VERSION 5.8 ;
BUSBITCHARS "[]" ;
DIVIDERCHAR "/" ;
UNITS
    DATABASE MICRONS 1000 ;
END UNITS

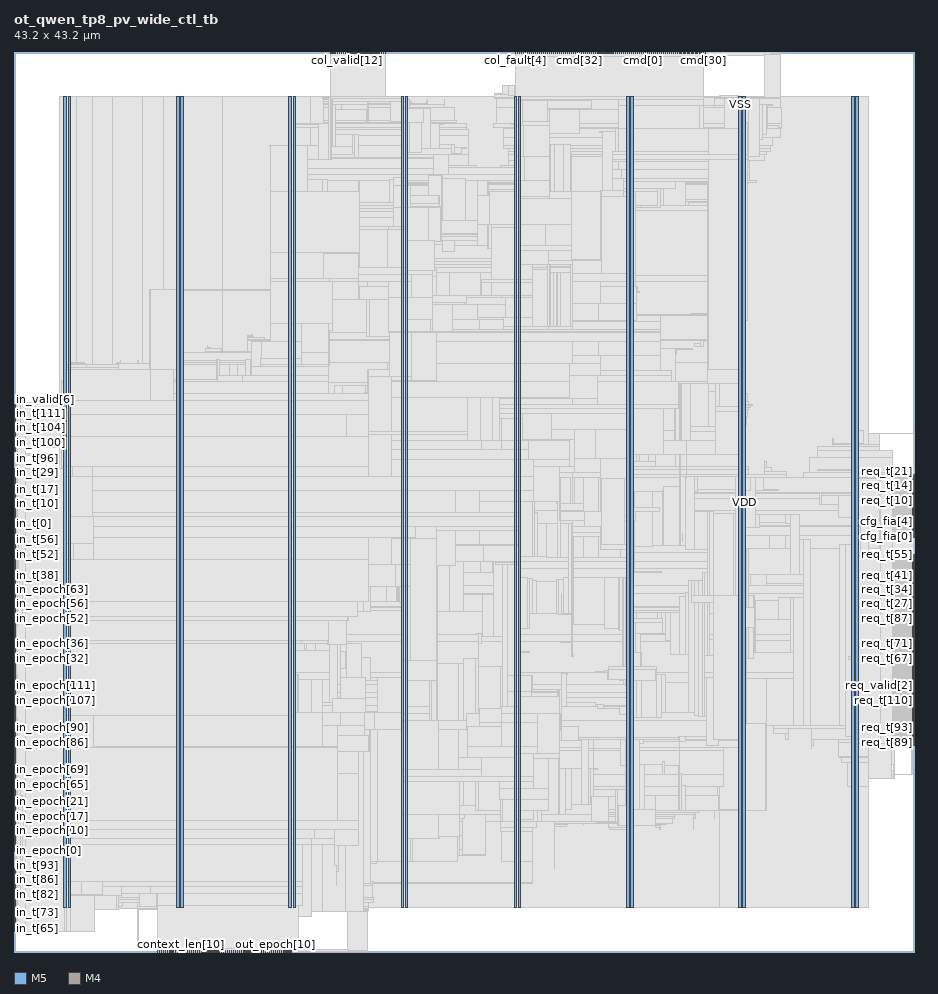
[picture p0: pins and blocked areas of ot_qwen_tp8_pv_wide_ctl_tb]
MACRO ot_qwen_tp8_pv_wide_ctl_tb
  FOREIGN ot_qwen_tp8_pv_wide_ctl_tb 0 0 ;
  CLASS BLOCK ;
  SIZE 43.2 BY 43.2 ;
  PIN busy
    DIRECTION OUTPUT ;
    USE SIGNAL ;
    PORT
      LAYER M5 ;
        RECT  6.864 0 6.888 0.084 ;
    END
  END busy
  PIN cfg_fia[0]
    DIRECTION INPUT ;
    USE SIGNAL ;
    PORT
      LAYER M4 ;
        RECT  43.116 19.92 43.2 19.944 ;
    END
  END cfg_fia[0]
  PIN cfg_fia[1]
    DIRECTION INPUT ;
    USE SIGNAL ;
    PORT
      LAYER M4 ;
        RECT  43.116 20.016 43.2 20.04 ;
    END
  END cfg_fia[1]
  PIN cfg_fia[2]
    DIRECTION INPUT ;
    USE SIGNAL ;
    PORT
      LAYER M4 ;
        RECT  43.116 20.112 43.2 20.136 ;
    END
  END cfg_fia[2]
  PIN cfg_fia[3]
    DIRECTION INPUT ;
    USE SIGNAL ;
    PORT
      LAYER M4 ;
        RECT  43.116 20.208 43.2 20.232 ;
    END
  END cfg_fia[3]
  PIN cfg_fia[4]
    DIRECTION INPUT ;
    USE SIGNAL ;
    PORT
      LAYER M4 ;
        RECT  43.116 20.304 43.2 20.328 ;
    END
  END cfg_fia[4]
  PIN cfg_fia[5]
    DIRECTION INPUT ;
    USE SIGNAL ;
    PORT
      LAYER M4 ;
        RECT  43.116 20.4 43.2 20.424 ;
    END
  END cfg_fia[5]
  PIN cfg_fia[6]
    DIRECTION INPUT ;
    USE SIGNAL ;
    PORT
      LAYER M4 ;
        RECT  43.116 20.496 43.2 20.52 ;
    END
  END cfg_fia[6]
  PIN cfg_fia[7]
    DIRECTION INPUT ;
    USE SIGNAL ;
    PORT
      LAYER M4 ;
        RECT  43.116 20.592 43.2 20.616 ;
    END
  END cfg_fia[7]
  PIN clk
    DIRECTION INPUT ;
    USE SIGNAL ;
    PORT
      LAYER M5 ;
        RECT  6.96 0 6.984 0.084 ;
    END
  END clk
  PIN cmd[0]
    DIRECTION OUTPUT ;
    USE SIGNAL ;
    PORT
      LAYER M5 ;
        RECT  30.192 43.116 30.216 43.2 ;
    END
  END cmd[0]
  PIN cmd[10]
    DIRECTION OUTPUT ;
    USE SIGNAL ;
    PORT
      LAYER M5 ;
        RECT  31.152 43.116 31.176 43.2 ;
    END
  END cmd[10]
  PIN cmd[11]
    DIRECTION OUTPUT ;
    USE SIGNAL ;
    PORT
      LAYER M5 ;
        RECT  31.248 43.116 31.272 43.2 ;
    END
  END cmd[11]
  PIN cmd[12]
    DIRECTION OUTPUT ;
    USE SIGNAL ;
    PORT
      LAYER M5 ;
        RECT  31.344 43.116 31.368 43.2 ;
    END
  END cmd[12]
  PIN cmd[13]
    DIRECTION OUTPUT ;
    USE SIGNAL ;
    PORT
      LAYER M5 ;
        RECT  31.44 43.116 31.464 43.2 ;
    END
  END cmd[13]
  PIN cmd[14]
    DIRECTION OUTPUT ;
    USE SIGNAL ;
    PORT
      LAYER M5 ;
        RECT  31.536 43.116 31.56 43.2 ;
    END
  END cmd[14]
  PIN cmd[15]
    DIRECTION OUTPUT ;
    USE SIGNAL ;
    PORT
      LAYER M5 ;
        RECT  31.632 43.116 31.656 43.2 ;
    END
  END cmd[15]
  PIN cmd[16]
    DIRECTION OUTPUT ;
    USE SIGNAL ;
    PORT
      LAYER M5 ;
        RECT  31.728 43.116 31.752 43.2 ;
    END
  END cmd[16]
  PIN cmd[17]
    DIRECTION OUTPUT ;
    USE SIGNAL ;
    PORT
      LAYER M5 ;
        RECT  31.824 43.116 31.848 43.2 ;
    END
  END cmd[17]
  PIN cmd[18]
    DIRECTION OUTPUT ;
    USE SIGNAL ;
    PORT
      LAYER M5 ;
        RECT  31.92 43.116 31.944 43.2 ;
    END
  END cmd[18]
  PIN cmd[19]
    DIRECTION OUTPUT ;
    USE SIGNAL ;
    PORT
      LAYER M5 ;
        RECT  32.016 43.116 32.04 43.2 ;
    END
  END cmd[19]
  PIN cmd[1]
    DIRECTION OUTPUT ;
    USE SIGNAL ;
    PORT
      LAYER M5 ;
        RECT  30.288 43.116 30.312 43.2 ;
    END
  END cmd[1]
  PIN cmd[20]
    DIRECTION OUTPUT ;
    USE SIGNAL ;
    PORT
      LAYER M5 ;
        RECT  32.112 43.116 32.136 43.2 ;
    END
  END cmd[20]
  PIN cmd[21]
    DIRECTION OUTPUT ;
    USE SIGNAL ;
    PORT
      LAYER M5 ;
        RECT  32.208 43.116 32.232 43.2 ;
    END
  END cmd[21]
  PIN cmd[22]
    DIRECTION OUTPUT ;
    USE SIGNAL ;
    PORT
      LAYER M5 ;
        RECT  32.304 43.116 32.328 43.2 ;
    END
  END cmd[22]
  PIN cmd[23]
    DIRECTION OUTPUT ;
    USE SIGNAL ;
    PORT
      LAYER M5 ;
        RECT  32.4 43.116 32.424 43.2 ;
    END
  END cmd[23]
  PIN cmd[24]
    DIRECTION OUTPUT ;
    USE SIGNAL ;
    PORT
      LAYER M5 ;
        RECT  32.496 43.116 32.52 43.2 ;
    END
  END cmd[24]
  PIN cmd[25]
    DIRECTION OUTPUT ;
    USE SIGNAL ;
    PORT
      LAYER M5 ;
        RECT  32.592 43.116 32.616 43.2 ;
    END
  END cmd[25]
  PIN cmd[26]
    DIRECTION OUTPUT ;
    USE SIGNAL ;
    PORT
      LAYER M5 ;
        RECT  32.688 43.116 32.712 43.2 ;
    END
  END cmd[26]
  PIN cmd[27]
    DIRECTION OUTPUT ;
    USE SIGNAL ;
    PORT
      LAYER M5 ;
        RECT  32.784 43.116 32.808 43.2 ;
    END
  END cmd[27]
  PIN cmd[28]
    DIRECTION OUTPUT ;
    USE SIGNAL ;
    PORT
      LAYER M5 ;
        RECT  32.88 43.116 32.904 43.2 ;
    END
  END cmd[28]
  PIN cmd[29]
    DIRECTION OUTPUT ;
    USE SIGNAL ;
    PORT
      LAYER M5 ;
        RECT  32.976 43.116 33 43.2 ;
    END
  END cmd[29]
  PIN cmd[2]
    DIRECTION OUTPUT ;
    USE SIGNAL ;
    PORT
      LAYER M5 ;
        RECT  30.384 43.116 30.408 43.2 ;
    END
  END cmd[2]
  PIN cmd[30]
    DIRECTION OUTPUT ;
    USE SIGNAL ;
    PORT
      LAYER M5 ;
        RECT  33.072 43.116 33.096 43.2 ;
    END
  END cmd[30]
  PIN cmd[31]
    DIRECTION OUTPUT ;
    USE SIGNAL ;
    PORT
      LAYER M5 ;
        RECT  33.168 43.116 33.192 43.2 ;
    END
  END cmd[31]
  PIN cmd[32]
    DIRECTION OUTPUT ;
    USE SIGNAL ;
    PORT
      LAYER M5 ;
        RECT  27.12 43.116 27.144 43.2 ;
    END
  END cmd[32]
  PIN cmd[33]
    DIRECTION OUTPUT ;
    USE SIGNAL ;
    PORT
      LAYER M5 ;
        RECT  27.216 43.116 27.24 43.2 ;
    END
  END cmd[33]
  PIN cmd[34]
    DIRECTION OUTPUT ;
    USE SIGNAL ;
    PORT
      LAYER M5 ;
        RECT  27.312 43.116 27.336 43.2 ;
    END
  END cmd[34]
  PIN cmd[35]
    DIRECTION OUTPUT ;
    USE SIGNAL ;
    PORT
      LAYER M5 ;
        RECT  27.408 43.116 27.432 43.2 ;
    END
  END cmd[35]
  PIN cmd[36]
    DIRECTION OUTPUT ;
    USE SIGNAL ;
    PORT
      LAYER M5 ;
        RECT  27.504 43.116 27.528 43.2 ;
    END
  END cmd[36]
  PIN cmd[37]
    DIRECTION OUTPUT ;
    USE SIGNAL ;
    PORT
      LAYER M5 ;
        RECT  27.6 43.116 27.624 43.2 ;
    END
  END cmd[37]
  PIN cmd[38]
    DIRECTION OUTPUT ;
    USE SIGNAL ;
    PORT
      LAYER M5 ;
        RECT  27.696 43.116 27.72 43.2 ;
    END
  END cmd[38]
  PIN cmd[39]
    DIRECTION OUTPUT ;
    USE SIGNAL ;
    PORT
      LAYER M5 ;
        RECT  27.792 43.116 27.816 43.2 ;
    END
  END cmd[39]
  PIN cmd[3]
    DIRECTION OUTPUT ;
    USE SIGNAL ;
    PORT
      LAYER M5 ;
        RECT  30.48 43.116 30.504 43.2 ;
    END
  END cmd[3]
  PIN cmd[40]
    DIRECTION OUTPUT ;
    USE SIGNAL ;
    PORT
      LAYER M5 ;
        RECT  27.888 43.116 27.912 43.2 ;
    END
  END cmd[40]
  PIN cmd[41]
    DIRECTION OUTPUT ;
    USE SIGNAL ;
    PORT
      LAYER M5 ;
        RECT  27.984 43.116 28.008 43.2 ;
    END
  END cmd[41]
  PIN cmd[42]
    DIRECTION OUTPUT ;
    USE SIGNAL ;
    PORT
      LAYER M5 ;
        RECT  28.08 43.116 28.104 43.2 ;
    END
  END cmd[42]
  PIN cmd[43]
    DIRECTION OUTPUT ;
    USE SIGNAL ;
    PORT
      LAYER M5 ;
        RECT  28.176 43.116 28.2 43.2 ;
    END
  END cmd[43]
  PIN cmd[44]
    DIRECTION OUTPUT ;
    USE SIGNAL ;
    PORT
      LAYER M5 ;
        RECT  28.272 43.116 28.296 43.2 ;
    END
  END cmd[44]
  PIN cmd[45]
    DIRECTION OUTPUT ;
    USE SIGNAL ;
    PORT
      LAYER M5 ;
        RECT  28.368 43.116 28.392 43.2 ;
    END
  END cmd[45]
  PIN cmd[46]
    DIRECTION OUTPUT ;
    USE SIGNAL ;
    PORT
      LAYER M5 ;
        RECT  28.464 43.116 28.488 43.2 ;
    END
  END cmd[46]
  PIN cmd[47]
    DIRECTION OUTPUT ;
    USE SIGNAL ;
    PORT
      LAYER M5 ;
        RECT  28.56 43.116 28.584 43.2 ;
    END
  END cmd[47]
  PIN cmd[48]
    DIRECTION OUTPUT ;
    USE SIGNAL ;
    PORT
      LAYER M5 ;
        RECT  28.656 43.116 28.68 43.2 ;
    END
  END cmd[48]
  PIN cmd[49]
    DIRECTION OUTPUT ;
    USE SIGNAL ;
    PORT
      LAYER M5 ;
        RECT  28.752 43.116 28.776 43.2 ;
    END
  END cmd[49]
  PIN cmd[4]
    DIRECTION OUTPUT ;
    USE SIGNAL ;
    PORT
      LAYER M5 ;
        RECT  30.576 43.116 30.6 43.2 ;
    END
  END cmd[4]
  PIN cmd[50]
    DIRECTION OUTPUT ;
    USE SIGNAL ;
    PORT
      LAYER M5 ;
        RECT  28.848 43.116 28.872 43.2 ;
    END
  END cmd[50]
  PIN cmd[51]
    DIRECTION OUTPUT ;
    USE SIGNAL ;
    PORT
      LAYER M5 ;
        RECT  28.944 43.116 28.968 43.2 ;
    END
  END cmd[51]
  PIN cmd[52]
    DIRECTION OUTPUT ;
    USE SIGNAL ;
    PORT
      LAYER M5 ;
        RECT  29.04 43.116 29.064 43.2 ;
    END
  END cmd[52]
  PIN cmd[53]
    DIRECTION OUTPUT ;
    USE SIGNAL ;
    PORT
      LAYER M5 ;
        RECT  29.136 43.116 29.16 43.2 ;
    END
  END cmd[53]
  PIN cmd[54]
    DIRECTION OUTPUT ;
    USE SIGNAL ;
    PORT
      LAYER M5 ;
        RECT  29.232 43.116 29.256 43.2 ;
    END
  END cmd[54]
  PIN cmd[55]
    DIRECTION OUTPUT ;
    USE SIGNAL ;
    PORT
      LAYER M5 ;
        RECT  29.328 43.116 29.352 43.2 ;
    END
  END cmd[55]
  PIN cmd[56]
    DIRECTION OUTPUT ;
    USE SIGNAL ;
    PORT
      LAYER M5 ;
        RECT  29.424 43.116 29.448 43.2 ;
    END
  END cmd[56]
  PIN cmd[57]
    DIRECTION OUTPUT ;
    USE SIGNAL ;
    PORT
      LAYER M5 ;
        RECT  29.52 43.116 29.544 43.2 ;
    END
  END cmd[57]
  PIN cmd[58]
    DIRECTION OUTPUT ;
    USE SIGNAL ;
    PORT
      LAYER M5 ;
        RECT  29.616 43.116 29.64 43.2 ;
    END
  END cmd[58]
  PIN cmd[59]
    DIRECTION OUTPUT ;
    USE SIGNAL ;
    PORT
      LAYER M5 ;
        RECT  29.712 43.116 29.736 43.2 ;
    END
  END cmd[59]
  PIN cmd[5]
    DIRECTION OUTPUT ;
    USE SIGNAL ;
    PORT
      LAYER M5 ;
        RECT  30.672 43.116 30.696 43.2 ;
    END
  END cmd[5]
  PIN cmd[6]
    DIRECTION OUTPUT ;
    USE SIGNAL ;
    PORT
      LAYER M5 ;
        RECT  30.768 43.116 30.792 43.2 ;
    END
  END cmd[6]
  PIN cmd[7]
    DIRECTION OUTPUT ;
    USE SIGNAL ;
    PORT
      LAYER M5 ;
        RECT  30.864 43.116 30.888 43.2 ;
    END
  END cmd[7]
  PIN cmd[8]
    DIRECTION OUTPUT ;
    USE SIGNAL ;
    PORT
      LAYER M5 ;
        RECT  30.96 43.116 30.984 43.2 ;
    END
  END cmd[8]
  PIN cmd[9]
    DIRECTION OUTPUT ;
    USE SIGNAL ;
    PORT
      LAYER M5 ;
        RECT  31.056 43.116 31.08 43.2 ;
    END
  END cmd[9]
  PIN col_fault[0]
    DIRECTION INPUT ;
    USE SIGNAL ;
    PORT
      LAYER M5 ;
        RECT  29.808 43.116 29.832 43.2 ;
    END
  END col_fault[0]
  PIN col_fault[10]
    DIRECTION INPUT ;
    USE SIGNAL ;
    PORT
      LAYER M5 ;
        RECT  24.624 43.116 24.648 43.2 ;
    END
  END col_fault[10]
  PIN col_fault[11]
    DIRECTION INPUT ;
    USE SIGNAL ;
    PORT
      LAYER M5 ;
        RECT  24.72 43.116 24.744 43.2 ;
    END
  END col_fault[11]
  PIN col_fault[12]
    DIRECTION INPUT ;
    USE SIGNAL ;
    PORT
      LAYER M5 ;
        RECT  24.816 43.116 24.84 43.2 ;
    END
  END col_fault[12]
  PIN col_fault[13]
    DIRECTION INPUT ;
    USE SIGNAL ;
    PORT
      LAYER M5 ;
        RECT  24.912 43.116 24.936 43.2 ;
    END
  END col_fault[13]
  PIN col_fault[14]
    DIRECTION INPUT ;
    USE SIGNAL ;
    PORT
      LAYER M5 ;
        RECT  25.008 43.116 25.032 43.2 ;
    END
  END col_fault[14]
  PIN col_fault[15]
    DIRECTION INPUT ;
    USE SIGNAL ;
    PORT
      LAYER M5 ;
        RECT  25.104 43.116 25.128 43.2 ;
    END
  END col_fault[15]
  PIN col_fault[16]
    DIRECTION INPUT ;
    USE SIGNAL ;
    PORT
      LAYER M5 ;
        RECT  25.2 43.116 25.224 43.2 ;
    END
  END col_fault[16]
  PIN col_fault[17]
    DIRECTION INPUT ;
    USE SIGNAL ;
    PORT
      LAYER M5 ;
        RECT  25.296 43.116 25.32 43.2 ;
    END
  END col_fault[17]
  PIN col_fault[18]
    DIRECTION INPUT ;
    USE SIGNAL ;
    PORT
      LAYER M5 ;
        RECT  25.392 43.116 25.416 43.2 ;
    END
  END col_fault[18]
  PIN col_fault[19]
    DIRECTION INPUT ;
    USE SIGNAL ;
    PORT
      LAYER M5 ;
        RECT  25.488 43.116 25.512 43.2 ;
    END
  END col_fault[19]
  PIN col_fault[1]
    DIRECTION INPUT ;
    USE SIGNAL ;
    PORT
      LAYER M5 ;
        RECT  29.904 43.116 29.928 43.2 ;
    END
  END col_fault[1]
  PIN col_fault[20]
    DIRECTION INPUT ;
    USE SIGNAL ;
    PORT
      LAYER M5 ;
        RECT  25.584 43.116 25.608 43.2 ;
    END
  END col_fault[20]
  PIN col_fault[21]
    DIRECTION INPUT ;
    USE SIGNAL ;
    PORT
      LAYER M5 ;
        RECT  25.68 43.116 25.704 43.2 ;
    END
  END col_fault[21]
  PIN col_fault[22]
    DIRECTION INPUT ;
    USE SIGNAL ;
    PORT
      LAYER M5 ;
        RECT  25.776 43.116 25.8 43.2 ;
    END
  END col_fault[22]
  PIN col_fault[23]
    DIRECTION INPUT ;
    USE SIGNAL ;
    PORT
      LAYER M5 ;
        RECT  25.872 43.116 25.896 43.2 ;
    END
  END col_fault[23]
  PIN col_fault[24]
    DIRECTION INPUT ;
    USE SIGNAL ;
    PORT
      LAYER M5 ;
        RECT  25.968 43.116 25.992 43.2 ;
    END
  END col_fault[24]
  PIN col_fault[25]
    DIRECTION INPUT ;
    USE SIGNAL ;
    PORT
      LAYER M5 ;
        RECT  26.064 43.116 26.088 43.2 ;
    END
  END col_fault[25]
  PIN col_fault[26]
    DIRECTION INPUT ;
    USE SIGNAL ;
    PORT
      LAYER M5 ;
        RECT  26.16 43.116 26.184 43.2 ;
    END
  END col_fault[26]
  PIN col_fault[27]
    DIRECTION INPUT ;
    USE SIGNAL ;
    PORT
      LAYER M5 ;
        RECT  26.256 43.116 26.28 43.2 ;
    END
  END col_fault[27]
  PIN col_fault[28]
    DIRECTION INPUT ;
    USE SIGNAL ;
    PORT
      LAYER M5 ;
        RECT  26.352 43.116 26.376 43.2 ;
    END
  END col_fault[28]
  PIN col_fault[29]
    DIRECTION INPUT ;
    USE SIGNAL ;
    PORT
      LAYER M5 ;
        RECT  26.448 43.116 26.472 43.2 ;
    END
  END col_fault[29]
  PIN col_fault[2]
    DIRECTION INPUT ;
    USE SIGNAL ;
    PORT
      LAYER M5 ;
        RECT  30 43.116 30.024 43.2 ;
    END
  END col_fault[2]
  PIN col_fault[30]
    DIRECTION INPUT ;
    USE SIGNAL ;
    PORT
      LAYER M5 ;
        RECT  26.544 43.116 26.568 43.2 ;
    END
  END col_fault[30]
  PIN col_fault[31]
    DIRECTION INPUT ;
    USE SIGNAL ;
    PORT
      LAYER M5 ;
        RECT  26.64 43.116 26.664 43.2 ;
    END
  END col_fault[31]
  PIN col_fault[3]
    DIRECTION INPUT ;
    USE SIGNAL ;
    PORT
      LAYER M5 ;
        RECT  30.096 43.116 30.12 43.2 ;
    END
  END col_fault[3]
  PIN col_fault[4]
    DIRECTION INPUT ;
    USE SIGNAL ;
    PORT
      LAYER M5 ;
        RECT  24.048 43.116 24.072 43.2 ;
    END
  END col_fault[4]
  PIN col_fault[5]
    DIRECTION INPUT ;
    USE SIGNAL ;
    PORT
      LAYER M5 ;
        RECT  24.144 43.116 24.168 43.2 ;
    END
  END col_fault[5]
  PIN col_fault[6]
    DIRECTION INPUT ;
    USE SIGNAL ;
    PORT
      LAYER M5 ;
        RECT  24.24 43.116 24.264 43.2 ;
    END
  END col_fault[6]
  PIN col_fault[7]
    DIRECTION INPUT ;
    USE SIGNAL ;
    PORT
      LAYER M5 ;
        RECT  24.336 43.116 24.36 43.2 ;
    END
  END col_fault[7]
  PIN col_fault[8]
    DIRECTION INPUT ;
    USE SIGNAL ;
    PORT
      LAYER M5 ;
        RECT  24.432 43.116 24.456 43.2 ;
    END
  END col_fault[8]
  PIN col_fault[9]
    DIRECTION INPUT ;
    USE SIGNAL ;
    PORT
      LAYER M5 ;
        RECT  24.528 43.116 24.552 43.2 ;
    END
  END col_fault[9]
  PIN col_valid[0]
    DIRECTION INPUT ;
    USE SIGNAL ;
    PORT
      LAYER M5 ;
        RECT  26.736 43.116 26.76 43.2 ;
    END
  END col_valid[0]
  PIN col_valid[10]
    DIRECTION INPUT ;
    USE SIGNAL ;
    PORT
      LAYER M5 ;
        RECT  15.792 43.116 15.816 43.2 ;
    END
  END col_valid[10]
  PIN col_valid[11]
    DIRECTION INPUT ;
    USE SIGNAL ;
    PORT
      LAYER M5 ;
        RECT  15.888 43.116 15.912 43.2 ;
    END
  END col_valid[11]
  PIN col_valid[12]
    DIRECTION INPUT ;
    USE SIGNAL ;
    PORT
      LAYER M5 ;
        RECT  15.984 43.116 16.008 43.2 ;
    END
  END col_valid[12]
  PIN col_valid[13]
    DIRECTION INPUT ;
    USE SIGNAL ;
    PORT
      LAYER M5 ;
        RECT  16.08 43.116 16.104 43.2 ;
    END
  END col_valid[13]
  PIN col_valid[14]
    DIRECTION INPUT ;
    USE SIGNAL ;
    PORT
      LAYER M5 ;
        RECT  16.176 43.116 16.2 43.2 ;
    END
  END col_valid[14]
  PIN col_valid[15]
    DIRECTION INPUT ;
    USE SIGNAL ;
    PORT
      LAYER M5 ;
        RECT  16.272 43.116 16.296 43.2 ;
    END
  END col_valid[15]
  PIN col_valid[16]
    DIRECTION INPUT ;
    USE SIGNAL ;
    PORT
      LAYER M5 ;
        RECT  16.368 43.116 16.392 43.2 ;
    END
  END col_valid[16]
  PIN col_valid[17]
    DIRECTION INPUT ;
    USE SIGNAL ;
    PORT
      LAYER M5 ;
        RECT  16.464 43.116 16.488 43.2 ;
    END
  END col_valid[17]
  PIN col_valid[18]
    DIRECTION INPUT ;
    USE SIGNAL ;
    PORT
      LAYER M5 ;
        RECT  16.56 43.116 16.584 43.2 ;
    END
  END col_valid[18]
  PIN col_valid[19]
    DIRECTION INPUT ;
    USE SIGNAL ;
    PORT
      LAYER M5 ;
        RECT  16.656 43.116 16.68 43.2 ;
    END
  END col_valid[19]
  PIN col_valid[1]
    DIRECTION INPUT ;
    USE SIGNAL ;
    PORT
      LAYER M5 ;
        RECT  26.832 43.116 26.856 43.2 ;
    END
  END col_valid[1]
  PIN col_valid[20]
    DIRECTION INPUT ;
    USE SIGNAL ;
    PORT
      LAYER M5 ;
        RECT  16.752 43.116 16.776 43.2 ;
    END
  END col_valid[20]
  PIN col_valid[21]
    DIRECTION INPUT ;
    USE SIGNAL ;
    PORT
      LAYER M5 ;
        RECT  16.848 43.116 16.872 43.2 ;
    END
  END col_valid[21]
  PIN col_valid[22]
    DIRECTION INPUT ;
    USE SIGNAL ;
    PORT
      LAYER M5 ;
        RECT  16.944 43.116 16.968 43.2 ;
    END
  END col_valid[22]
  PIN col_valid[23]
    DIRECTION INPUT ;
    USE SIGNAL ;
    PORT
      LAYER M5 ;
        RECT  17.04 43.116 17.064 43.2 ;
    END
  END col_valid[23]
  PIN col_valid[24]
    DIRECTION INPUT ;
    USE SIGNAL ;
    PORT
      LAYER M5 ;
        RECT  17.136 43.116 17.16 43.2 ;
    END
  END col_valid[24]
  PIN col_valid[25]
    DIRECTION INPUT ;
    USE SIGNAL ;
    PORT
      LAYER M5 ;
        RECT  17.232 43.116 17.256 43.2 ;
    END
  END col_valid[25]
  PIN col_valid[26]
    DIRECTION INPUT ;
    USE SIGNAL ;
    PORT
      LAYER M5 ;
        RECT  17.328 43.116 17.352 43.2 ;
    END
  END col_valid[26]
  PIN col_valid[27]
    DIRECTION INPUT ;
    USE SIGNAL ;
    PORT
      LAYER M5 ;
        RECT  17.424 43.116 17.448 43.2 ;
    END
  END col_valid[27]
  PIN col_valid[28]
    DIRECTION INPUT ;
    USE SIGNAL ;
    PORT
      LAYER M5 ;
        RECT  17.52 43.116 17.544 43.2 ;
    END
  END col_valid[28]
  PIN col_valid[29]
    DIRECTION INPUT ;
    USE SIGNAL ;
    PORT
      LAYER M5 ;
        RECT  17.616 43.116 17.64 43.2 ;
    END
  END col_valid[29]
  PIN col_valid[2]
    DIRECTION INPUT ;
    USE SIGNAL ;
    PORT
      LAYER M5 ;
        RECT  26.928 43.116 26.952 43.2 ;
    END
  END col_valid[2]
  PIN col_valid[30]
    DIRECTION INPUT ;
    USE SIGNAL ;
    PORT
      LAYER M5 ;
        RECT  17.712 43.116 17.736 43.2 ;
    END
  END col_valid[30]
  PIN col_valid[31]
    DIRECTION INPUT ;
    USE SIGNAL ;
    PORT
      LAYER M5 ;
        RECT  17.808 43.116 17.832 43.2 ;
    END
  END col_valid[31]
  PIN col_valid[3]
    DIRECTION INPUT ;
    USE SIGNAL ;
    PORT
      LAYER M5 ;
        RECT  27.024 43.116 27.048 43.2 ;
    END
  END col_valid[3]
  PIN col_valid[4]
    DIRECTION INPUT ;
    USE SIGNAL ;
    PORT
      LAYER M5 ;
        RECT  15.216 43.116 15.24 43.2 ;
    END
  END col_valid[4]
  PIN col_valid[5]
    DIRECTION INPUT ;
    USE SIGNAL ;
    PORT
      LAYER M5 ;
        RECT  15.312 43.116 15.336 43.2 ;
    END
  END col_valid[5]
  PIN col_valid[6]
    DIRECTION INPUT ;
    USE SIGNAL ;
    PORT
      LAYER M5 ;
        RECT  15.408 43.116 15.432 43.2 ;
    END
  END col_valid[6]
  PIN col_valid[7]
    DIRECTION INPUT ;
    USE SIGNAL ;
    PORT
      LAYER M5 ;
        RECT  15.504 43.116 15.528 43.2 ;
    END
  END col_valid[7]
  PIN col_valid[8]
    DIRECTION INPUT ;
    USE SIGNAL ;
    PORT
      LAYER M5 ;
        RECT  15.6 43.116 15.624 43.2 ;
    END
  END col_valid[8]
  PIN col_valid[9]
    DIRECTION INPUT ;
    USE SIGNAL ;
    PORT
      LAYER M5 ;
        RECT  15.696 43.116 15.72 43.2 ;
    END
  END col_valid[9]
  PIN context_len[0]
    DIRECTION INPUT ;
    USE SIGNAL ;
    PORT
      LAYER M5 ;
        RECT  7.056 0 7.08 0.084 ;
    END
  END context_len[0]
  PIN context_len[10]
    DIRECTION INPUT ;
    USE SIGNAL ;
    PORT
      LAYER M5 ;
        RECT  8.016 0 8.04 0.084 ;
    END
  END context_len[10]
  PIN context_len[11]
    DIRECTION INPUT ;
    USE SIGNAL ;
    PORT
      LAYER M5 ;
        RECT  8.112 0 8.136 0.084 ;
    END
  END context_len[11]
  PIN context_len[12]
    DIRECTION INPUT ;
    USE SIGNAL ;
    PORT
      LAYER M5 ;
        RECT  8.208 0 8.232 0.084 ;
    END
  END context_len[12]
  PIN context_len[13]
    DIRECTION INPUT ;
    USE SIGNAL ;
    PORT
      LAYER M5 ;
        RECT  8.304 0 8.328 0.084 ;
    END
  END context_len[13]
  PIN context_len[1]
    DIRECTION INPUT ;
    USE SIGNAL ;
    PORT
      LAYER M5 ;
        RECT  7.152 0 7.176 0.084 ;
    END
  END context_len[1]
  PIN context_len[2]
    DIRECTION INPUT ;
    USE SIGNAL ;
    PORT
      LAYER M5 ;
        RECT  7.248 0 7.272 0.084 ;
    END
  END context_len[2]
  PIN context_len[3]
    DIRECTION INPUT ;
    USE SIGNAL ;
    PORT
      LAYER M5 ;
        RECT  7.344 0 7.368 0.084 ;
    END
  END context_len[3]
  PIN context_len[4]
    DIRECTION INPUT ;
    USE SIGNAL ;
    PORT
      LAYER M5 ;
        RECT  7.44 0 7.464 0.084 ;
    END
  END context_len[4]
  PIN context_len[5]
    DIRECTION INPUT ;
    USE SIGNAL ;
    PORT
      LAYER M5 ;
        RECT  7.536 0 7.56 0.084 ;
    END
  END context_len[5]
  PIN context_len[6]
    DIRECTION INPUT ;
    USE SIGNAL ;
    PORT
      LAYER M5 ;
        RECT  7.632 0 7.656 0.084 ;
    END
  END context_len[6]
  PIN context_len[7]
    DIRECTION INPUT ;
    USE SIGNAL ;
    PORT
      LAYER M5 ;
        RECT  7.728 0 7.752 0.084 ;
    END
  END context_len[7]
  PIN context_len[8]
    DIRECTION INPUT ;
    USE SIGNAL ;
    PORT
      LAYER M5 ;
        RECT  7.824 0 7.848 0.084 ;
    END
  END context_len[8]
  PIN context_len[9]
    DIRECTION INPUT ;
    USE SIGNAL ;
    PORT
      LAYER M5 ;
        RECT  7.92 0 7.944 0.084 ;
    END
  END context_len[9]
  PIN epoch[0]
    DIRECTION INPUT ;
    USE SIGNAL ;
    PORT
      LAYER M5 ;
        RECT  8.4 0 8.424 0.084 ;
    END
  END epoch[0]
  PIN epoch[10]
    DIRECTION INPUT ;
    USE SIGNAL ;
    PORT
      LAYER M5 ;
        RECT  9.36 0 9.384 0.084 ;
    END
  END epoch[10]
  PIN epoch[11]
    DIRECTION INPUT ;
    USE SIGNAL ;
    PORT
      LAYER M5 ;
        RECT  9.456 0 9.48 0.084 ;
    END
  END epoch[11]
  PIN epoch[12]
    DIRECTION INPUT ;
    USE SIGNAL ;
    PORT
      LAYER M5 ;
        RECT  9.552 0 9.576 0.084 ;
    END
  END epoch[12]
  PIN epoch[13]
    DIRECTION INPUT ;
    USE SIGNAL ;
    PORT
      LAYER M5 ;
        RECT  9.648 0 9.672 0.084 ;
    END
  END epoch[13]
  PIN epoch[14]
    DIRECTION INPUT ;
    USE SIGNAL ;
    PORT
      LAYER M5 ;
        RECT  9.744 0 9.768 0.084 ;
    END
  END epoch[14]
  PIN epoch[15]
    DIRECTION INPUT ;
    USE SIGNAL ;
    PORT
      LAYER M5 ;
        RECT  9.84 0 9.864 0.084 ;
    END
  END epoch[15]
  PIN epoch[1]
    DIRECTION INPUT ;
    USE SIGNAL ;
    PORT
      LAYER M5 ;
        RECT  8.496 0 8.52 0.084 ;
    END
  END epoch[1]
  PIN epoch[2]
    DIRECTION INPUT ;
    USE SIGNAL ;
    PORT
      LAYER M5 ;
        RECT  8.592 0 8.616 0.084 ;
    END
  END epoch[2]
  PIN epoch[3]
    DIRECTION INPUT ;
    USE SIGNAL ;
    PORT
      LAYER M5 ;
        RECT  8.688 0 8.712 0.084 ;
    END
  END epoch[3]
  PIN epoch[4]
    DIRECTION INPUT ;
    USE SIGNAL ;
    PORT
      LAYER M5 ;
        RECT  8.784 0 8.808 0.084 ;
    END
  END epoch[4]
  PIN epoch[5]
    DIRECTION INPUT ;
    USE SIGNAL ;
    PORT
      LAYER M5 ;
        RECT  8.88 0 8.904 0.084 ;
    END
  END epoch[5]
  PIN epoch[6]
    DIRECTION INPUT ;
    USE SIGNAL ;
    PORT
      LAYER M5 ;
        RECT  8.976 0 9 0.084 ;
    END
  END epoch[6]
  PIN epoch[7]
    DIRECTION INPUT ;
    USE SIGNAL ;
    PORT
      LAYER M5 ;
        RECT  9.072 0 9.096 0.084 ;
    END
  END epoch[7]
  PIN epoch[8]
    DIRECTION INPUT ;
    USE SIGNAL ;
    PORT
      LAYER M5 ;
        RECT  9.168 0 9.192 0.084 ;
    END
  END epoch[8]
  PIN epoch[9]
    DIRECTION INPUT ;
    USE SIGNAL ;
    PORT
      LAYER M5 ;
        RECT  9.264 0 9.288 0.084 ;
    END
  END epoch[9]
  PIN fault
    DIRECTION OUTPUT ;
    USE SIGNAL ;
    PORT
      LAYER M5 ;
        RECT  9.936 0 9.96 0.084 ;
    END
  END fault
  PIN in_epoch[0]
    DIRECTION INPUT ;
    USE SIGNAL ;
    PORT
      LAYER M4 ;
        RECT  0 4.848 0.084 4.872 ;
    END
  END in_epoch[0]
  PIN in_epoch[100]
    DIRECTION INPUT ;
    USE SIGNAL ;
    PORT
      LAYER M4 ;
        RECT  0 11.376 0.084 11.4 ;
    END
  END in_epoch[100]
  PIN in_epoch[101]
    DIRECTION INPUT ;
    USE SIGNAL ;
    PORT
      LAYER M4 ;
        RECT  0 11.472 0.084 11.496 ;
    END
  END in_epoch[101]
  PIN in_epoch[102]
    DIRECTION INPUT ;
    USE SIGNAL ;
    PORT
      LAYER M4 ;
        RECT  0 11.568 0.084 11.592 ;
    END
  END in_epoch[102]
  PIN in_epoch[103]
    DIRECTION INPUT ;
    USE SIGNAL ;
    PORT
      LAYER M4 ;
        RECT  0 11.664 0.084 11.688 ;
    END
  END in_epoch[103]
  PIN in_epoch[104]
    DIRECTION INPUT ;
    USE SIGNAL ;
    PORT
      LAYER M4 ;
        RECT  0 11.76 0.084 11.784 ;
    END
  END in_epoch[104]
  PIN in_epoch[105]
    DIRECTION INPUT ;
    USE SIGNAL ;
    PORT
      LAYER M4 ;
        RECT  0 11.856 0.084 11.88 ;
    END
  END in_epoch[105]
  PIN in_epoch[106]
    DIRECTION INPUT ;
    USE SIGNAL ;
    PORT
      LAYER M4 ;
        RECT  0 11.952 0.084 11.976 ;
    END
  END in_epoch[106]
  PIN in_epoch[107]
    DIRECTION INPUT ;
    USE SIGNAL ;
    PORT
      LAYER M4 ;
        RECT  0 12.048 0.084 12.072 ;
    END
  END in_epoch[107]
  PIN in_epoch[108]
    DIRECTION INPUT ;
    USE SIGNAL ;
    PORT
      LAYER M4 ;
        RECT  0 12.144 0.084 12.168 ;
    END
  END in_epoch[108]
  PIN in_epoch[109]
    DIRECTION INPUT ;
    USE SIGNAL ;
    PORT
      LAYER M4 ;
        RECT  0 12.24 0.084 12.264 ;
    END
  END in_epoch[109]
  PIN in_epoch[10]
    DIRECTION INPUT ;
    USE SIGNAL ;
    PORT
      LAYER M4 ;
        RECT  0 5.808 0.084 5.832 ;
    END
  END in_epoch[10]
  PIN in_epoch[110]
    DIRECTION INPUT ;
    USE SIGNAL ;
    PORT
      LAYER M4 ;
        RECT  0 12.336 0.084 12.36 ;
    END
  END in_epoch[110]
  PIN in_epoch[111]
    DIRECTION INPUT ;
    USE SIGNAL ;
    PORT
      LAYER M4 ;
        RECT  0 12.432 0.084 12.456 ;
    END
  END in_epoch[111]
  PIN in_epoch[112]
    DIRECTION INPUT ;
    USE SIGNAL ;
    PORT
      LAYER M4 ;
        RECT  0 12.528 0.084 12.552 ;
    END
  END in_epoch[112]
  PIN in_epoch[113]
    DIRECTION INPUT ;
    USE SIGNAL ;
    PORT
      LAYER M4 ;
        RECT  0 12.624 0.084 12.648 ;
    END
  END in_epoch[113]
  PIN in_epoch[114]
    DIRECTION INPUT ;
    USE SIGNAL ;
    PORT
      LAYER M4 ;
        RECT  0 12.72 0.084 12.744 ;
    END
  END in_epoch[114]
  PIN in_epoch[115]
    DIRECTION INPUT ;
    USE SIGNAL ;
    PORT
      LAYER M4 ;
        RECT  0 12.816 0.084 12.84 ;
    END
  END in_epoch[115]
  PIN in_epoch[116]
    DIRECTION INPUT ;
    USE SIGNAL ;
    PORT
      LAYER M4 ;
        RECT  0 12.912 0.084 12.936 ;
    END
  END in_epoch[116]
  PIN in_epoch[117]
    DIRECTION INPUT ;
    USE SIGNAL ;
    PORT
      LAYER M4 ;
        RECT  0 13.008 0.084 13.032 ;
    END
  END in_epoch[117]
  PIN in_epoch[118]
    DIRECTION INPUT ;
    USE SIGNAL ;
    PORT
      LAYER M4 ;
        RECT  0 13.104 0.084 13.128 ;
    END
  END in_epoch[118]
  PIN in_epoch[119]
    DIRECTION INPUT ;
    USE SIGNAL ;
    PORT
      LAYER M4 ;
        RECT  0 13.2 0.084 13.224 ;
    END
  END in_epoch[119]
  PIN in_epoch[11]
    DIRECTION INPUT ;
    USE SIGNAL ;
    PORT
      LAYER M4 ;
        RECT  0 5.904 0.084 5.928 ;
    END
  END in_epoch[11]
  PIN in_epoch[120]
    DIRECTION INPUT ;
    USE SIGNAL ;
    PORT
      LAYER M4 ;
        RECT  0 13.296 0.084 13.32 ;
    END
  END in_epoch[120]
  PIN in_epoch[121]
    DIRECTION INPUT ;
    USE SIGNAL ;
    PORT
      LAYER M4 ;
        RECT  0 13.392 0.084 13.416 ;
    END
  END in_epoch[121]
  PIN in_epoch[122]
    DIRECTION INPUT ;
    USE SIGNAL ;
    PORT
      LAYER M4 ;
        RECT  0 13.488 0.084 13.512 ;
    END
  END in_epoch[122]
  PIN in_epoch[123]
    DIRECTION INPUT ;
    USE SIGNAL ;
    PORT
      LAYER M4 ;
        RECT  0 13.584 0.084 13.608 ;
    END
  END in_epoch[123]
  PIN in_epoch[124]
    DIRECTION INPUT ;
    USE SIGNAL ;
    PORT
      LAYER M4 ;
        RECT  0 13.68 0.084 13.704 ;
    END
  END in_epoch[124]
  PIN in_epoch[125]
    DIRECTION INPUT ;
    USE SIGNAL ;
    PORT
      LAYER M4 ;
        RECT  0 13.776 0.084 13.8 ;
    END
  END in_epoch[125]
  PIN in_epoch[126]
    DIRECTION INPUT ;
    USE SIGNAL ;
    PORT
      LAYER M4 ;
        RECT  0 13.872 0.084 13.896 ;
    END
  END in_epoch[126]
  PIN in_epoch[127]
    DIRECTION INPUT ;
    USE SIGNAL ;
    PORT
      LAYER M4 ;
        RECT  0 13.968 0.084 13.992 ;
    END
  END in_epoch[127]
  PIN in_epoch[12]
    DIRECTION INPUT ;
    USE SIGNAL ;
    PORT
      LAYER M4 ;
        RECT  0 6 0.084 6.024 ;
    END
  END in_epoch[12]
  PIN in_epoch[13]
    DIRECTION INPUT ;
    USE SIGNAL ;
    PORT
      LAYER M4 ;
        RECT  0 6.096 0.084 6.12 ;
    END
  END in_epoch[13]
  PIN in_epoch[14]
    DIRECTION INPUT ;
    USE SIGNAL ;
    PORT
      LAYER M4 ;
        RECT  0 6.192 0.084 6.216 ;
    END
  END in_epoch[14]
  PIN in_epoch[15]
    DIRECTION INPUT ;
    USE SIGNAL ;
    PORT
      LAYER M4 ;
        RECT  0 6.288 0.084 6.312 ;
    END
  END in_epoch[15]
  PIN in_epoch[16]
    DIRECTION INPUT ;
    USE SIGNAL ;
    PORT
      LAYER M4 ;
        RECT  0 6.384 0.084 6.408 ;
    END
  END in_epoch[16]
  PIN in_epoch[17]
    DIRECTION INPUT ;
    USE SIGNAL ;
    PORT
      LAYER M4 ;
        RECT  0 6.48 0.084 6.504 ;
    END
  END in_epoch[17]
  PIN in_epoch[18]
    DIRECTION INPUT ;
    USE SIGNAL ;
    PORT
      LAYER M4 ;
        RECT  0 6.576 0.084 6.6 ;
    END
  END in_epoch[18]
  PIN in_epoch[19]
    DIRECTION INPUT ;
    USE SIGNAL ;
    PORT
      LAYER M4 ;
        RECT  0 6.672 0.084 6.696 ;
    END
  END in_epoch[19]
  PIN in_epoch[1]
    DIRECTION INPUT ;
    USE SIGNAL ;
    PORT
      LAYER M4 ;
        RECT  0 4.944 0.084 4.968 ;
    END
  END in_epoch[1]
  PIN in_epoch[20]
    DIRECTION INPUT ;
    USE SIGNAL ;
    PORT
      LAYER M4 ;
        RECT  0 6.768 0.084 6.792 ;
    END
  END in_epoch[20]
  PIN in_epoch[21]
    DIRECTION INPUT ;
    USE SIGNAL ;
    PORT
      LAYER M4 ;
        RECT  0 6.864 0.084 6.888 ;
    END
  END in_epoch[21]
  PIN in_epoch[22]
    DIRECTION INPUT ;
    USE SIGNAL ;
    PORT
      LAYER M4 ;
        RECT  0 6.96 0.084 6.984 ;
    END
  END in_epoch[22]
  PIN in_epoch[23]
    DIRECTION INPUT ;
    USE SIGNAL ;
    PORT
      LAYER M4 ;
        RECT  0 7.056 0.084 7.08 ;
    END
  END in_epoch[23]
  PIN in_epoch[24]
    DIRECTION INPUT ;
    USE SIGNAL ;
    PORT
      LAYER M4 ;
        RECT  0 7.152 0.084 7.176 ;
    END
  END in_epoch[24]
  PIN in_epoch[25]
    DIRECTION INPUT ;
    USE SIGNAL ;
    PORT
      LAYER M4 ;
        RECT  0 7.248 0.084 7.272 ;
    END
  END in_epoch[25]
  PIN in_epoch[26]
    DIRECTION INPUT ;
    USE SIGNAL ;
    PORT
      LAYER M4 ;
        RECT  0 7.344 0.084 7.368 ;
    END
  END in_epoch[26]
  PIN in_epoch[27]
    DIRECTION INPUT ;
    USE SIGNAL ;
    PORT
      LAYER M4 ;
        RECT  0 7.44 0.084 7.464 ;
    END
  END in_epoch[27]
  PIN in_epoch[28]
    DIRECTION INPUT ;
    USE SIGNAL ;
    PORT
      LAYER M4 ;
        RECT  0 7.536 0.084 7.56 ;
    END
  END in_epoch[28]
  PIN in_epoch[29]
    DIRECTION INPUT ;
    USE SIGNAL ;
    PORT
      LAYER M4 ;
        RECT  0 7.632 0.084 7.656 ;
    END
  END in_epoch[29]
  PIN in_epoch[2]
    DIRECTION INPUT ;
    USE SIGNAL ;
    PORT
      LAYER M4 ;
        RECT  0 5.04 0.084 5.064 ;
    END
  END in_epoch[2]
  PIN in_epoch[30]
    DIRECTION INPUT ;
    USE SIGNAL ;
    PORT
      LAYER M4 ;
        RECT  0 7.728 0.084 7.752 ;
    END
  END in_epoch[30]
  PIN in_epoch[31]
    DIRECTION INPUT ;
    USE SIGNAL ;
    PORT
      LAYER M4 ;
        RECT  0 7.824 0.084 7.848 ;
    END
  END in_epoch[31]
  PIN in_epoch[32]
    DIRECTION INPUT ;
    USE SIGNAL ;
    PORT
      LAYER M4 ;
        RECT  0 14.064 0.084 14.088 ;
    END
  END in_epoch[32]
  PIN in_epoch[33]
    DIRECTION INPUT ;
    USE SIGNAL ;
    PORT
      LAYER M4 ;
        RECT  0 14.16 0.084 14.184 ;
    END
  END in_epoch[33]
  PIN in_epoch[34]
    DIRECTION INPUT ;
    USE SIGNAL ;
    PORT
      LAYER M4 ;
        RECT  0 14.256 0.084 14.28 ;
    END
  END in_epoch[34]
  PIN in_epoch[35]
    DIRECTION INPUT ;
    USE SIGNAL ;
    PORT
      LAYER M4 ;
        RECT  0 14.352 0.084 14.376 ;
    END
  END in_epoch[35]
  PIN in_epoch[36]
    DIRECTION INPUT ;
    USE SIGNAL ;
    PORT
      LAYER M4 ;
        RECT  0 14.448 0.084 14.472 ;
    END
  END in_epoch[36]
  PIN in_epoch[37]
    DIRECTION INPUT ;
    USE SIGNAL ;
    PORT
      LAYER M4 ;
        RECT  0 14.544 0.084 14.568 ;
    END
  END in_epoch[37]
  PIN in_epoch[38]
    DIRECTION INPUT ;
    USE SIGNAL ;
    PORT
      LAYER M4 ;
        RECT  0 14.64 0.084 14.664 ;
    END
  END in_epoch[38]
  PIN in_epoch[39]
    DIRECTION INPUT ;
    USE SIGNAL ;
    PORT
      LAYER M4 ;
        RECT  0 14.736 0.084 14.76 ;
    END
  END in_epoch[39]
  PIN in_epoch[3]
    DIRECTION INPUT ;
    USE SIGNAL ;
    PORT
      LAYER M4 ;
        RECT  0 5.136 0.084 5.16 ;
    END
  END in_epoch[3]
  PIN in_epoch[40]
    DIRECTION INPUT ;
    USE SIGNAL ;
    PORT
      LAYER M4 ;
        RECT  0 14.832 0.084 14.856 ;
    END
  END in_epoch[40]
  PIN in_epoch[41]
    DIRECTION INPUT ;
    USE SIGNAL ;
    PORT
      LAYER M4 ;
        RECT  0 14.928 0.084 14.952 ;
    END
  END in_epoch[41]
  PIN in_epoch[42]
    DIRECTION INPUT ;
    USE SIGNAL ;
    PORT
      LAYER M4 ;
        RECT  0 15.024 0.084 15.048 ;
    END
  END in_epoch[42]
  PIN in_epoch[43]
    DIRECTION INPUT ;
    USE SIGNAL ;
    PORT
      LAYER M4 ;
        RECT  0 15.12 0.084 15.144 ;
    END
  END in_epoch[43]
  PIN in_epoch[44]
    DIRECTION INPUT ;
    USE SIGNAL ;
    PORT
      LAYER M4 ;
        RECT  0 15.216 0.084 15.24 ;
    END
  END in_epoch[44]
  PIN in_epoch[45]
    DIRECTION INPUT ;
    USE SIGNAL ;
    PORT
      LAYER M4 ;
        RECT  0 15.312 0.084 15.336 ;
    END
  END in_epoch[45]
  PIN in_epoch[46]
    DIRECTION INPUT ;
    USE SIGNAL ;
    PORT
      LAYER M4 ;
        RECT  0 15.408 0.084 15.432 ;
    END
  END in_epoch[46]
  PIN in_epoch[47]
    DIRECTION INPUT ;
    USE SIGNAL ;
    PORT
      LAYER M4 ;
        RECT  0 15.504 0.084 15.528 ;
    END
  END in_epoch[47]
  PIN in_epoch[48]
    DIRECTION INPUT ;
    USE SIGNAL ;
    PORT
      LAYER M4 ;
        RECT  0 15.6 0.084 15.624 ;
    END
  END in_epoch[48]
  PIN in_epoch[49]
    DIRECTION INPUT ;
    USE SIGNAL ;
    PORT
      LAYER M4 ;
        RECT  0 15.696 0.084 15.72 ;
    END
  END in_epoch[49]
  PIN in_epoch[4]
    DIRECTION INPUT ;
    USE SIGNAL ;
    PORT
      LAYER M4 ;
        RECT  0 5.232 0.084 5.256 ;
    END
  END in_epoch[4]
  PIN in_epoch[50]
    DIRECTION INPUT ;
    USE SIGNAL ;
    PORT
      LAYER M4 ;
        RECT  0 15.792 0.084 15.816 ;
    END
  END in_epoch[50]
  PIN in_epoch[51]
    DIRECTION INPUT ;
    USE SIGNAL ;
    PORT
      LAYER M4 ;
        RECT  0 15.888 0.084 15.912 ;
    END
  END in_epoch[51]
  PIN in_epoch[52]
    DIRECTION INPUT ;
    USE SIGNAL ;
    PORT
      LAYER M4 ;
        RECT  0 15.984 0.084 16.008 ;
    END
  END in_epoch[52]
  PIN in_epoch[53]
    DIRECTION INPUT ;
    USE SIGNAL ;
    PORT
      LAYER M4 ;
        RECT  0 16.08 0.084 16.104 ;
    END
  END in_epoch[53]
  PIN in_epoch[54]
    DIRECTION INPUT ;
    USE SIGNAL ;
    PORT
      LAYER M4 ;
        RECT  0 16.176 0.084 16.2 ;
    END
  END in_epoch[54]
  PIN in_epoch[55]
    DIRECTION INPUT ;
    USE SIGNAL ;
    PORT
      LAYER M4 ;
        RECT  0 16.272 0.084 16.296 ;
    END
  END in_epoch[55]
  PIN in_epoch[56]
    DIRECTION INPUT ;
    USE SIGNAL ;
    PORT
      LAYER M4 ;
        RECT  0 16.368 0.084 16.392 ;
    END
  END in_epoch[56]
  PIN in_epoch[57]
    DIRECTION INPUT ;
    USE SIGNAL ;
    PORT
      LAYER M4 ;
        RECT  0 16.464 0.084 16.488 ;
    END
  END in_epoch[57]
  PIN in_epoch[58]
    DIRECTION INPUT ;
    USE SIGNAL ;
    PORT
      LAYER M4 ;
        RECT  0 16.56 0.084 16.584 ;
    END
  END in_epoch[58]
  PIN in_epoch[59]
    DIRECTION INPUT ;
    USE SIGNAL ;
    PORT
      LAYER M4 ;
        RECT  0 16.656 0.084 16.68 ;
    END
  END in_epoch[59]
  PIN in_epoch[5]
    DIRECTION INPUT ;
    USE SIGNAL ;
    PORT
      LAYER M4 ;
        RECT  0 5.328 0.084 5.352 ;
    END
  END in_epoch[5]
  PIN in_epoch[60]
    DIRECTION INPUT ;
    USE SIGNAL ;
    PORT
      LAYER M4 ;
        RECT  0 16.752 0.084 16.776 ;
    END
  END in_epoch[60]
  PIN in_epoch[61]
    DIRECTION INPUT ;
    USE SIGNAL ;
    PORT
      LAYER M4 ;
        RECT  0 16.848 0.084 16.872 ;
    END
  END in_epoch[61]
  PIN in_epoch[62]
    DIRECTION INPUT ;
    USE SIGNAL ;
    PORT
      LAYER M4 ;
        RECT  0 16.944 0.084 16.968 ;
    END
  END in_epoch[62]
  PIN in_epoch[63]
    DIRECTION INPUT ;
    USE SIGNAL ;
    PORT
      LAYER M4 ;
        RECT  0 17.04 0.084 17.064 ;
    END
  END in_epoch[63]
  PIN in_epoch[64]
    DIRECTION INPUT ;
    USE SIGNAL ;
    PORT
      LAYER M4 ;
        RECT  0 7.92 0.084 7.944 ;
    END
  END in_epoch[64]
  PIN in_epoch[65]
    DIRECTION INPUT ;
    USE SIGNAL ;
    PORT
      LAYER M4 ;
        RECT  0 8.016 0.084 8.04 ;
    END
  END in_epoch[65]
  PIN in_epoch[66]
    DIRECTION INPUT ;
    USE SIGNAL ;
    PORT
      LAYER M4 ;
        RECT  0 8.112 0.084 8.136 ;
    END
  END in_epoch[66]
  PIN in_epoch[67]
    DIRECTION INPUT ;
    USE SIGNAL ;
    PORT
      LAYER M4 ;
        RECT  0 8.208 0.084 8.232 ;
    END
  END in_epoch[67]
  PIN in_epoch[68]
    DIRECTION INPUT ;
    USE SIGNAL ;
    PORT
      LAYER M4 ;
        RECT  0 8.304 0.084 8.328 ;
    END
  END in_epoch[68]
  PIN in_epoch[69]
    DIRECTION INPUT ;
    USE SIGNAL ;
    PORT
      LAYER M4 ;
        RECT  0 8.4 0.084 8.424 ;
    END
  END in_epoch[69]
  PIN in_epoch[6]
    DIRECTION INPUT ;
    USE SIGNAL ;
    PORT
      LAYER M4 ;
        RECT  0 5.424 0.084 5.448 ;
    END
  END in_epoch[6]
  PIN in_epoch[70]
    DIRECTION INPUT ;
    USE SIGNAL ;
    PORT
      LAYER M4 ;
        RECT  0 8.496 0.084 8.52 ;
    END
  END in_epoch[70]
  PIN in_epoch[71]
    DIRECTION INPUT ;
    USE SIGNAL ;
    PORT
      LAYER M4 ;
        RECT  0 8.592 0.084 8.616 ;
    END
  END in_epoch[71]
  PIN in_epoch[72]
    DIRECTION INPUT ;
    USE SIGNAL ;
    PORT
      LAYER M4 ;
        RECT  0 8.688 0.084 8.712 ;
    END
  END in_epoch[72]
  PIN in_epoch[73]
    DIRECTION INPUT ;
    USE SIGNAL ;
    PORT
      LAYER M4 ;
        RECT  0 8.784 0.084 8.808 ;
    END
  END in_epoch[73]
  PIN in_epoch[74]
    DIRECTION INPUT ;
    USE SIGNAL ;
    PORT
      LAYER M4 ;
        RECT  0 8.88 0.084 8.904 ;
    END
  END in_epoch[74]
  PIN in_epoch[75]
    DIRECTION INPUT ;
    USE SIGNAL ;
    PORT
      LAYER M4 ;
        RECT  0 8.976 0.084 9 ;
    END
  END in_epoch[75]
  PIN in_epoch[76]
    DIRECTION INPUT ;
    USE SIGNAL ;
    PORT
      LAYER M4 ;
        RECT  0 9.072 0.084 9.096 ;
    END
  END in_epoch[76]
  PIN in_epoch[77]
    DIRECTION INPUT ;
    USE SIGNAL ;
    PORT
      LAYER M4 ;
        RECT  0 9.168 0.084 9.192 ;
    END
  END in_epoch[77]
  PIN in_epoch[78]
    DIRECTION INPUT ;
    USE SIGNAL ;
    PORT
      LAYER M4 ;
        RECT  0 9.264 0.084 9.288 ;
    END
  END in_epoch[78]
  PIN in_epoch[79]
    DIRECTION INPUT ;
    USE SIGNAL ;
    PORT
      LAYER M4 ;
        RECT  0 9.36 0.084 9.384 ;
    END
  END in_epoch[79]
  PIN in_epoch[7]
    DIRECTION INPUT ;
    USE SIGNAL ;
    PORT
      LAYER M4 ;
        RECT  0 5.52 0.084 5.544 ;
    END
  END in_epoch[7]
  PIN in_epoch[80]
    DIRECTION INPUT ;
    USE SIGNAL ;
    PORT
      LAYER M4 ;
        RECT  0 9.456 0.084 9.48 ;
    END
  END in_epoch[80]
  PIN in_epoch[81]
    DIRECTION INPUT ;
    USE SIGNAL ;
    PORT
      LAYER M4 ;
        RECT  0 9.552 0.084 9.576 ;
    END
  END in_epoch[81]
  PIN in_epoch[82]
    DIRECTION INPUT ;
    USE SIGNAL ;
    PORT
      LAYER M4 ;
        RECT  0 9.648 0.084 9.672 ;
    END
  END in_epoch[82]
  PIN in_epoch[83]
    DIRECTION INPUT ;
    USE SIGNAL ;
    PORT
      LAYER M4 ;
        RECT  0 9.744 0.084 9.768 ;
    END
  END in_epoch[83]
  PIN in_epoch[84]
    DIRECTION INPUT ;
    USE SIGNAL ;
    PORT
      LAYER M4 ;
        RECT  0 9.84 0.084 9.864 ;
    END
  END in_epoch[84]
  PIN in_epoch[85]
    DIRECTION INPUT ;
    USE SIGNAL ;
    PORT
      LAYER M4 ;
        RECT  0 9.936 0.084 9.96 ;
    END
  END in_epoch[85]
  PIN in_epoch[86]
    DIRECTION INPUT ;
    USE SIGNAL ;
    PORT
      LAYER M4 ;
        RECT  0 10.032 0.084 10.056 ;
    END
  END in_epoch[86]
  PIN in_epoch[87]
    DIRECTION INPUT ;
    USE SIGNAL ;
    PORT
      LAYER M4 ;
        RECT  0 10.128 0.084 10.152 ;
    END
  END in_epoch[87]
  PIN in_epoch[88]
    DIRECTION INPUT ;
    USE SIGNAL ;
    PORT
      LAYER M4 ;
        RECT  0 10.224 0.084 10.248 ;
    END
  END in_epoch[88]
  PIN in_epoch[89]
    DIRECTION INPUT ;
    USE SIGNAL ;
    PORT
      LAYER M4 ;
        RECT  0 10.32 0.084 10.344 ;
    END
  END in_epoch[89]
  PIN in_epoch[8]
    DIRECTION INPUT ;
    USE SIGNAL ;
    PORT
      LAYER M4 ;
        RECT  0 5.616 0.084 5.64 ;
    END
  END in_epoch[8]
  PIN in_epoch[90]
    DIRECTION INPUT ;
    USE SIGNAL ;
    PORT
      LAYER M4 ;
        RECT  0 10.416 0.084 10.44 ;
    END
  END in_epoch[90]
  PIN in_epoch[91]
    DIRECTION INPUT ;
    USE SIGNAL ;
    PORT
      LAYER M4 ;
        RECT  0 10.512 0.084 10.536 ;
    END
  END in_epoch[91]
  PIN in_epoch[92]
    DIRECTION INPUT ;
    USE SIGNAL ;
    PORT
      LAYER M4 ;
        RECT  0 10.608 0.084 10.632 ;
    END
  END in_epoch[92]
  PIN in_epoch[93]
    DIRECTION INPUT ;
    USE SIGNAL ;
    PORT
      LAYER M4 ;
        RECT  0 10.704 0.084 10.728 ;
    END
  END in_epoch[93]
  PIN in_epoch[94]
    DIRECTION INPUT ;
    USE SIGNAL ;
    PORT
      LAYER M4 ;
        RECT  0 10.8 0.084 10.824 ;
    END
  END in_epoch[94]
  PIN in_epoch[95]
    DIRECTION INPUT ;
    USE SIGNAL ;
    PORT
      LAYER M4 ;
        RECT  0 10.896 0.084 10.92 ;
    END
  END in_epoch[95]
  PIN in_epoch[96]
    DIRECTION INPUT ;
    USE SIGNAL ;
    PORT
      LAYER M4 ;
        RECT  0 10.992 0.084 11.016 ;
    END
  END in_epoch[96]
  PIN in_epoch[97]
    DIRECTION INPUT ;
    USE SIGNAL ;
    PORT
      LAYER M4 ;
        RECT  0 11.088 0.084 11.112 ;
    END
  END in_epoch[97]
  PIN in_epoch[98]
    DIRECTION INPUT ;
    USE SIGNAL ;
    PORT
      LAYER M4 ;
        RECT  0 11.184 0.084 11.208 ;
    END
  END in_epoch[98]
  PIN in_epoch[99]
    DIRECTION INPUT ;
    USE SIGNAL ;
    PORT
      LAYER M4 ;
        RECT  0 11.28 0.084 11.304 ;
    END
  END in_epoch[99]
  PIN in_epoch[9]
    DIRECTION INPUT ;
    USE SIGNAL ;
    PORT
      LAYER M4 ;
        RECT  0 5.712 0.084 5.736 ;
    END
  END in_epoch[9]
  PIN in_t[0]
    DIRECTION INPUT ;
    USE SIGNAL ;
    PORT
      LAYER M4 ;
        RECT  0 20.208 0.084 20.232 ;
    END
  END in_t[0]
  PIN in_t[100]
    DIRECTION INPUT ;
    USE SIGNAL ;
    PORT
      LAYER M4 ;
        RECT  0 24.432 0.084 24.456 ;
    END
  END in_t[100]
  PIN in_t[101]
    DIRECTION INPUT ;
    USE SIGNAL ;
    PORT
      LAYER M4 ;
        RECT  0 24.528 0.084 24.552 ;
    END
  END in_t[101]
  PIN in_t[102]
    DIRECTION INPUT ;
    USE SIGNAL ;
    PORT
      LAYER M4 ;
        RECT  0 24.624 0.084 24.648 ;
    END
  END in_t[102]
  PIN in_t[103]
    DIRECTION INPUT ;
    USE SIGNAL ;
    PORT
      LAYER M4 ;
        RECT  0 24.72 0.084 24.744 ;
    END
  END in_t[103]
  PIN in_t[104]
    DIRECTION INPUT ;
    USE SIGNAL ;
    PORT
      LAYER M4 ;
        RECT  0 24.816 0.084 24.84 ;
    END
  END in_t[104]
  PIN in_t[105]
    DIRECTION INPUT ;
    USE SIGNAL ;
    PORT
      LAYER M4 ;
        RECT  0 24.912 0.084 24.936 ;
    END
  END in_t[105]
  PIN in_t[106]
    DIRECTION INPUT ;
    USE SIGNAL ;
    PORT
      LAYER M4 ;
        RECT  0 25.008 0.084 25.032 ;
    END
  END in_t[106]
  PIN in_t[107]
    DIRECTION INPUT ;
    USE SIGNAL ;
    PORT
      LAYER M4 ;
        RECT  0 25.104 0.084 25.128 ;
    END
  END in_t[107]
  PIN in_t[108]
    DIRECTION INPUT ;
    USE SIGNAL ;
    PORT
      LAYER M4 ;
        RECT  0 25.2 0.084 25.224 ;
    END
  END in_t[108]
  PIN in_t[109]
    DIRECTION INPUT ;
    USE SIGNAL ;
    PORT
      LAYER M4 ;
        RECT  0 25.296 0.084 25.32 ;
    END
  END in_t[109]
  PIN in_t[10]
    DIRECTION INPUT ;
    USE SIGNAL ;
    PORT
      LAYER M4 ;
        RECT  0 21.168 0.084 21.192 ;
    END
  END in_t[10]
  PIN in_t[110]
    DIRECTION INPUT ;
    USE SIGNAL ;
    PORT
      LAYER M4 ;
        RECT  0 25.392 0.084 25.416 ;
    END
  END in_t[110]
  PIN in_t[111]
    DIRECTION INPUT ;
    USE SIGNAL ;
    PORT
      LAYER M4 ;
        RECT  0 25.488 0.084 25.512 ;
    END
  END in_t[111]
  PIN in_t[11]
    DIRECTION INPUT ;
    USE SIGNAL ;
    PORT
      LAYER M4 ;
        RECT  0 21.264 0.084 21.288 ;
    END
  END in_t[11]
  PIN in_t[12]
    DIRECTION INPUT ;
    USE SIGNAL ;
    PORT
      LAYER M4 ;
        RECT  0 21.36 0.084 21.384 ;
    END
  END in_t[12]
  PIN in_t[13]
    DIRECTION INPUT ;
    USE SIGNAL ;
    PORT
      LAYER M4 ;
        RECT  0 21.456 0.084 21.48 ;
    END
  END in_t[13]
  PIN in_t[14]
    DIRECTION INPUT ;
    USE SIGNAL ;
    PORT
      LAYER M4 ;
        RECT  0 21.552 0.084 21.576 ;
    END
  END in_t[14]
  PIN in_t[15]
    DIRECTION INPUT ;
    USE SIGNAL ;
    PORT
      LAYER M4 ;
        RECT  0 21.648 0.084 21.672 ;
    END
  END in_t[15]
  PIN in_t[16]
    DIRECTION INPUT ;
    USE SIGNAL ;
    PORT
      LAYER M4 ;
        RECT  0 21.744 0.084 21.768 ;
    END
  END in_t[16]
  PIN in_t[17]
    DIRECTION INPUT ;
    USE SIGNAL ;
    PORT
      LAYER M4 ;
        RECT  0 21.84 0.084 21.864 ;
    END
  END in_t[17]
  PIN in_t[18]
    DIRECTION INPUT ;
    USE SIGNAL ;
    PORT
      LAYER M4 ;
        RECT  0 21.936 0.084 21.96 ;
    END
  END in_t[18]
  PIN in_t[19]
    DIRECTION INPUT ;
    USE SIGNAL ;
    PORT
      LAYER M4 ;
        RECT  0 22.032 0.084 22.056 ;
    END
  END in_t[19]
  PIN in_t[1]
    DIRECTION INPUT ;
    USE SIGNAL ;
    PORT
      LAYER M4 ;
        RECT  0 20.304 0.084 20.328 ;
    END
  END in_t[1]
  PIN in_t[20]
    DIRECTION INPUT ;
    USE SIGNAL ;
    PORT
      LAYER M4 ;
        RECT  0 22.128 0.084 22.152 ;
    END
  END in_t[20]
  PIN in_t[21]
    DIRECTION INPUT ;
    USE SIGNAL ;
    PORT
      LAYER M4 ;
        RECT  0 22.224 0.084 22.248 ;
    END
  END in_t[21]
  PIN in_t[22]
    DIRECTION INPUT ;
    USE SIGNAL ;
    PORT
      LAYER M4 ;
        RECT  0 22.32 0.084 22.344 ;
    END
  END in_t[22]
  PIN in_t[23]
    DIRECTION INPUT ;
    USE SIGNAL ;
    PORT
      LAYER M4 ;
        RECT  0 22.416 0.084 22.44 ;
    END
  END in_t[23]
  PIN in_t[24]
    DIRECTION INPUT ;
    USE SIGNAL ;
    PORT
      LAYER M4 ;
        RECT  0 22.512 0.084 22.536 ;
    END
  END in_t[24]
  PIN in_t[25]
    DIRECTION INPUT ;
    USE SIGNAL ;
    PORT
      LAYER M4 ;
        RECT  0 22.608 0.084 22.632 ;
    END
  END in_t[25]
  PIN in_t[26]
    DIRECTION INPUT ;
    USE SIGNAL ;
    PORT
      LAYER M4 ;
        RECT  0 22.704 0.084 22.728 ;
    END
  END in_t[26]
  PIN in_t[27]
    DIRECTION INPUT ;
    USE SIGNAL ;
    PORT
      LAYER M4 ;
        RECT  0 22.8 0.084 22.824 ;
    END
  END in_t[27]
  PIN in_t[28]
    DIRECTION INPUT ;
    USE SIGNAL ;
    PORT
      LAYER M4 ;
        RECT  0 22.896 0.084 22.92 ;
    END
  END in_t[28]
  PIN in_t[29]
    DIRECTION INPUT ;
    USE SIGNAL ;
    PORT
      LAYER M4 ;
        RECT  0 22.992 0.084 23.016 ;
    END
  END in_t[29]
  PIN in_t[2]
    DIRECTION INPUT ;
    USE SIGNAL ;
    PORT
      LAYER M4 ;
        RECT  0 20.4 0.084 20.424 ;
    END
  END in_t[2]
  PIN in_t[30]
    DIRECTION INPUT ;
    USE SIGNAL ;
    PORT
      LAYER M4 ;
        RECT  0 23.088 0.084 23.112 ;
    END
  END in_t[30]
  PIN in_t[31]
    DIRECTION INPUT ;
    USE SIGNAL ;
    PORT
      LAYER M4 ;
        RECT  0 23.184 0.084 23.208 ;
    END
  END in_t[31]
  PIN in_t[32]
    DIRECTION INPUT ;
    USE SIGNAL ;
    PORT
      LAYER M4 ;
        RECT  0 17.136 0.084 17.16 ;
    END
  END in_t[32]
  PIN in_t[33]
    DIRECTION INPUT ;
    USE SIGNAL ;
    PORT
      LAYER M4 ;
        RECT  0 17.232 0.084 17.256 ;
    END
  END in_t[33]
  PIN in_t[34]
    DIRECTION INPUT ;
    USE SIGNAL ;
    PORT
      LAYER M4 ;
        RECT  0 17.328 0.084 17.352 ;
    END
  END in_t[34]
  PIN in_t[35]
    DIRECTION INPUT ;
    USE SIGNAL ;
    PORT
      LAYER M4 ;
        RECT  0 17.424 0.084 17.448 ;
    END
  END in_t[35]
  PIN in_t[36]
    DIRECTION INPUT ;
    USE SIGNAL ;
    PORT
      LAYER M4 ;
        RECT  0 17.52 0.084 17.544 ;
    END
  END in_t[36]
  PIN in_t[37]
    DIRECTION INPUT ;
    USE SIGNAL ;
    PORT
      LAYER M4 ;
        RECT  0 17.616 0.084 17.64 ;
    END
  END in_t[37]
  PIN in_t[38]
    DIRECTION INPUT ;
    USE SIGNAL ;
    PORT
      LAYER M4 ;
        RECT  0 17.712 0.084 17.736 ;
    END
  END in_t[38]
  PIN in_t[39]
    DIRECTION INPUT ;
    USE SIGNAL ;
    PORT
      LAYER M4 ;
        RECT  0 17.808 0.084 17.832 ;
    END
  END in_t[39]
  PIN in_t[3]
    DIRECTION INPUT ;
    USE SIGNAL ;
    PORT
      LAYER M4 ;
        RECT  0 20.496 0.084 20.52 ;
    END
  END in_t[3]
  PIN in_t[40]
    DIRECTION INPUT ;
    USE SIGNAL ;
    PORT
      LAYER M4 ;
        RECT  0 17.904 0.084 17.928 ;
    END
  END in_t[40]
  PIN in_t[41]
    DIRECTION INPUT ;
    USE SIGNAL ;
    PORT
      LAYER M4 ;
        RECT  0 18 0.084 18.024 ;
    END
  END in_t[41]
  PIN in_t[42]
    DIRECTION INPUT ;
    USE SIGNAL ;
    PORT
      LAYER M4 ;
        RECT  0 18.096 0.084 18.12 ;
    END
  END in_t[42]
  PIN in_t[43]
    DIRECTION INPUT ;
    USE SIGNAL ;
    PORT
      LAYER M4 ;
        RECT  0 18.192 0.084 18.216 ;
    END
  END in_t[43]
  PIN in_t[44]
    DIRECTION INPUT ;
    USE SIGNAL ;
    PORT
      LAYER M4 ;
        RECT  0 18.288 0.084 18.312 ;
    END
  END in_t[44]
  PIN in_t[45]
    DIRECTION INPUT ;
    USE SIGNAL ;
    PORT
      LAYER M4 ;
        RECT  0 18.384 0.084 18.408 ;
    END
  END in_t[45]
  PIN in_t[46]
    DIRECTION INPUT ;
    USE SIGNAL ;
    PORT
      LAYER M4 ;
        RECT  0 18.48 0.084 18.504 ;
    END
  END in_t[46]
  PIN in_t[47]
    DIRECTION INPUT ;
    USE SIGNAL ;
    PORT
      LAYER M4 ;
        RECT  0 18.576 0.084 18.6 ;
    END
  END in_t[47]
  PIN in_t[48]
    DIRECTION INPUT ;
    USE SIGNAL ;
    PORT
      LAYER M4 ;
        RECT  0 18.672 0.084 18.696 ;
    END
  END in_t[48]
  PIN in_t[49]
    DIRECTION INPUT ;
    USE SIGNAL ;
    PORT
      LAYER M4 ;
        RECT  0 18.768 0.084 18.792 ;
    END
  END in_t[49]
  PIN in_t[4]
    DIRECTION INPUT ;
    USE SIGNAL ;
    PORT
      LAYER M4 ;
        RECT  0 20.592 0.084 20.616 ;
    END
  END in_t[4]
  PIN in_t[50]
    DIRECTION INPUT ;
    USE SIGNAL ;
    PORT
      LAYER M4 ;
        RECT  0 18.864 0.084 18.888 ;
    END
  END in_t[50]
  PIN in_t[51]
    DIRECTION INPUT ;
    USE SIGNAL ;
    PORT
      LAYER M4 ;
        RECT  0 18.96 0.084 18.984 ;
    END
  END in_t[51]
  PIN in_t[52]
    DIRECTION INPUT ;
    USE SIGNAL ;
    PORT
      LAYER M4 ;
        RECT  0 19.056 0.084 19.08 ;
    END
  END in_t[52]
  PIN in_t[53]
    DIRECTION INPUT ;
    USE SIGNAL ;
    PORT
      LAYER M4 ;
        RECT  0 19.152 0.084 19.176 ;
    END
  END in_t[53]
  PIN in_t[54]
    DIRECTION INPUT ;
    USE SIGNAL ;
    PORT
      LAYER M4 ;
        RECT  0 19.248 0.084 19.272 ;
    END
  END in_t[54]
  PIN in_t[55]
    DIRECTION INPUT ;
    USE SIGNAL ;
    PORT
      LAYER M4 ;
        RECT  0 19.344 0.084 19.368 ;
    END
  END in_t[55]
  PIN in_t[56]
    DIRECTION INPUT ;
    USE SIGNAL ;
    PORT
      LAYER M4 ;
        RECT  0 19.44 0.084 19.464 ;
    END
  END in_t[56]
  PIN in_t[57]
    DIRECTION INPUT ;
    USE SIGNAL ;
    PORT
      LAYER M4 ;
        RECT  0 19.536 0.084 19.56 ;
    END
  END in_t[57]
  PIN in_t[58]
    DIRECTION INPUT ;
    USE SIGNAL ;
    PORT
      LAYER M4 ;
        RECT  0 19.632 0.084 19.656 ;
    END
  END in_t[58]
  PIN in_t[59]
    DIRECTION INPUT ;
    USE SIGNAL ;
    PORT
      LAYER M4 ;
        RECT  0 19.728 0.084 19.752 ;
    END
  END in_t[59]
  PIN in_t[5]
    DIRECTION INPUT ;
    USE SIGNAL ;
    PORT
      LAYER M4 ;
        RECT  0 20.688 0.084 20.712 ;
    END
  END in_t[5]
  PIN in_t[60]
    DIRECTION INPUT ;
    USE SIGNAL ;
    PORT
      LAYER M4 ;
        RECT  0 19.824 0.084 19.848 ;
    END
  END in_t[60]
  PIN in_t[61]
    DIRECTION INPUT ;
    USE SIGNAL ;
    PORT
      LAYER M4 ;
        RECT  0 19.92 0.084 19.944 ;
    END
  END in_t[61]
  PIN in_t[62]
    DIRECTION INPUT ;
    USE SIGNAL ;
    PORT
      LAYER M4 ;
        RECT  0 20.016 0.084 20.04 ;
    END
  END in_t[62]
  PIN in_t[63]
    DIRECTION INPUT ;
    USE SIGNAL ;
    PORT
      LAYER M4 ;
        RECT  0 20.112 0.084 20.136 ;
    END
  END in_t[63]
  PIN in_t[64]
    DIRECTION INPUT ;
    USE SIGNAL ;
    PORT
      LAYER M4 ;
        RECT  0 1.008 0.084 1.032 ;
    END
  END in_t[64]
  PIN in_t[65]
    DIRECTION INPUT ;
    USE SIGNAL ;
    PORT
      LAYER M4 ;
        RECT  0 1.104 0.084 1.128 ;
    END
  END in_t[65]
  PIN in_t[66]
    DIRECTION INPUT ;
    USE SIGNAL ;
    PORT
      LAYER M4 ;
        RECT  0 1.2 0.084 1.224 ;
    END
  END in_t[66]
  PIN in_t[67]
    DIRECTION INPUT ;
    USE SIGNAL ;
    PORT
      LAYER M4 ;
        RECT  0 1.296 0.084 1.32 ;
    END
  END in_t[67]
  PIN in_t[68]
    DIRECTION INPUT ;
    USE SIGNAL ;
    PORT
      LAYER M4 ;
        RECT  0 1.392 0.084 1.416 ;
    END
  END in_t[68]
  PIN in_t[69]
    DIRECTION INPUT ;
    USE SIGNAL ;
    PORT
      LAYER M4 ;
        RECT  0 1.488 0.084 1.512 ;
    END
  END in_t[69]
  PIN in_t[6]
    DIRECTION INPUT ;
    USE SIGNAL ;
    PORT
      LAYER M4 ;
        RECT  0 20.784 0.084 20.808 ;
    END
  END in_t[6]
  PIN in_t[70]
    DIRECTION INPUT ;
    USE SIGNAL ;
    PORT
      LAYER M4 ;
        RECT  0 1.584 0.084 1.608 ;
    END
  END in_t[70]
  PIN in_t[71]
    DIRECTION INPUT ;
    USE SIGNAL ;
    PORT
      LAYER M4 ;
        RECT  0 1.68 0.084 1.704 ;
    END
  END in_t[71]
  PIN in_t[72]
    DIRECTION INPUT ;
    USE SIGNAL ;
    PORT
      LAYER M4 ;
        RECT  0 1.776 0.084 1.8 ;
    END
  END in_t[72]
  PIN in_t[73]
    DIRECTION INPUT ;
    USE SIGNAL ;
    PORT
      LAYER M4 ;
        RECT  0 1.872 0.084 1.896 ;
    END
  END in_t[73]
  PIN in_t[74]
    DIRECTION INPUT ;
    USE SIGNAL ;
    PORT
      LAYER M4 ;
        RECT  0 1.968 0.084 1.992 ;
    END
  END in_t[74]
  PIN in_t[75]
    DIRECTION INPUT ;
    USE SIGNAL ;
    PORT
      LAYER M4 ;
        RECT  0 2.064 0.084 2.088 ;
    END
  END in_t[75]
  PIN in_t[76]
    DIRECTION INPUT ;
    USE SIGNAL ;
    PORT
      LAYER M4 ;
        RECT  0 2.16 0.084 2.184 ;
    END
  END in_t[76]
  PIN in_t[77]
    DIRECTION INPUT ;
    USE SIGNAL ;
    PORT
      LAYER M4 ;
        RECT  0 2.256 0.084 2.28 ;
    END
  END in_t[77]
  PIN in_t[78]
    DIRECTION INPUT ;
    USE SIGNAL ;
    PORT
      LAYER M4 ;
        RECT  0 2.352 0.084 2.376 ;
    END
  END in_t[78]
  PIN in_t[79]
    DIRECTION INPUT ;
    USE SIGNAL ;
    PORT
      LAYER M4 ;
        RECT  0 2.448 0.084 2.472 ;
    END
  END in_t[79]
  PIN in_t[7]
    DIRECTION INPUT ;
    USE SIGNAL ;
    PORT
      LAYER M4 ;
        RECT  0 20.88 0.084 20.904 ;
    END
  END in_t[7]
  PIN in_t[80]
    DIRECTION INPUT ;
    USE SIGNAL ;
    PORT
      LAYER M4 ;
        RECT  0 2.544 0.084 2.568 ;
    END
  END in_t[80]
  PIN in_t[81]
    DIRECTION INPUT ;
    USE SIGNAL ;
    PORT
      LAYER M4 ;
        RECT  0 2.64 0.084 2.664 ;
    END
  END in_t[81]
  PIN in_t[82]
    DIRECTION INPUT ;
    USE SIGNAL ;
    PORT
      LAYER M4 ;
        RECT  0 2.736 0.084 2.76 ;
    END
  END in_t[82]
  PIN in_t[83]
    DIRECTION INPUT ;
    USE SIGNAL ;
    PORT
      LAYER M4 ;
        RECT  0 2.832 0.084 2.856 ;
    END
  END in_t[83]
  PIN in_t[84]
    DIRECTION INPUT ;
    USE SIGNAL ;
    PORT
      LAYER M4 ;
        RECT  0 2.928 0.084 2.952 ;
    END
  END in_t[84]
  PIN in_t[85]
    DIRECTION INPUT ;
    USE SIGNAL ;
    PORT
      LAYER M4 ;
        RECT  0 3.024 0.084 3.048 ;
    END
  END in_t[85]
  PIN in_t[86]
    DIRECTION INPUT ;
    USE SIGNAL ;
    PORT
      LAYER M4 ;
        RECT  0 3.12 0.084 3.144 ;
    END
  END in_t[86]
  PIN in_t[87]
    DIRECTION INPUT ;
    USE SIGNAL ;
    PORT
      LAYER M4 ;
        RECT  0 3.216 0.084 3.24 ;
    END
  END in_t[87]
  PIN in_t[88]
    DIRECTION INPUT ;
    USE SIGNAL ;
    PORT
      LAYER M4 ;
        RECT  0 3.312 0.084 3.336 ;
    END
  END in_t[88]
  PIN in_t[89]
    DIRECTION INPUT ;
    USE SIGNAL ;
    PORT
      LAYER M4 ;
        RECT  0 3.408 0.084 3.432 ;
    END
  END in_t[89]
  PIN in_t[8]
    DIRECTION INPUT ;
    USE SIGNAL ;
    PORT
      LAYER M4 ;
        RECT  0 20.976 0.084 21 ;
    END
  END in_t[8]
  PIN in_t[90]
    DIRECTION INPUT ;
    USE SIGNAL ;
    PORT
      LAYER M4 ;
        RECT  0 3.504 0.084 3.528 ;
    END
  END in_t[90]
  PIN in_t[91]
    DIRECTION INPUT ;
    USE SIGNAL ;
    PORT
      LAYER M4 ;
        RECT  0 3.6 0.084 3.624 ;
    END
  END in_t[91]
  PIN in_t[92]
    DIRECTION INPUT ;
    USE SIGNAL ;
    PORT
      LAYER M4 ;
        RECT  0 3.696 0.084 3.72 ;
    END
  END in_t[92]
  PIN in_t[93]
    DIRECTION INPUT ;
    USE SIGNAL ;
    PORT
      LAYER M4 ;
        RECT  0 3.792 0.084 3.816 ;
    END
  END in_t[93]
  PIN in_t[94]
    DIRECTION INPUT ;
    USE SIGNAL ;
    PORT
      LAYER M4 ;
        RECT  0 3.888 0.084 3.912 ;
    END
  END in_t[94]
  PIN in_t[95]
    DIRECTION INPUT ;
    USE SIGNAL ;
    PORT
      LAYER M4 ;
        RECT  0 3.984 0.084 4.008 ;
    END
  END in_t[95]
  PIN in_t[96]
    DIRECTION INPUT ;
    USE SIGNAL ;
    PORT
      LAYER M4 ;
        RECT  0 24.048 0.084 24.072 ;
    END
  END in_t[96]
  PIN in_t[97]
    DIRECTION INPUT ;
    USE SIGNAL ;
    PORT
      LAYER M4 ;
        RECT  0 24.144 0.084 24.168 ;
    END
  END in_t[97]
  PIN in_t[98]
    DIRECTION INPUT ;
    USE SIGNAL ;
    PORT
      LAYER M4 ;
        RECT  0 24.24 0.084 24.264 ;
    END
  END in_t[98]
  PIN in_t[99]
    DIRECTION INPUT ;
    USE SIGNAL ;
    PORT
      LAYER M4 ;
        RECT  0 24.336 0.084 24.36 ;
    END
  END in_t[99]
  PIN in_t[9]
    DIRECTION INPUT ;
    USE SIGNAL ;
    PORT
      LAYER M4 ;
        RECT  0 21.072 0.084 21.096 ;
    END
  END in_t[9]
  PIN in_valid[0]
    DIRECTION INPUT ;
    USE SIGNAL ;
    PORT
      LAYER M4 ;
        RECT  0 25.584 0.084 25.608 ;
    END
  END in_valid[0]
  PIN in_valid[1]
    DIRECTION INPUT ;
    USE SIGNAL ;
    PORT
      LAYER M4 ;
        RECT  0 25.68 0.084 25.704 ;
    END
  END in_valid[1]
  PIN in_valid[2]
    DIRECTION INPUT ;
    USE SIGNAL ;
    PORT
      LAYER M4 ;
        RECT  0 25.776 0.084 25.8 ;
    END
  END in_valid[2]
  PIN in_valid[3]
    DIRECTION INPUT ;
    USE SIGNAL ;
    PORT
      LAYER M4 ;
        RECT  0 25.872 0.084 25.896 ;
    END
  END in_valid[3]
  PIN in_valid[4]
    DIRECTION INPUT ;
    USE SIGNAL ;
    PORT
      LAYER M4 ;
        RECT  0 25.968 0.084 25.992 ;
    END
  END in_valid[4]
  PIN in_valid[5]
    DIRECTION INPUT ;
    USE SIGNAL ;
    PORT
      LAYER M4 ;
        RECT  0 26.064 0.084 26.088 ;
    END
  END in_valid[5]
  PIN in_valid[6]
    DIRECTION INPUT ;
    USE SIGNAL ;
    PORT
      LAYER M4 ;
        RECT  0 26.16 0.084 26.184 ;
    END
  END in_valid[6]
  PIN in_valid[7]
    DIRECTION INPUT ;
    USE SIGNAL ;
    PORT
      LAYER M4 ;
        RECT  0 26.256 0.084 26.28 ;
    END
  END in_valid[7]
  PIN out_age[0]
    DIRECTION OUTPUT ;
    USE SIGNAL ;
    PORT
      LAYER M5 ;
        RECT  10.032 0 10.056 0.084 ;
    END
  END out_age[0]
  PIN out_age[10]
    DIRECTION OUTPUT ;
    USE SIGNAL ;
    PORT
      LAYER M5 ;
        RECT  10.992 0 11.016 0.084 ;
    END
  END out_age[10]
  PIN out_age[11]
    DIRECTION OUTPUT ;
    USE SIGNAL ;
    PORT
      LAYER M5 ;
        RECT  11.088 0 11.112 0.084 ;
    END
  END out_age[11]
  PIN out_age[12]
    DIRECTION OUTPUT ;
    USE SIGNAL ;
    PORT
      LAYER M5 ;
        RECT  11.184 0 11.208 0.084 ;
    END
  END out_age[12]
  PIN out_age[13]
    DIRECTION OUTPUT ;
    USE SIGNAL ;
    PORT
      LAYER M5 ;
        RECT  11.28 0 11.304 0.084 ;
    END
  END out_age[13]
  PIN out_age[14]
    DIRECTION OUTPUT ;
    USE SIGNAL ;
    PORT
      LAYER M5 ;
        RECT  11.376 0 11.4 0.084 ;
    END
  END out_age[14]
  PIN out_age[15]
    DIRECTION OUTPUT ;
    USE SIGNAL ;
    PORT
      LAYER M5 ;
        RECT  11.472 0 11.496 0.084 ;
    END
  END out_age[15]
  PIN out_age[1]
    DIRECTION OUTPUT ;
    USE SIGNAL ;
    PORT
      LAYER M5 ;
        RECT  10.128 0 10.152 0.084 ;
    END
  END out_age[1]
  PIN out_age[2]
    DIRECTION OUTPUT ;
    USE SIGNAL ;
    PORT
      LAYER M5 ;
        RECT  10.224 0 10.248 0.084 ;
    END
  END out_age[2]
  PIN out_age[3]
    DIRECTION OUTPUT ;
    USE SIGNAL ;
    PORT
      LAYER M5 ;
        RECT  10.32 0 10.344 0.084 ;
    END
  END out_age[3]
  PIN out_age[4]
    DIRECTION OUTPUT ;
    USE SIGNAL ;
    PORT
      LAYER M5 ;
        RECT  10.416 0 10.44 0.084 ;
    END
  END out_age[4]
  PIN out_age[5]
    DIRECTION OUTPUT ;
    USE SIGNAL ;
    PORT
      LAYER M5 ;
        RECT  10.512 0 10.536 0.084 ;
    END
  END out_age[5]
  PIN out_age[6]
    DIRECTION OUTPUT ;
    USE SIGNAL ;
    PORT
      LAYER M5 ;
        RECT  10.608 0 10.632 0.084 ;
    END
  END out_age[6]
  PIN out_age[7]
    DIRECTION OUTPUT ;
    USE SIGNAL ;
    PORT
      LAYER M5 ;
        RECT  10.704 0 10.728 0.084 ;
    END
  END out_age[7]
  PIN out_age[8]
    DIRECTION OUTPUT ;
    USE SIGNAL ;
    PORT
      LAYER M5 ;
        RECT  10.8 0 10.824 0.084 ;
    END
  END out_age[8]
  PIN out_age[9]
    DIRECTION OUTPUT ;
    USE SIGNAL ;
    PORT
      LAYER M5 ;
        RECT  10.896 0 10.92 0.084 ;
    END
  END out_age[9]
  PIN out_epoch[0]
    DIRECTION OUTPUT ;
    USE SIGNAL ;
    PORT
      LAYER M5 ;
        RECT  11.568 0 11.592 0.084 ;
    END
  END out_epoch[0]
  PIN out_epoch[10]
    DIRECTION OUTPUT ;
    USE SIGNAL ;
    PORT
      LAYER M5 ;
        RECT  12.528 0 12.552 0.084 ;
    END
  END out_epoch[10]
  PIN out_epoch[11]
    DIRECTION OUTPUT ;
    USE SIGNAL ;
    PORT
      LAYER M5 ;
        RECT  12.624 0 12.648 0.084 ;
    END
  END out_epoch[11]
  PIN out_epoch[12]
    DIRECTION OUTPUT ;
    USE SIGNAL ;
    PORT
      LAYER M5 ;
        RECT  12.72 0 12.744 0.084 ;
    END
  END out_epoch[12]
  PIN out_epoch[13]
    DIRECTION OUTPUT ;
    USE SIGNAL ;
    PORT
      LAYER M5 ;
        RECT  12.816 0 12.84 0.084 ;
    END
  END out_epoch[13]
  PIN out_epoch[14]
    DIRECTION OUTPUT ;
    USE SIGNAL ;
    PORT
      LAYER M5 ;
        RECT  12.912 0 12.936 0.084 ;
    END
  END out_epoch[14]
  PIN out_epoch[15]
    DIRECTION OUTPUT ;
    USE SIGNAL ;
    PORT
      LAYER M5 ;
        RECT  13.008 0 13.032 0.084 ;
    END
  END out_epoch[15]
  PIN out_epoch[1]
    DIRECTION OUTPUT ;
    USE SIGNAL ;
    PORT
      LAYER M5 ;
        RECT  11.664 0 11.688 0.084 ;
    END
  END out_epoch[1]
  PIN out_epoch[2]
    DIRECTION OUTPUT ;
    USE SIGNAL ;
    PORT
      LAYER M5 ;
        RECT  11.76 0 11.784 0.084 ;
    END
  END out_epoch[2]
  PIN out_epoch[3]
    DIRECTION OUTPUT ;
    USE SIGNAL ;
    PORT
      LAYER M5 ;
        RECT  11.856 0 11.88 0.084 ;
    END
  END out_epoch[3]
  PIN out_epoch[4]
    DIRECTION OUTPUT ;
    USE SIGNAL ;
    PORT
      LAYER M5 ;
        RECT  11.952 0 11.976 0.084 ;
    END
  END out_epoch[4]
  PIN out_epoch[5]
    DIRECTION OUTPUT ;
    USE SIGNAL ;
    PORT
      LAYER M5 ;
        RECT  12.048 0 12.072 0.084 ;
    END
  END out_epoch[5]
  PIN out_epoch[6]
    DIRECTION OUTPUT ;
    USE SIGNAL ;
    PORT
      LAYER M5 ;
        RECT  12.144 0 12.168 0.084 ;
    END
  END out_epoch[6]
  PIN out_epoch[7]
    DIRECTION OUTPUT ;
    USE SIGNAL ;
    PORT
      LAYER M5 ;
        RECT  12.24 0 12.264 0.084 ;
    END
  END out_epoch[7]
  PIN out_epoch[8]
    DIRECTION OUTPUT ;
    USE SIGNAL ;
    PORT
      LAYER M5 ;
        RECT  12.336 0 12.36 0.084 ;
    END
  END out_epoch[8]
  PIN out_epoch[9]
    DIRECTION OUTPUT ;
    USE SIGNAL ;
    PORT
      LAYER M5 ;
        RECT  12.432 0 12.456 0.084 ;
    END
  END out_epoch[9]
  PIN pair_id
    DIRECTION INPUT ;
    USE SIGNAL ;
    PORT
      LAYER M5 ;
        RECT  13.104 0 13.128 0.084 ;
    END
  END pair_id
  PIN req_t[0]
    DIRECTION OUTPUT ;
    USE SIGNAL ;
    PORT
      LAYER M4 ;
        RECT  43.116 20.688 43.2 20.712 ;
    END
  END req_t[0]
  PIN req_t[100]
    DIRECTION OUTPUT ;
    USE SIGNAL ;
    PORT
      LAYER M4 ;
        RECT  43.116 11.088 43.2 11.112 ;
    END
  END req_t[100]
  PIN req_t[101]
    DIRECTION OUTPUT ;
    USE SIGNAL ;
    PORT
      LAYER M4 ;
        RECT  43.116 11.184 43.2 11.208 ;
    END
  END req_t[101]
  PIN req_t[102]
    DIRECTION OUTPUT ;
    USE SIGNAL ;
    PORT
      LAYER M4 ;
        RECT  43.116 11.28 43.2 11.304 ;
    END
  END req_t[102]
  PIN req_t[103]
    DIRECTION OUTPUT ;
    USE SIGNAL ;
    PORT
      LAYER M4 ;
        RECT  43.116 11.376 43.2 11.4 ;
    END
  END req_t[103]
  PIN req_t[104]
    DIRECTION OUTPUT ;
    USE SIGNAL ;
    PORT
      LAYER M4 ;
        RECT  43.116 11.472 43.2 11.496 ;
    END
  END req_t[104]
  PIN req_t[105]
    DIRECTION OUTPUT ;
    USE SIGNAL ;
    PORT
      LAYER M4 ;
        RECT  43.116 11.568 43.2 11.592 ;
    END
  END req_t[105]
  PIN req_t[106]
    DIRECTION OUTPUT ;
    USE SIGNAL ;
    PORT
      LAYER M4 ;
        RECT  43.116 11.664 43.2 11.688 ;
    END
  END req_t[106]
  PIN req_t[107]
    DIRECTION OUTPUT ;
    USE SIGNAL ;
    PORT
      LAYER M4 ;
        RECT  43.116 11.76 43.2 11.784 ;
    END
  END req_t[107]
  PIN req_t[108]
    DIRECTION OUTPUT ;
    USE SIGNAL ;
    PORT
      LAYER M4 ;
        RECT  43.116 11.856 43.2 11.88 ;
    END
  END req_t[108]
  PIN req_t[109]
    DIRECTION OUTPUT ;
    USE SIGNAL ;
    PORT
      LAYER M4 ;
        RECT  43.116 11.952 43.2 11.976 ;
    END
  END req_t[109]
  PIN req_t[10]
    DIRECTION OUTPUT ;
    USE SIGNAL ;
    PORT
      LAYER M4 ;
        RECT  43.116 21.648 43.2 21.672 ;
    END
  END req_t[10]
  PIN req_t[110]
    DIRECTION OUTPUT ;
    USE SIGNAL ;
    PORT
      LAYER M4 ;
        RECT  43.116 12.048 43.2 12.072 ;
    END
  END req_t[110]
  PIN req_t[111]
    DIRECTION OUTPUT ;
    USE SIGNAL ;
    PORT
      LAYER M4 ;
        RECT  43.116 12.144 43.2 12.168 ;
    END
  END req_t[111]
  PIN req_t[11]
    DIRECTION OUTPUT ;
    USE SIGNAL ;
    PORT
      LAYER M4 ;
        RECT  43.116 21.744 43.2 21.768 ;
    END
  END req_t[11]
  PIN req_t[12]
    DIRECTION OUTPUT ;
    USE SIGNAL ;
    PORT
      LAYER M4 ;
        RECT  43.116 21.84 43.2 21.864 ;
    END
  END req_t[12]
  PIN req_t[13]
    DIRECTION OUTPUT ;
    USE SIGNAL ;
    PORT
      LAYER M4 ;
        RECT  43.116 21.936 43.2 21.96 ;
    END
  END req_t[13]
  PIN req_t[14]
    DIRECTION OUTPUT ;
    USE SIGNAL ;
    PORT
      LAYER M4 ;
        RECT  43.116 22.032 43.2 22.056 ;
    END
  END req_t[14]
  PIN req_t[15]
    DIRECTION OUTPUT ;
    USE SIGNAL ;
    PORT
      LAYER M4 ;
        RECT  43.116 22.128 43.2 22.152 ;
    END
  END req_t[15]
  PIN req_t[16]
    DIRECTION OUTPUT ;
    USE SIGNAL ;
    PORT
      LAYER M4 ;
        RECT  43.116 22.224 43.2 22.248 ;
    END
  END req_t[16]
  PIN req_t[17]
    DIRECTION OUTPUT ;
    USE SIGNAL ;
    PORT
      LAYER M4 ;
        RECT  43.116 22.32 43.2 22.344 ;
    END
  END req_t[17]
  PIN req_t[18]
    DIRECTION OUTPUT ;
    USE SIGNAL ;
    PORT
      LAYER M4 ;
        RECT  43.116 22.416 43.2 22.44 ;
    END
  END req_t[18]
  PIN req_t[19]
    DIRECTION OUTPUT ;
    USE SIGNAL ;
    PORT
      LAYER M4 ;
        RECT  43.116 22.512 43.2 22.536 ;
    END
  END req_t[19]
  PIN req_t[1]
    DIRECTION OUTPUT ;
    USE SIGNAL ;
    PORT
      LAYER M4 ;
        RECT  43.116 20.784 43.2 20.808 ;
    END
  END req_t[1]
  PIN req_t[20]
    DIRECTION OUTPUT ;
    USE SIGNAL ;
    PORT
      LAYER M4 ;
        RECT  43.116 22.608 43.2 22.632 ;
    END
  END req_t[20]
  PIN req_t[21]
    DIRECTION OUTPUT ;
    USE SIGNAL ;
    PORT
      LAYER M4 ;
        RECT  43.116 22.704 43.2 22.728 ;
    END
  END req_t[21]
  PIN req_t[22]
    DIRECTION OUTPUT ;
    USE SIGNAL ;
    PORT
      LAYER M4 ;
        RECT  43.116 22.8 43.2 22.824 ;
    END
  END req_t[22]
  PIN req_t[23]
    DIRECTION OUTPUT ;
    USE SIGNAL ;
    PORT
      LAYER M4 ;
        RECT  43.116 22.896 43.2 22.92 ;
    END
  END req_t[23]
  PIN req_t[24]
    DIRECTION OUTPUT ;
    USE SIGNAL ;
    PORT
      LAYER M4 ;
        RECT  43.116 16.08 43.2 16.104 ;
    END
  END req_t[24]
  PIN req_t[25]
    DIRECTION OUTPUT ;
    USE SIGNAL ;
    PORT
      LAYER M4 ;
        RECT  43.116 16.176 43.2 16.2 ;
    END
  END req_t[25]
  PIN req_t[26]
    DIRECTION OUTPUT ;
    USE SIGNAL ;
    PORT
      LAYER M4 ;
        RECT  43.116 16.272 43.2 16.296 ;
    END
  END req_t[26]
  PIN req_t[27]
    DIRECTION OUTPUT ;
    USE SIGNAL ;
    PORT
      LAYER M4 ;
        RECT  43.116 16.368 43.2 16.392 ;
    END
  END req_t[27]
  PIN req_t[28]
    DIRECTION OUTPUT ;
    USE SIGNAL ;
    PORT
      LAYER M4 ;
        RECT  43.116 16.464 43.2 16.488 ;
    END
  END req_t[28]
  PIN req_t[29]
    DIRECTION OUTPUT ;
    USE SIGNAL ;
    PORT
      LAYER M4 ;
        RECT  43.116 16.56 43.2 16.584 ;
    END
  END req_t[29]
  PIN req_t[2]
    DIRECTION OUTPUT ;
    USE SIGNAL ;
    PORT
      LAYER M4 ;
        RECT  43.116 20.88 43.2 20.904 ;
    END
  END req_t[2]
  PIN req_t[30]
    DIRECTION OUTPUT ;
    USE SIGNAL ;
    PORT
      LAYER M4 ;
        RECT  43.116 16.656 43.2 16.68 ;
    END
  END req_t[30]
  PIN req_t[31]
    DIRECTION OUTPUT ;
    USE SIGNAL ;
    PORT
      LAYER M4 ;
        RECT  43.116 16.752 43.2 16.776 ;
    END
  END req_t[31]
  PIN req_t[32]
    DIRECTION OUTPUT ;
    USE SIGNAL ;
    PORT
      LAYER M4 ;
        RECT  43.116 16.848 43.2 16.872 ;
    END
  END req_t[32]
  PIN req_t[33]
    DIRECTION OUTPUT ;
    USE SIGNAL ;
    PORT
      LAYER M4 ;
        RECT  43.116 16.944 43.2 16.968 ;
    END
  END req_t[33]
  PIN req_t[34]
    DIRECTION OUTPUT ;
    USE SIGNAL ;
    PORT
      LAYER M4 ;
        RECT  43.116 17.04 43.2 17.064 ;
    END
  END req_t[34]
  PIN req_t[35]
    DIRECTION OUTPUT ;
    USE SIGNAL ;
    PORT
      LAYER M4 ;
        RECT  43.116 17.136 43.2 17.16 ;
    END
  END req_t[35]
  PIN req_t[36]
    DIRECTION OUTPUT ;
    USE SIGNAL ;
    PORT
      LAYER M4 ;
        RECT  43.116 17.232 43.2 17.256 ;
    END
  END req_t[36]
  PIN req_t[37]
    DIRECTION OUTPUT ;
    USE SIGNAL ;
    PORT
      LAYER M4 ;
        RECT  43.116 17.328 43.2 17.352 ;
    END
  END req_t[37]
  PIN req_t[38]
    DIRECTION OUTPUT ;
    USE SIGNAL ;
    PORT
      LAYER M4 ;
        RECT  43.116 17.424 43.2 17.448 ;
    END
  END req_t[38]
  PIN req_t[39]
    DIRECTION OUTPUT ;
    USE SIGNAL ;
    PORT
      LAYER M4 ;
        RECT  43.116 17.52 43.2 17.544 ;
    END
  END req_t[39]
  PIN req_t[3]
    DIRECTION OUTPUT ;
    USE SIGNAL ;
    PORT
      LAYER M4 ;
        RECT  43.116 20.976 43.2 21 ;
    END
  END req_t[3]
  PIN req_t[40]
    DIRECTION OUTPUT ;
    USE SIGNAL ;
    PORT
      LAYER M4 ;
        RECT  43.116 17.616 43.2 17.64 ;
    END
  END req_t[40]
  PIN req_t[41]
    DIRECTION OUTPUT ;
    USE SIGNAL ;
    PORT
      LAYER M4 ;
        RECT  43.116 17.712 43.2 17.736 ;
    END
  END req_t[41]
  PIN req_t[42]
    DIRECTION OUTPUT ;
    USE SIGNAL ;
    PORT
      LAYER M4 ;
        RECT  43.116 17.808 43.2 17.832 ;
    END
  END req_t[42]
  PIN req_t[43]
    DIRECTION OUTPUT ;
    USE SIGNAL ;
    PORT
      LAYER M4 ;
        RECT  43.116 17.904 43.2 17.928 ;
    END
  END req_t[43]
  PIN req_t[44]
    DIRECTION OUTPUT ;
    USE SIGNAL ;
    PORT
      LAYER M4 ;
        RECT  43.116 18 43.2 18.024 ;
    END
  END req_t[44]
  PIN req_t[45]
    DIRECTION OUTPUT ;
    USE SIGNAL ;
    PORT
      LAYER M4 ;
        RECT  43.116 18.096 43.2 18.12 ;
    END
  END req_t[45]
  PIN req_t[46]
    DIRECTION OUTPUT ;
    USE SIGNAL ;
    PORT
      LAYER M4 ;
        RECT  43.116 18.192 43.2 18.216 ;
    END
  END req_t[46]
  PIN req_t[47]
    DIRECTION OUTPUT ;
    USE SIGNAL ;
    PORT
      LAYER M4 ;
        RECT  43.116 18.288 43.2 18.312 ;
    END
  END req_t[47]
  PIN req_t[48]
    DIRECTION OUTPUT ;
    USE SIGNAL ;
    PORT
      LAYER M4 ;
        RECT  43.116 18.384 43.2 18.408 ;
    END
  END req_t[48]
  PIN req_t[49]
    DIRECTION OUTPUT ;
    USE SIGNAL ;
    PORT
      LAYER M4 ;
        RECT  43.116 18.48 43.2 18.504 ;
    END
  END req_t[49]
  PIN req_t[4]
    DIRECTION OUTPUT ;
    USE SIGNAL ;
    PORT
      LAYER M4 ;
        RECT  43.116 21.072 43.2 21.096 ;
    END
  END req_t[4]
  PIN req_t[50]
    DIRECTION OUTPUT ;
    USE SIGNAL ;
    PORT
      LAYER M4 ;
        RECT  43.116 18.576 43.2 18.6 ;
    END
  END req_t[50]
  PIN req_t[51]
    DIRECTION OUTPUT ;
    USE SIGNAL ;
    PORT
      LAYER M4 ;
        RECT  43.116 18.672 43.2 18.696 ;
    END
  END req_t[51]
  PIN req_t[52]
    DIRECTION OUTPUT ;
    USE SIGNAL ;
    PORT
      LAYER M4 ;
        RECT  43.116 18.768 43.2 18.792 ;
    END
  END req_t[52]
  PIN req_t[53]
    DIRECTION OUTPUT ;
    USE SIGNAL ;
    PORT
      LAYER M4 ;
        RECT  43.116 18.864 43.2 18.888 ;
    END
  END req_t[53]
  PIN req_t[54]
    DIRECTION OUTPUT ;
    USE SIGNAL ;
    PORT
      LAYER M4 ;
        RECT  43.116 18.96 43.2 18.984 ;
    END
  END req_t[54]
  PIN req_t[55]
    DIRECTION OUTPUT ;
    USE SIGNAL ;
    PORT
      LAYER M4 ;
        RECT  43.116 19.056 43.2 19.08 ;
    END
  END req_t[55]
  PIN req_t[56]
    DIRECTION OUTPUT ;
    USE SIGNAL ;
    PORT
      LAYER M4 ;
        RECT  43.116 13.008 43.2 13.032 ;
    END
  END req_t[56]
  PIN req_t[57]
    DIRECTION OUTPUT ;
    USE SIGNAL ;
    PORT
      LAYER M4 ;
        RECT  43.116 13.104 43.2 13.128 ;
    END
  END req_t[57]
  PIN req_t[58]
    DIRECTION OUTPUT ;
    USE SIGNAL ;
    PORT
      LAYER M4 ;
        RECT  43.116 13.2 43.2 13.224 ;
    END
  END req_t[58]
  PIN req_t[59]
    DIRECTION OUTPUT ;
    USE SIGNAL ;
    PORT
      LAYER M4 ;
        RECT  43.116 13.296 43.2 13.32 ;
    END
  END req_t[59]
  PIN req_t[5]
    DIRECTION OUTPUT ;
    USE SIGNAL ;
    PORT
      LAYER M4 ;
        RECT  43.116 21.168 43.2 21.192 ;
    END
  END req_t[5]
  PIN req_t[60]
    DIRECTION OUTPUT ;
    USE SIGNAL ;
    PORT
      LAYER M4 ;
        RECT  43.116 13.392 43.2 13.416 ;
    END
  END req_t[60]
  PIN req_t[61]
    DIRECTION OUTPUT ;
    USE SIGNAL ;
    PORT
      LAYER M4 ;
        RECT  43.116 13.488 43.2 13.512 ;
    END
  END req_t[61]
  PIN req_t[62]
    DIRECTION OUTPUT ;
    USE SIGNAL ;
    PORT
      LAYER M4 ;
        RECT  43.116 13.584 43.2 13.608 ;
    END
  END req_t[62]
  PIN req_t[63]
    DIRECTION OUTPUT ;
    USE SIGNAL ;
    PORT
      LAYER M4 ;
        RECT  43.116 13.68 43.2 13.704 ;
    END
  END req_t[63]
  PIN req_t[64]
    DIRECTION OUTPUT ;
    USE SIGNAL ;
    PORT
      LAYER M4 ;
        RECT  43.116 13.776 43.2 13.8 ;
    END
  END req_t[64]
  PIN req_t[65]
    DIRECTION OUTPUT ;
    USE SIGNAL ;
    PORT
      LAYER M4 ;
        RECT  43.116 13.872 43.2 13.896 ;
    END
  END req_t[65]
  PIN req_t[66]
    DIRECTION OUTPUT ;
    USE SIGNAL ;
    PORT
      LAYER M4 ;
        RECT  43.116 13.968 43.2 13.992 ;
    END
  END req_t[66]
  PIN req_t[67]
    DIRECTION OUTPUT ;
    USE SIGNAL ;
    PORT
      LAYER M4 ;
        RECT  43.116 14.064 43.2 14.088 ;
    END
  END req_t[67]
  PIN req_t[68]
    DIRECTION OUTPUT ;
    USE SIGNAL ;
    PORT
      LAYER M4 ;
        RECT  43.116 14.16 43.2 14.184 ;
    END
  END req_t[68]
  PIN req_t[69]
    DIRECTION OUTPUT ;
    USE SIGNAL ;
    PORT
      LAYER M4 ;
        RECT  43.116 14.256 43.2 14.28 ;
    END
  END req_t[69]
  PIN req_t[6]
    DIRECTION OUTPUT ;
    USE SIGNAL ;
    PORT
      LAYER M4 ;
        RECT  43.116 21.264 43.2 21.288 ;
    END
  END req_t[6]
  PIN req_t[70]
    DIRECTION OUTPUT ;
    USE SIGNAL ;
    PORT
      LAYER M4 ;
        RECT  43.116 14.352 43.2 14.376 ;
    END
  END req_t[70]
  PIN req_t[71]
    DIRECTION OUTPUT ;
    USE SIGNAL ;
    PORT
      LAYER M4 ;
        RECT  43.116 14.448 43.2 14.472 ;
    END
  END req_t[71]
  PIN req_t[72]
    DIRECTION OUTPUT ;
    USE SIGNAL ;
    PORT
      LAYER M4 ;
        RECT  43.116 14.544 43.2 14.568 ;
    END
  END req_t[72]
  PIN req_t[73]
    DIRECTION OUTPUT ;
    USE SIGNAL ;
    PORT
      LAYER M4 ;
        RECT  43.116 14.64 43.2 14.664 ;
    END
  END req_t[73]
  PIN req_t[74]
    DIRECTION OUTPUT ;
    USE SIGNAL ;
    PORT
      LAYER M4 ;
        RECT  43.116 14.736 43.2 14.76 ;
    END
  END req_t[74]
  PIN req_t[75]
    DIRECTION OUTPUT ;
    USE SIGNAL ;
    PORT
      LAYER M4 ;
        RECT  43.116 14.832 43.2 14.856 ;
    END
  END req_t[75]
  PIN req_t[76]
    DIRECTION OUTPUT ;
    USE SIGNAL ;
    PORT
      LAYER M4 ;
        RECT  43.116 14.928 43.2 14.952 ;
    END
  END req_t[76]
  PIN req_t[77]
    DIRECTION OUTPUT ;
    USE SIGNAL ;
    PORT
      LAYER M4 ;
        RECT  43.116 15.024 43.2 15.048 ;
    END
  END req_t[77]
  PIN req_t[78]
    DIRECTION OUTPUT ;
    USE SIGNAL ;
    PORT
      LAYER M4 ;
        RECT  43.116 15.12 43.2 15.144 ;
    END
  END req_t[78]
  PIN req_t[79]
    DIRECTION OUTPUT ;
    USE SIGNAL ;
    PORT
      LAYER M4 ;
        RECT  43.116 15.216 43.2 15.24 ;
    END
  END req_t[79]
  PIN req_t[7]
    DIRECTION OUTPUT ;
    USE SIGNAL ;
    PORT
      LAYER M4 ;
        RECT  43.116 21.36 43.2 21.384 ;
    END
  END req_t[7]
  PIN req_t[80]
    DIRECTION OUTPUT ;
    USE SIGNAL ;
    PORT
      LAYER M4 ;
        RECT  43.116 15.312 43.2 15.336 ;
    END
  END req_t[80]
  PIN req_t[81]
    DIRECTION OUTPUT ;
    USE SIGNAL ;
    PORT
      LAYER M4 ;
        RECT  43.116 15.408 43.2 15.432 ;
    END
  END req_t[81]
  PIN req_t[82]
    DIRECTION OUTPUT ;
    USE SIGNAL ;
    PORT
      LAYER M4 ;
        RECT  43.116 15.504 43.2 15.528 ;
    END
  END req_t[82]
  PIN req_t[83]
    DIRECTION OUTPUT ;
    USE SIGNAL ;
    PORT
      LAYER M4 ;
        RECT  43.116 15.6 43.2 15.624 ;
    END
  END req_t[83]
  PIN req_t[84]
    DIRECTION OUTPUT ;
    USE SIGNAL ;
    PORT
      LAYER M4 ;
        RECT  43.116 15.696 43.2 15.72 ;
    END
  END req_t[84]
  PIN req_t[85]
    DIRECTION OUTPUT ;
    USE SIGNAL ;
    PORT
      LAYER M4 ;
        RECT  43.116 15.792 43.2 15.816 ;
    END
  END req_t[85]
  PIN req_t[86]
    DIRECTION OUTPUT ;
    USE SIGNAL ;
    PORT
      LAYER M4 ;
        RECT  43.116 15.888 43.2 15.912 ;
    END
  END req_t[86]
  PIN req_t[87]
    DIRECTION OUTPUT ;
    USE SIGNAL ;
    PORT
      LAYER M4 ;
        RECT  43.116 15.984 43.2 16.008 ;
    END
  END req_t[87]
  PIN req_t[88]
    DIRECTION OUTPUT ;
    USE SIGNAL ;
    PORT
      LAYER M4 ;
        RECT  43.116 9.936 43.2 9.96 ;
    END
  END req_t[88]
  PIN req_t[89]
    DIRECTION OUTPUT ;
    USE SIGNAL ;
    PORT
      LAYER M4 ;
        RECT  43.116 10.032 43.2 10.056 ;
    END
  END req_t[89]
  PIN req_t[8]
    DIRECTION OUTPUT ;
    USE SIGNAL ;
    PORT
      LAYER M4 ;
        RECT  43.116 21.456 43.2 21.48 ;
    END
  END req_t[8]
  PIN req_t[90]
    DIRECTION OUTPUT ;
    USE SIGNAL ;
    PORT
      LAYER M4 ;
        RECT  43.116 10.128 43.2 10.152 ;
    END
  END req_t[90]
  PIN req_t[91]
    DIRECTION OUTPUT ;
    USE SIGNAL ;
    PORT
      LAYER M4 ;
        RECT  43.116 10.224 43.2 10.248 ;
    END
  END req_t[91]
  PIN req_t[92]
    DIRECTION OUTPUT ;
    USE SIGNAL ;
    PORT
      LAYER M4 ;
        RECT  43.116 10.32 43.2 10.344 ;
    END
  END req_t[92]
  PIN req_t[93]
    DIRECTION OUTPUT ;
    USE SIGNAL ;
    PORT
      LAYER M4 ;
        RECT  43.116 10.416 43.2 10.44 ;
    END
  END req_t[93]
  PIN req_t[94]
    DIRECTION OUTPUT ;
    USE SIGNAL ;
    PORT
      LAYER M4 ;
        RECT  43.116 10.512 43.2 10.536 ;
    END
  END req_t[94]
  PIN req_t[95]
    DIRECTION OUTPUT ;
    USE SIGNAL ;
    PORT
      LAYER M4 ;
        RECT  43.116 10.608 43.2 10.632 ;
    END
  END req_t[95]
  PIN req_t[96]
    DIRECTION OUTPUT ;
    USE SIGNAL ;
    PORT
      LAYER M4 ;
        RECT  43.116 10.704 43.2 10.728 ;
    END
  END req_t[96]
  PIN req_t[97]
    DIRECTION OUTPUT ;
    USE SIGNAL ;
    PORT
      LAYER M4 ;
        RECT  43.116 10.8 43.2 10.824 ;
    END
  END req_t[97]
  PIN req_t[98]
    DIRECTION OUTPUT ;
    USE SIGNAL ;
    PORT
      LAYER M4 ;
        RECT  43.116 10.896 43.2 10.92 ;
    END
  END req_t[98]
  PIN req_t[99]
    DIRECTION OUTPUT ;
    USE SIGNAL ;
    PORT
      LAYER M4 ;
        RECT  43.116 10.992 43.2 11.016 ;
    END
  END req_t[99]
  PIN req_t[9]
    DIRECTION OUTPUT ;
    USE SIGNAL ;
    PORT
      LAYER M4 ;
        RECT  43.116 21.552 43.2 21.576 ;
    END
  END req_t[9]
  PIN req_valid[0]
    DIRECTION OUTPUT ;
    USE SIGNAL ;
    PORT
      LAYER M4 ;
        RECT  43.116 12.24 43.2 12.264 ;
    END
  END req_valid[0]
  PIN req_valid[1]
    DIRECTION OUTPUT ;
    USE SIGNAL ;
    PORT
      LAYER M4 ;
        RECT  43.116 12.336 43.2 12.36 ;
    END
  END req_valid[1]
  PIN req_valid[2]
    DIRECTION OUTPUT ;
    USE SIGNAL ;
    PORT
      LAYER M4 ;
        RECT  43.116 12.432 43.2 12.456 ;
    END
  END req_valid[2]
  PIN req_valid[3]
    DIRECTION OUTPUT ;
    USE SIGNAL ;
    PORT
      LAYER M4 ;
        RECT  43.116 12.528 43.2 12.552 ;
    END
  END req_valid[3]
  PIN req_valid[4]
    DIRECTION OUTPUT ;
    USE SIGNAL ;
    PORT
      LAYER M4 ;
        RECT  43.116 12.624 43.2 12.648 ;
    END
  END req_valid[4]
  PIN req_valid[5]
    DIRECTION OUTPUT ;
    USE SIGNAL ;
    PORT
      LAYER M4 ;
        RECT  43.116 12.72 43.2 12.744 ;
    END
  END req_valid[5]
  PIN req_valid[6]
    DIRECTION OUTPUT ;
    USE SIGNAL ;
    PORT
      LAYER M4 ;
        RECT  43.116 12.816 43.2 12.84 ;
    END
  END req_valid[6]
  PIN req_valid[7]
    DIRECTION OUTPUT ;
    USE SIGNAL ;
    PORT
      LAYER M4 ;
        RECT  43.116 12.912 43.2 12.936 ;
    END
  END req_valid[7]
  PIN rst_n
    DIRECTION INPUT ;
    USE SIGNAL ;
    PORT
      LAYER M5 ;
        RECT  13.2 0 13.224 0.084 ;
    END
  END rst_n
  PIN start
    DIRECTION INPUT ;
    USE SIGNAL ;
    PORT
      LAYER M5 ;
        RECT  13.296 0 13.32 0.084 ;
    END
  END start
  PIN VDD
    DIRECTION INOUT ;
    USE POWER ;
    PORT
      LAYER M5 ;
        RECT  40.392 2.151 40.512 41.049 ;
        RECT  34.992 2.151 35.112 41.049 ;
        RECT  29.592 2.151 29.712 41.049 ;
        RECT  24.192 2.151 24.312 41.049 ;
        RECT  18.792 2.151 18.912 41.049 ;
        RECT  13.392 2.151 13.512 41.049 ;
        RECT  7.992 2.151 8.112 41.049 ;
        RECT  2.592 2.151 2.712 41.049 ;
    END
  END VDD
  PIN VSS
    DIRECTION INOUT ;
    USE GROUND ;
    PORT
      LAYER M5 ;
        RECT  40.2 2.137 40.32 41.063 ;
        RECT  34.8 2.137 34.92 41.063 ;
        RECT  29.4 2.137 29.52 41.063 ;
        RECT  24 2.137 24.12 41.063 ;
        RECT  18.6 2.137 18.72 41.063 ;
        RECT  13.2 2.137 13.32 41.063 ;
        RECT  7.8 2.137 7.92 41.063 ;
        RECT  2.4 2.137 2.52 41.063 ;
    END
  END VSS
  # OT_OBS_CLOSED layer=M5 d_um=1.536 added=158
  OBS
    LAYER LVTN ;
     RECT  13.23 14.445 13.77 14.58 ;
     RECT  13.338 14.58 13.77 14.715 ;
     RECT  12.582 15.12 13.446 15.255 ;
     RECT  10.908 18.225 11.232 18.36 ;
     RECT  11.286 18.225 11.61 18.36 ;
     RECT  10.962 18.36 11.502 18.495 ;
     RECT  11.718 18.765 12.528 18.9 ;
     RECT  14.364 19.44 14.796 19.575 ;
     RECT  14.904 19.44 15.282 19.575 ;
     RECT  15.012 19.845 15.336 19.98 ;
     RECT  22.41 19.98 22.95 20.115 ;
     RECT  17.496 20.385 17.982 20.52 ;
     RECT  21.978 20.385 22.302 20.52 ;
     RECT  16.254 20.52 16.578 20.655 ;
     RECT  22.248 20.52 23.004 20.655 ;
     RECT  14.364 20.925 14.904 21.06 ;
     RECT  15.93 20.925 16.794 21.06 ;
     RECT  15.93 21.06 16.578 21.195 ;
     RECT  20.088 21.06 20.574 21.195 ;
     RECT  20.736 21.06 21.114 21.195 ;
     RECT  15.066 21.6 15.498 21.735 ;
     RECT  17.28 21.6 17.712 21.735 ;
     RECT  14.472 22.005 15.228 22.14 ;
     RECT  17.496 22.005 18.09 22.14 ;
     RECT  22.14 22.005 22.68 22.14 ;
     RECT  15.066 22.14 15.498 22.275 ;
     RECT  9.774 23.22 10.422 23.355 ;
     RECT  20.466 23.22 20.898 23.355 ;
     RECT  20.034 23.76 20.574 23.895 ;
     RECT  20.142 24.165 20.466 24.3 ;
     RECT  27.972 24.165 28.782 24.3 ;
     RECT  9.396 24.3 10.206 24.435 ;
     RECT  22.14 24.3 23.004 24.435 ;
     RECT  17.604 24.705 18.576 24.84 ;
     RECT  20.412 24.705 20.736 24.84 ;
     RECT  25.758 24.705 26.136 24.84 ;
     RECT  30.456 24.705 30.834 24.84 ;
     RECT  17.442 24.84 17.982 24.975 ;
     RECT  22.464 25.245 23.328 25.38 ;
     RECT  23.436 25.245 23.976 25.38 ;
     RECT  27.27 25.245 27.864 25.38 ;
     RECT  16.902 25.38 17.334 25.515 ;
     RECT  23.058 25.38 23.598 25.515 ;
     RECT  25.812 25.38 26.244 25.515 ;
     RECT  16.47 25.785 17.064 25.92 ;
     RECT  22.95 25.785 23.49 25.92 ;
     RECT  23.976 25.785 24.462 25.92 ;
     RECT  23.76 25.92 24.192 26.055 ;
     RECT  16.038 26.325 16.47 26.46 ;
     RECT  30.24 26.325 30.402 26.46 ;
     RECT  10.098 26.46 10.962 26.595 ;
     RECT  16.092 26.46 16.686 26.595 ;
     RECT  17.55 26.46 18.414 26.595 ;
     RECT  24.084 26.46 24.462 26.595 ;
     RECT  25.542 26.46 26.298 26.595 ;
     RECT  28.242 26.46 28.674 26.595 ;
     RECT  29.376 26.46 29.916 26.595 ;
     RECT  31.482 26.46 31.914 26.595 ;
     RECT  24.948 26.865 25.272 27 ;
     RECT  30.294 26.865 30.618 27 ;
     RECT  31.266 26.865 31.698 27 ;
     RECT  11.07 27 11.61 27.135 ;
     RECT  24.624 27 25.056 27.135 ;
     RECT  20.088 27.405 20.628 27.54 ;
     RECT  30.348 27.405 31.266 27.54 ;
     RECT  13.23 27.54 13.662 27.675 ;
     RECT  10.26 28.08 10.638 28.215 ;
     RECT  13.122 28.08 13.554 28.215 ;
     RECT  11.124 28.485 11.556 28.62 ;
     RECT  9.018 28.62 9.396 28.755 ;
     RECT  13.284 28.62 13.824 28.755 ;
     RECT  30.24 29.025 30.51 29.16 ;
     RECT  13.176 29.16 13.554 29.295 ;
     RECT  12.798 29.565 14.256 29.7 ;
     RECT  13.608 29.7 14.148 29.835 ;
     RECT  14.958 29.7 15.282 29.835 ;
     RECT  28.566 29.7 28.89 29.835 ;
     RECT  15.12 30.105 15.444 30.24 ;
     RECT  16.038 30.105 16.47 30.24 ;
     RECT  29.862 30.105 30.402 30.24 ;
     RECT  13.5 30.24 13.824 30.375 ;
     RECT  29.43 30.24 29.862 30.375 ;
     RECT  29.43 30.645 30.186 30.78 ;
     RECT  29.322 30.78 29.862 30.915 ;
     RECT  13.878 31.32 14.418 31.455 ;
     RECT  19.926 32.805 20.196 32.94 ;
     RECT  23.004 33.48 23.436 33.615 ;
     RECT  14.364 33.885 14.688 34.02 ;
     RECT  14.364 34.02 14.796 34.155 ;
     RECT  18.306 34.02 18.63 34.155 ;
     RECT  18.738 34.02 19.17 34.155 ;
     RECT  12.852 34.425 13.392 34.56 ;
     RECT  13.5 34.425 13.824 34.56 ;
     RECT  23.166 34.425 23.598 34.56 ;
     RECT  14.418 34.56 14.958 34.695 ;
     RECT  18.576 34.56 18.9 34.695 ;
     RECT  25.704 34.56 26.028 34.695 ;
     RECT  13.014 34.965 13.662 35.1 ;
     RECT  15.012 34.965 15.552 35.1 ;
     RECT  18.036 34.965 18.468 35.1 ;
     RECT  22.842 34.965 23.274 35.1 ;
     RECT  12.906 35.1 13.446 35.235 ;
     RECT  23.058 35.1 23.598 35.235 ;
     RECT  18.576 35.64 19.656 35.775 ;
     RECT  22.896 36.045 23.328 36.18 ;
     RECT  20.358 36.18 21.06 36.315 ;
     RECT  22.68 36.18 23.112 36.315 ;
     RECT  14.364 36.585 14.796 36.72 ;
     RECT  22.572 36.585 23.22 36.72 ;
     RECT  14.85 36.72 15.39 36.855 ;
     RECT  14.094 37.125 14.634 37.26 ;
     RECT  22.572 37.125 22.896 37.26 ;
    LAYER LVTP ;
     RECT  13.23 14.31 13.77 14.445 ;
     RECT  13.338 14.715 13.77 14.85 ;
     RECT  12.582 15.255 13.446 15.39 ;
     RECT  10.908 18.09 11.232 18.225 ;
     RECT  11.286 18.09 11.61 18.225 ;
     RECT  10.962 18.495 11.502 18.63 ;
     RECT  11.718 18.63 12.528 18.765 ;
     RECT  14.364 19.575 14.796 19.71 ;
     RECT  14.904 19.575 15.282 19.71 ;
     RECT  15.012 19.71 15.336 19.845 ;
     RECT  22.41 20.115 22.95 20.25 ;
     RECT  17.496 20.25 17.982 20.385 ;
     RECT  21.978 20.25 22.302 20.385 ;
     RECT  16.254 20.655 16.578 20.79 ;
     RECT  22.248 20.655 23.004 20.79 ;
     RECT  14.364 20.79 14.904 20.925 ;
     RECT  15.93 20.79 16.794 20.925 ;
     RECT  15.93 21.195 16.578 21.33 ;
     RECT  20.088 21.195 20.574 21.33 ;
     RECT  20.736 21.195 21.114 21.33 ;
     RECT  15.066 21.735 15.498 21.87 ;
     RECT  17.28 21.735 17.712 21.87 ;
     RECT  14.472 21.87 15.228 22.005 ;
     RECT  17.496 21.87 18.09 22.005 ;
     RECT  22.14 21.87 22.68 22.005 ;
     RECT  15.066 22.275 15.498 22.41 ;
     RECT  9.774 23.355 10.422 23.49 ;
     RECT  20.466 23.355 20.898 23.49 ;
     RECT  20.034 23.895 20.574 24.03 ;
     RECT  20.142 24.03 20.466 24.165 ;
     RECT  27.972 24.03 28.782 24.165 ;
     RECT  9.396 24.435 10.206 24.57 ;
     RECT  22.14 24.435 23.004 24.57 ;
     RECT  17.604 24.57 18.576 24.705 ;
     RECT  20.412 24.57 20.736 24.705 ;
     RECT  25.758 24.57 26.136 24.705 ;
     RECT  30.456 24.57 30.834 24.705 ;
     RECT  17.442 24.975 17.982 25.11 ;
     RECT  22.464 25.11 23.328 25.245 ;
     RECT  23.436 25.11 23.976 25.245 ;
     RECT  27.27 25.11 27.864 25.245 ;
     RECT  16.902 25.515 17.334 25.65 ;
     RECT  23.058 25.515 23.598 25.65 ;
     RECT  25.812 25.515 26.244 25.65 ;
     RECT  16.47 25.65 17.064 25.785 ;
     RECT  22.95 25.65 23.49 25.785 ;
     RECT  23.976 25.65 24.462 25.785 ;
     RECT  23.76 26.055 24.192 26.19 ;
     RECT  16.038 26.19 16.47 26.325 ;
     RECT  30.24 26.19 30.402 26.325 ;
     RECT  10.098 26.595 10.962 26.73 ;
     RECT  16.092 26.595 16.686 26.73 ;
     RECT  17.55 26.595 18.414 26.73 ;
     RECT  24.084 26.595 24.462 26.73 ;
     RECT  25.542 26.595 26.298 26.73 ;
     RECT  28.242 26.595 28.674 26.73 ;
     RECT  29.376 26.595 29.916 26.73 ;
     RECT  31.482 26.595 31.914 26.73 ;
     RECT  24.948 26.73 25.272 26.865 ;
     RECT  30.294 26.73 30.618 26.865 ;
     RECT  31.266 26.73 31.698 26.865 ;
     RECT  11.07 27.135 11.61 27.27 ;
     RECT  24.624 27.135 25.056 27.27 ;
     RECT  20.088 27.27 20.628 27.405 ;
     RECT  30.348 27.27 31.266 27.405 ;
     RECT  13.23 27.675 13.662 27.81 ;
     RECT  10.26 28.215 10.638 28.35 ;
     RECT  13.122 28.215 13.554 28.35 ;
     RECT  11.124 28.35 11.556 28.485 ;
     RECT  9.018 28.755 9.396 28.89 ;
     RECT  13.284 28.755 13.824 28.89 ;
     RECT  30.24 28.89 30.51 29.025 ;
     RECT  13.176 29.295 13.554 29.43 ;
     RECT  12.798 29.43 14.256 29.565 ;
     RECT  13.608 29.835 14.148 29.97 ;
     RECT  14.958 29.835 15.282 29.97 ;
     RECT  28.566 29.835 28.89 29.97 ;
     RECT  15.12 29.97 15.444 30.105 ;
     RECT  16.038 29.97 16.47 30.105 ;
     RECT  29.862 29.97 30.402 30.105 ;
     RECT  13.5 30.375 13.824 30.51 ;
     RECT  29.43 30.375 29.862 30.51 ;
     RECT  29.43 30.51 30.186 30.645 ;
     RECT  29.322 30.915 29.862 31.05 ;
     RECT  13.878 31.455 14.418 31.59 ;
     RECT  19.926 32.67 20.196 32.805 ;
     RECT  23.004 33.615 23.436 33.75 ;
     RECT  14.364 33.75 14.688 33.885 ;
     RECT  14.364 34.155 14.796 34.29 ;
     RECT  18.306 34.155 18.63 34.29 ;
     RECT  18.738 34.155 19.17 34.29 ;
     RECT  12.852 34.29 13.392 34.425 ;
     RECT  13.5 34.29 13.824 34.425 ;
     RECT  23.166 34.29 23.598 34.425 ;
     RECT  14.418 34.695 14.958 34.83 ;
     RECT  18.576 34.695 18.9 34.83 ;
     RECT  25.704 34.695 26.028 34.83 ;
     RECT  13.014 34.83 13.662 34.965 ;
     RECT  15.012 34.83 15.552 34.965 ;
     RECT  18.036 34.83 18.468 34.965 ;
     RECT  22.842 34.83 23.274 34.965 ;
     RECT  12.906 35.235 13.446 35.37 ;
     RECT  23.058 35.235 23.598 35.37 ;
     RECT  18.576 35.775 19.656 35.91 ;
     RECT  22.896 35.91 23.328 36.045 ;
     RECT  20.358 36.315 21.06 36.45 ;
     RECT  22.68 36.315 23.112 36.45 ;
     RECT  14.364 36.45 14.796 36.585 ;
     RECT  22.572 36.45 23.22 36.585 ;
     RECT  14.85 36.855 15.39 36.99 ;
     RECT  14.094 36.99 14.634 37.125 ;
     RECT  22.572 36.99 22.896 37.125 ;
    LAYER RVTN ;
     RECT  2.16 2.16 41.04 2.295 ;
     RECT  2.16 2.565 41.04 2.835 ;
     RECT  2.16 3.105 41.04 3.375 ;
     RECT  2.16 3.645 41.04 3.915 ;
     RECT  2.16 4.185 41.04 4.455 ;
     RECT  2.16 4.725 41.04 4.995 ;
     RECT  2.16 5.265 41.04 5.535 ;
     RECT  2.16 5.805 41.04 6.075 ;
     RECT  2.16 6.345 41.04 6.615 ;
     RECT  2.16 6.885 41.04 7.155 ;
     RECT  2.16 7.425 41.04 7.695 ;
     RECT  2.16 7.965 41.04 8.235 ;
     RECT  2.16 8.505 41.04 8.775 ;
     RECT  2.16 9.045 41.04 9.315 ;
     RECT  2.16 9.585 41.04 9.855 ;
     RECT  2.16 10.125 41.04 10.395 ;
     RECT  2.16 10.665 41.04 10.935 ;
     RECT  2.16 11.205 41.04 11.475 ;
     RECT  2.16 11.745 41.04 12.015 ;
     RECT  2.16 12.285 41.04 12.555 ;
     RECT  2.16 12.825 41.04 13.095 ;
     RECT  2.16 13.365 41.04 13.635 ;
     RECT  2.16 13.905 41.04 14.175 ;
     RECT  2.16 14.445 13.23 14.58 ;
     RECT  2.16 14.58 13.338 14.715 ;
     RECT  13.77 14.445 41.04 14.715 ;
     RECT  2.16 14.985 41.04 15.12 ;
     RECT  2.16 15.12 12.582 15.255 ;
     RECT  13.446 15.12 41.04 15.255 ;
     RECT  2.16 15.525 41.04 15.795 ;
     RECT  2.16 16.065 41.04 16.335 ;
     RECT  2.16 16.605 41.04 16.875 ;
     RECT  2.16 17.145 41.04 17.415 ;
     RECT  2.16 17.685 41.04 17.955 ;
     RECT  2.16 18.225 10.908 18.36 ;
     RECT  11.232 18.225 11.286 18.36 ;
     RECT  11.61 18.225 41.04 18.36 ;
     RECT  2.16 18.36 10.962 18.495 ;
     RECT  11.502 18.36 41.04 18.495 ;
     RECT  2.16 18.765 11.718 18.9 ;
     RECT  12.528 18.765 41.04 18.9 ;
     RECT  2.16 18.9 41.04 19.035 ;
     RECT  2.16 19.305 41.04 19.44 ;
     RECT  2.16 19.44 14.364 19.575 ;
     RECT  14.796 19.44 14.904 19.575 ;
     RECT  15.282 19.44 41.04 19.575 ;
     RECT  2.16 19.845 15.012 19.98 ;
     RECT  15.336 19.845 41.04 19.98 ;
     RECT  2.16 19.98 22.41 20.115 ;
     RECT  22.95 19.98 41.04 20.115 ;
     RECT  2.16 20.385 17.496 20.52 ;
     RECT  17.982 20.385 21.978 20.52 ;
     RECT  22.302 20.385 41.04 20.52 ;
     RECT  2.16 20.52 16.254 20.655 ;
     RECT  16.578 20.52 22.248 20.655 ;
     RECT  23.004 20.52 41.04 20.655 ;
     RECT  2.16 20.925 14.364 21.06 ;
     RECT  14.904 20.925 15.93 21.06 ;
     RECT  16.794 20.925 41.04 21.06 ;
     RECT  2.16 21.06 15.93 21.195 ;
     RECT  16.578 21.06 20.088 21.195 ;
     RECT  20.574 21.06 20.736 21.195 ;
     RECT  21.114 21.06 41.04 21.195 ;
     RECT  2.16 21.465 41.04 21.6 ;
     RECT  2.16 21.6 15.066 21.735 ;
     RECT  15.498 21.6 17.28 21.735 ;
     RECT  17.712 21.6 41.04 21.735 ;
     RECT  2.16 22.005 14.472 22.14 ;
     RECT  15.228 22.005 17.496 22.14 ;
     RECT  18.09 22.005 22.14 22.14 ;
     RECT  22.68 22.005 41.04 22.14 ;
     RECT  2.16 22.14 15.066 22.275 ;
     RECT  15.498 22.14 41.04 22.275 ;
     RECT  2.16 22.545 41.04 22.815 ;
     RECT  2.16 23.085 41.04 23.22 ;
     RECT  2.16 23.22 9.774 23.355 ;
     RECT  10.422 23.22 20.466 23.355 ;
     RECT  20.898 23.22 41.04 23.355 ;
     RECT  2.16 23.625 41.04 23.76 ;
     RECT  2.16 23.76 20.034 23.895 ;
     RECT  20.574 23.76 41.04 23.895 ;
     RECT  2.16 24.165 20.142 24.3 ;
     RECT  20.466 24.165 27.972 24.3 ;
     RECT  28.782 24.165 41.04 24.3 ;
     RECT  2.16 24.3 9.396 24.435 ;
     RECT  10.206 24.3 22.14 24.435 ;
     RECT  23.004 24.3 41.04 24.435 ;
     RECT  2.16 24.705 17.604 24.84 ;
     RECT  18.576 24.705 20.412 24.84 ;
     RECT  20.736 24.705 25.758 24.84 ;
     RECT  26.136 24.705 30.456 24.84 ;
     RECT  30.834 24.705 41.04 24.84 ;
     RECT  2.16 24.84 17.442 24.975 ;
     RECT  17.982 24.84 41.04 24.975 ;
     RECT  2.16 25.245 22.464 25.38 ;
     RECT  23.328 25.245 23.436 25.38 ;
     RECT  23.976 25.245 27.27 25.38 ;
     RECT  27.864 25.245 41.04 25.38 ;
     RECT  2.16 25.38 16.902 25.515 ;
     RECT  17.334 25.38 23.058 25.515 ;
     RECT  23.598 25.38 25.812 25.515 ;
     RECT  26.244 25.38 41.04 25.515 ;
     RECT  2.16 25.785 16.47 25.92 ;
     RECT  17.064 25.785 22.95 25.92 ;
     RECT  23.49 25.785 23.976 25.92 ;
     RECT  24.462 25.785 41.04 25.92 ;
     RECT  2.16 25.92 23.76 26.055 ;
     RECT  24.192 25.92 41.04 26.055 ;
     RECT  2.16 26.325 16.038 26.46 ;
     RECT  16.47 26.325 30.24 26.46 ;
     RECT  30.402 26.325 41.04 26.46 ;
     RECT  2.16 26.46 10.098 26.595 ;
     RECT  10.962 26.46 16.092 26.595 ;
     RECT  16.686 26.46 17.55 26.595 ;
     RECT  18.414 26.46 24.084 26.595 ;
     RECT  24.462 26.46 25.542 26.595 ;
     RECT  26.298 26.46 28.242 26.595 ;
     RECT  28.674 26.46 29.376 26.595 ;
     RECT  29.916 26.46 31.482 26.595 ;
     RECT  31.914 26.46 41.04 26.595 ;
     RECT  2.16 26.865 24.948 27 ;
     RECT  25.272 26.865 30.294 27 ;
     RECT  30.618 26.865 31.266 27 ;
     RECT  31.698 26.865 41.04 27 ;
     RECT  2.16 27 11.07 27.135 ;
     RECT  11.61 27 24.624 27.135 ;
     RECT  25.056 27 41.04 27.135 ;
     RECT  2.16 27.405 20.088 27.54 ;
     RECT  20.628 27.405 30.348 27.54 ;
     RECT  31.266 27.405 41.04 27.54 ;
     RECT  2.16 27.54 13.23 27.675 ;
     RECT  13.662 27.54 41.04 27.675 ;
     RECT  2.16 27.945 41.04 28.08 ;
     RECT  2.16 28.08 10.26 28.215 ;
     RECT  10.638 28.08 13.122 28.215 ;
     RECT  13.554 28.08 41.04 28.215 ;
     RECT  2.16 28.485 11.124 28.62 ;
     RECT  11.556 28.485 41.04 28.62 ;
     RECT  2.16 28.62 9.018 28.755 ;
     RECT  9.396 28.62 13.284 28.755 ;
     RECT  13.824 28.62 41.04 28.755 ;
     RECT  2.16 29.025 30.24 29.16 ;
     RECT  30.51 29.025 41.04 29.16 ;
     RECT  2.16 29.16 13.176 29.295 ;
     RECT  13.554 29.16 41.04 29.295 ;
     RECT  2.16 29.565 12.798 29.7 ;
     RECT  14.256 29.565 41.04 29.7 ;
     RECT  2.16 29.7 13.608 29.835 ;
     RECT  14.148 29.7 14.958 29.835 ;
     RECT  15.282 29.7 28.566 29.835 ;
     RECT  28.89 29.7 41.04 29.835 ;
     RECT  2.16 30.105 15.12 30.24 ;
     RECT  15.444 30.105 16.038 30.24 ;
     RECT  16.47 30.105 29.862 30.24 ;
     RECT  30.402 30.105 41.04 30.24 ;
     RECT  2.16 30.24 13.5 30.375 ;
     RECT  13.824 30.24 29.43 30.375 ;
     RECT  29.862 30.24 41.04 30.375 ;
     RECT  2.16 30.645 29.43 30.78 ;
     RECT  30.186 30.645 41.04 30.78 ;
     RECT  2.16 30.78 29.322 30.915 ;
     RECT  29.862 30.78 41.04 30.915 ;
     RECT  2.16 31.185 41.04 31.32 ;
     RECT  2.16 31.32 13.878 31.455 ;
     RECT  14.418 31.32 41.04 31.455 ;
     RECT  2.16 31.725 41.04 31.995 ;
     RECT  2.16 32.265 41.04 32.535 ;
     RECT  2.16 32.805 19.926 32.94 ;
     RECT  20.196 32.805 41.04 32.94 ;
     RECT  2.16 32.94 41.04 33.075 ;
     RECT  2.16 33.345 41.04 33.48 ;
     RECT  2.16 33.48 23.004 33.615 ;
     RECT  23.436 33.48 41.04 33.615 ;
     RECT  14.688 33.885 41.04 34.02 ;
     RECT  2.16 33.885 14.364 34.155 ;
     RECT  14.796 34.02 18.306 34.155 ;
     RECT  18.63 34.02 18.738 34.155 ;
     RECT  19.17 34.02 41.04 34.155 ;
     RECT  2.16 34.425 12.852 34.56 ;
     RECT  13.392 34.425 13.5 34.56 ;
     RECT  13.824 34.425 23.166 34.56 ;
     RECT  23.598 34.425 41.04 34.56 ;
     RECT  2.16 34.56 14.418 34.695 ;
     RECT  14.958 34.56 18.576 34.695 ;
     RECT  18.9 34.56 25.704 34.695 ;
     RECT  26.028 34.56 41.04 34.695 ;
     RECT  2.16 34.965 13.014 35.1 ;
     RECT  13.662 34.965 15.012 35.1 ;
     RECT  15.552 34.965 18.036 35.1 ;
     RECT  18.468 34.965 22.842 35.1 ;
     RECT  23.274 34.965 41.04 35.1 ;
     RECT  2.16 35.1 12.906 35.235 ;
     RECT  13.446 35.1 23.058 35.235 ;
     RECT  23.598 35.1 41.04 35.235 ;
     RECT  2.16 35.505 41.04 35.64 ;
     RECT  2.16 35.64 18.576 35.775 ;
     RECT  19.656 35.64 41.04 35.775 ;
     RECT  2.16 36.045 22.896 36.18 ;
     RECT  23.328 36.045 41.04 36.18 ;
     RECT  2.16 36.18 20.358 36.315 ;
     RECT  21.06 36.18 22.68 36.315 ;
     RECT  23.112 36.18 41.04 36.315 ;
     RECT  2.16 36.585 14.364 36.72 ;
     RECT  14.796 36.585 22.572 36.72 ;
     RECT  23.22 36.585 41.04 36.72 ;
     RECT  2.16 36.72 14.85 36.855 ;
     RECT  15.39 36.72 41.04 36.855 ;
     RECT  2.16 37.125 14.094 37.26 ;
     RECT  14.634 37.125 22.572 37.26 ;
     RECT  22.896 37.125 41.04 37.26 ;
     RECT  2.16 37.26 41.04 37.395 ;
     RECT  2.16 37.665 41.04 37.935 ;
     RECT  2.16 38.205 41.04 38.475 ;
     RECT  2.16 38.745 41.04 39.015 ;
     RECT  2.16 39.285 41.04 39.555 ;
     RECT  2.16 39.825 41.04 40.095 ;
     RECT  2.16 40.365 41.04 40.635 ;
     RECT  2.16 40.905 41.04 41.04 ;
    LAYER RVTP ;
     RECT  2.16 2.295 41.04 2.565 ;
     RECT  2.16 2.835 41.04 3.105 ;
     RECT  2.16 3.375 41.04 3.645 ;
     RECT  2.16 3.915 41.04 4.185 ;
     RECT  2.16 4.455 41.04 4.725 ;
     RECT  2.16 4.995 41.04 5.265 ;
     RECT  2.16 5.535 41.04 5.805 ;
     RECT  2.16 6.075 41.04 6.345 ;
     RECT  2.16 6.615 41.04 6.885 ;
     RECT  2.16 7.155 41.04 7.425 ;
     RECT  2.16 7.695 41.04 7.965 ;
     RECT  2.16 8.235 41.04 8.505 ;
     RECT  2.16 8.775 41.04 9.045 ;
     RECT  2.16 9.315 41.04 9.585 ;
     RECT  2.16 9.855 41.04 10.125 ;
     RECT  2.16 10.395 41.04 10.665 ;
     RECT  2.16 10.935 41.04 11.205 ;
     RECT  2.16 11.475 41.04 11.745 ;
     RECT  2.16 12.015 41.04 12.285 ;
     RECT  2.16 12.555 41.04 12.825 ;
     RECT  2.16 13.095 41.04 13.365 ;
     RECT  2.16 13.635 41.04 13.905 ;
     RECT  2.16 14.175 41.04 14.31 ;
     RECT  2.16 14.31 13.23 14.445 ;
     RECT  13.77 14.31 41.04 14.445 ;
     RECT  2.16 14.715 13.338 14.85 ;
     RECT  13.77 14.715 41.04 14.85 ;
     RECT  2.16 14.85 41.04 14.985 ;
     RECT  2.16 15.255 12.582 15.39 ;
     RECT  13.446 15.255 41.04 15.39 ;
     RECT  2.16 15.39 41.04 15.525 ;
     RECT  2.16 15.795 41.04 16.065 ;
     RECT  2.16 16.335 41.04 16.605 ;
     RECT  2.16 16.875 41.04 17.145 ;
     RECT  2.16 17.415 41.04 17.685 ;
     RECT  2.16 17.955 41.04 18.09 ;
     RECT  2.16 18.09 10.908 18.225 ;
     RECT  11.232 18.09 11.286 18.225 ;
     RECT  11.61 18.09 41.04 18.225 ;
     RECT  2.16 18.495 10.962 18.63 ;
     RECT  11.502 18.495 41.04 18.63 ;
     RECT  2.16 18.63 11.718 18.765 ;
     RECT  12.528 18.63 41.04 18.765 ;
     RECT  2.16 19.035 41.04 19.305 ;
     RECT  2.16 19.575 14.364 19.71 ;
     RECT  14.796 19.575 14.904 19.71 ;
     RECT  15.282 19.575 41.04 19.71 ;
     RECT  2.16 19.71 15.012 19.845 ;
     RECT  15.336 19.71 41.04 19.845 ;
     RECT  2.16 20.115 22.41 20.25 ;
     RECT  22.95 20.115 41.04 20.25 ;
     RECT  2.16 20.25 17.496 20.385 ;
     RECT  17.982 20.25 21.978 20.385 ;
     RECT  22.302 20.25 41.04 20.385 ;
     RECT  2.16 20.655 16.254 20.79 ;
     RECT  16.578 20.655 22.248 20.79 ;
     RECT  23.004 20.655 41.04 20.79 ;
     RECT  2.16 20.79 14.364 20.925 ;
     RECT  14.904 20.79 15.93 20.925 ;
     RECT  16.794 20.79 41.04 20.925 ;
     RECT  2.16 21.195 15.93 21.33 ;
     RECT  16.578 21.195 20.088 21.33 ;
     RECT  20.574 21.195 20.736 21.33 ;
     RECT  21.114 21.195 41.04 21.33 ;
     RECT  2.16 21.33 41.04 21.465 ;
     RECT  2.16 21.735 15.066 21.87 ;
     RECT  15.498 21.735 17.28 21.87 ;
     RECT  17.712 21.735 41.04 21.87 ;
     RECT  2.16 21.87 14.472 22.005 ;
     RECT  15.228 21.87 17.496 22.005 ;
     RECT  18.09 21.87 22.14 22.005 ;
     RECT  22.68 21.87 41.04 22.005 ;
     RECT  2.16 22.275 15.066 22.41 ;
     RECT  15.498 22.275 41.04 22.41 ;
     RECT  2.16 22.41 41.04 22.545 ;
     RECT  2.16 22.815 41.04 23.085 ;
     RECT  2.16 23.355 9.774 23.49 ;
     RECT  10.422 23.355 20.466 23.49 ;
     RECT  20.898 23.355 41.04 23.49 ;
     RECT  2.16 23.49 41.04 23.625 ;
     RECT  2.16 23.895 20.034 24.03 ;
     RECT  20.574 23.895 41.04 24.03 ;
     RECT  2.16 24.03 20.142 24.165 ;
     RECT  20.466 24.03 27.972 24.165 ;
     RECT  28.782 24.03 41.04 24.165 ;
     RECT  2.16 24.435 9.396 24.57 ;
     RECT  10.206 24.435 22.14 24.57 ;
     RECT  23.004 24.435 41.04 24.57 ;
     RECT  2.16 24.57 17.604 24.705 ;
     RECT  18.576 24.57 20.412 24.705 ;
     RECT  20.736 24.57 25.758 24.705 ;
     RECT  26.136 24.57 30.456 24.705 ;
     RECT  30.834 24.57 41.04 24.705 ;
     RECT  2.16 24.975 17.442 25.11 ;
     RECT  17.982 24.975 41.04 25.11 ;
     RECT  2.16 25.11 22.464 25.245 ;
     RECT  23.328 25.11 23.436 25.245 ;
     RECT  23.976 25.11 27.27 25.245 ;
     RECT  27.864 25.11 41.04 25.245 ;
     RECT  2.16 25.515 16.902 25.65 ;
     RECT  17.334 25.515 23.058 25.65 ;
     RECT  23.598 25.515 25.812 25.65 ;
     RECT  26.244 25.515 41.04 25.65 ;
     RECT  2.16 25.65 16.47 25.785 ;
     RECT  17.064 25.65 22.95 25.785 ;
     RECT  23.49 25.65 23.976 25.785 ;
     RECT  24.462 25.65 41.04 25.785 ;
     RECT  2.16 26.055 23.76 26.19 ;
     RECT  24.192 26.055 41.04 26.19 ;
     RECT  2.16 26.19 16.038 26.325 ;
     RECT  16.47 26.19 30.24 26.325 ;
     RECT  30.402 26.19 41.04 26.325 ;
     RECT  2.16 26.595 10.098 26.73 ;
     RECT  10.962 26.595 16.092 26.73 ;
     RECT  16.686 26.595 17.55 26.73 ;
     RECT  18.414 26.595 24.084 26.73 ;
     RECT  24.462 26.595 25.542 26.73 ;
     RECT  26.298 26.595 28.242 26.73 ;
     RECT  28.674 26.595 29.376 26.73 ;
     RECT  29.916 26.595 31.482 26.73 ;
     RECT  31.914 26.595 41.04 26.73 ;
     RECT  2.16 26.73 24.948 26.865 ;
     RECT  25.272 26.73 30.294 26.865 ;
     RECT  30.618 26.73 31.266 26.865 ;
     RECT  31.698 26.73 41.04 26.865 ;
     RECT  2.16 27.135 11.07 27.27 ;
     RECT  11.61 27.135 24.624 27.27 ;
     RECT  25.056 27.135 41.04 27.27 ;
     RECT  2.16 27.27 20.088 27.405 ;
     RECT  20.628 27.27 30.348 27.405 ;
     RECT  31.266 27.27 41.04 27.405 ;
     RECT  2.16 27.675 13.23 27.81 ;
     RECT  13.662 27.675 41.04 27.81 ;
     RECT  2.16 27.81 41.04 27.945 ;
     RECT  2.16 28.215 10.26 28.35 ;
     RECT  10.638 28.215 13.122 28.35 ;
     RECT  13.554 28.215 41.04 28.35 ;
     RECT  2.16 28.35 11.124 28.485 ;
     RECT  11.556 28.35 41.04 28.485 ;
     RECT  2.16 28.755 9.018 28.89 ;
     RECT  9.396 28.755 13.284 28.89 ;
     RECT  13.824 28.755 41.04 28.89 ;
     RECT  2.16 28.89 30.24 29.025 ;
     RECT  30.51 28.89 41.04 29.025 ;
     RECT  2.16 29.295 13.176 29.43 ;
     RECT  13.554 29.295 41.04 29.43 ;
     RECT  2.16 29.43 12.798 29.565 ;
     RECT  14.256 29.43 41.04 29.565 ;
     RECT  2.16 29.835 13.608 29.97 ;
     RECT  14.148 29.835 14.958 29.97 ;
     RECT  15.282 29.835 28.566 29.97 ;
     RECT  28.89 29.835 41.04 29.97 ;
     RECT  2.16 29.97 15.12 30.105 ;
     RECT  15.444 29.97 16.038 30.105 ;
     RECT  16.47 29.97 29.862 30.105 ;
     RECT  30.402 29.97 41.04 30.105 ;
     RECT  2.16 30.375 13.5 30.51 ;
     RECT  13.824 30.375 29.43 30.51 ;
     RECT  29.862 30.375 41.04 30.51 ;
     RECT  2.16 30.51 29.43 30.645 ;
     RECT  30.186 30.51 41.04 30.645 ;
     RECT  2.16 30.915 29.322 31.05 ;
     RECT  29.862 30.915 41.04 31.05 ;
     RECT  2.16 31.05 41.04 31.185 ;
     RECT  2.16 31.455 13.878 31.59 ;
     RECT  14.418 31.455 41.04 31.59 ;
     RECT  2.16 31.59 41.04 31.725 ;
     RECT  2.16 31.995 41.04 32.265 ;
     RECT  2.16 32.535 41.04 32.67 ;
     RECT  2.16 32.67 19.926 32.805 ;
     RECT  20.196 32.67 41.04 32.805 ;
     RECT  2.16 33.075 41.04 33.345 ;
     RECT  2.16 33.615 23.004 33.75 ;
     RECT  23.436 33.615 41.04 33.75 ;
     RECT  2.16 33.75 14.364 33.885 ;
     RECT  14.688 33.75 41.04 33.885 ;
     RECT  2.16 34.155 14.364 34.29 ;
     RECT  14.796 34.155 18.306 34.29 ;
     RECT  18.63 34.155 18.738 34.29 ;
     RECT  19.17 34.155 41.04 34.29 ;
     RECT  2.16 34.29 12.852 34.425 ;
     RECT  13.392 34.29 13.5 34.425 ;
     RECT  13.824 34.29 23.166 34.425 ;
     RECT  23.598 34.29 41.04 34.425 ;
     RECT  2.16 34.695 14.418 34.83 ;
     RECT  14.958 34.695 18.576 34.83 ;
     RECT  18.9 34.695 25.704 34.83 ;
     RECT  26.028 34.695 41.04 34.83 ;
     RECT  2.16 34.83 13.014 34.965 ;
     RECT  13.662 34.83 15.012 34.965 ;
     RECT  15.552 34.83 18.036 34.965 ;
     RECT  18.468 34.83 22.842 34.965 ;
     RECT  23.274 34.83 41.04 34.965 ;
     RECT  2.16 35.235 12.906 35.37 ;
     RECT  13.446 35.235 23.058 35.37 ;
     RECT  23.598 35.235 41.04 35.37 ;
     RECT  2.16 35.37 41.04 35.505 ;
     RECT  2.16 35.775 18.576 35.91 ;
     RECT  19.656 35.775 41.04 35.91 ;
     RECT  2.16 35.91 22.896 36.045 ;
     RECT  23.328 35.91 41.04 36.045 ;
     RECT  2.16 36.315 20.358 36.45 ;
     RECT  21.06 36.315 22.68 36.45 ;
     RECT  23.112 36.315 41.04 36.45 ;
     RECT  2.16 36.45 14.364 36.585 ;
     RECT  14.796 36.45 22.572 36.585 ;
     RECT  23.22 36.45 41.04 36.585 ;
     RECT  2.16 36.855 14.85 36.99 ;
     RECT  15.39 36.855 41.04 36.99 ;
     RECT  2.16 36.99 14.094 37.125 ;
     RECT  14.634 36.99 22.572 37.125 ;
     RECT  22.896 36.99 41.04 37.125 ;
     RECT  2.16 37.395 41.04 37.665 ;
     RECT  2.16 37.935 41.04 38.205 ;
     RECT  2.16 38.475 41.04 38.745 ;
     RECT  2.16 39.015 41.04 39.285 ;
     RECT  2.16 39.555 41.04 39.825 ;
     RECT  2.16 40.095 41.04 40.365 ;
     RECT  2.16 40.635 41.04 40.905 ;
    LAYER M1 ;
     RECT  2.16 2.151 41.04 41.049 ;
    LAYER M2 ;
     RECT  0.103 9.666 0.139 9.684 ;
     RECT  0.139 8.982 0.239 10.224 ;
     RECT  0.239 8.982 0.283 10.188 ;
     RECT  0.103 14.724 0.283 14.742 ;
     RECT  0.175 15.498 0.283 15.516 ;
     RECT  0.283 14.724 0.311 15.516 ;
     RECT  0.311 14.724 0.355 14.814 ;
     RECT  0.283 8.82 0.383 10.188 ;
     RECT  0.355 14.22 0.383 14.814 ;
     RECT  0.211 7.902 0.499 7.92 ;
     RECT  0.499 7.668 0.535 7.92 ;
     RECT  0.103 23.832 0.535 23.85 ;
     RECT  0.535 15.768 1.147 15.786 ;
     RECT  1.147 15.768 1.175 15.858 ;
     RECT  1.723 2.502 2.16 2.52 ;
     RECT  0.535 3.96 2.16 3.978 ;
     RECT  0.175 6.12 2.16 6.138 ;
     RECT  0.535 7.398 2.16 7.92 ;
     RECT  0.383 8.82 2.16 8.838 ;
     RECT  0.383 9.666 2.16 10.188 ;
     RECT  1.183 12.024 2.16 12.042 ;
     RECT  0.383 14.22 2.16 14.238 ;
     RECT  1.175 15.84 2.16 15.858 ;
     RECT  0.103 16.812 2.16 16.83 ;
     RECT  0.535 20.97 2.16 20.988 ;
     RECT  0.535 22.086 2.16 22.104 ;
     RECT  0.535 23.832 2.16 23.922 ;
     RECT  2.16 2.151 3.019 41.049 ;
     RECT  3.019 2.106 3.775 41.049 ;
     RECT  3.775 2.034 4.739 41.049 ;
     RECT  4.739 2.106 6.187 41.049 ;
     RECT  6.187 2.034 7.187 41.049 ;
     RECT  7.187 2.106 10.031 41.049 ;
     RECT  10.291 1.224 10.363 1.242 ;
     RECT  10.363 1.152 10.499 1.242 ;
     RECT  10.499 1.224 10.535 1.242 ;
     RECT  11.947 0.531 12.163 0.549 ;
     RECT  12.163 0.036 13.127 0.549 ;
     RECT  10.031 2.151 14.251 41.049 ;
     RECT  14.251 1.926 15.791 41.049 ;
     RECT  13.127 0.036 16.547 0.09 ;
     RECT  16.547 0.036 16.691 0.054 ;
     RECT  16.663 1.152 16.799 1.17 ;
     RECT  15.791 1.998 16.907 41.049 ;
     RECT  16.907 2.151 33.871 41.049 ;
     RECT  33.871 2.151 34.763 41.094 ;
     RECT  34.763 2.151 41.04 41.049 ;
     RECT  41.04 19.35 41.567 24.894 ;
     RECT  41.567 19.35 41.603 22.032 ;
     RECT  41.567 23.058 41.603 24.084 ;
     RECT  41.603 19.35 41.639 20.376 ;
     RECT  41.04 8.316 42.143 18.594 ;
     RECT  41.603 21.168 42.143 22.032 ;
     RECT  42.143 9.666 42.179 10.224 ;
     RECT  42.143 11.556 42.179 16.092 ;
     RECT  42.143 17.316 42.179 18.594 ;
     RECT  41.639 19.35 42.179 20.304 ;
     RECT  42.143 21.168 42.179 21.186 ;
     RECT  42.143 22.014 42.179 22.032 ;
     RECT  41.603 24.066 42.179 24.084 ;
     RECT  42.143 8.316 42.215 8.694 ;
     RECT  42.179 11.556 42.215 12.042 ;
     RECT  42.179 12.996 42.215 15.822 ;
     RECT  42.179 17.424 42.215 18.594 ;
     RECT  42.215 8.316 42.251 8.532 ;
     RECT  42.215 17.424 42.251 18.522 ;
     RECT  42.251 17.424 42.899 18.324 ;
     RECT  42.215 12.996 42.943 13.194 ;
     RECT  42.899 17.586 42.979 18.324 ;
     RECT  42.179 19.35 42.979 19.53 ;
     RECT  42.979 17.586 43.007 19.53 ;
     RECT  42.215 15.426 43.015 15.822 ;
     RECT  42.943 12.906 43.043 13.194 ;
     RECT  43.015 15.426 43.043 15.894 ;
     RECT  42.179 20.286 43.043 20.304 ;
     RECT  42.179 10.206 43.079 10.224 ;
     RECT  43.007 17.586 43.079 19.404 ;
     RECT  43.015 21.546 43.087 21.564 ;
     RECT  42.251 8.514 43.115 8.532 ;
     RECT  43.043 13.068 43.115 13.194 ;
     RECT  43.043 15.804 43.115 15.894 ;
     RECT  43.079 18.126 43.115 18.144 ;
     RECT  43.079 19.35 43.115 19.368 ;
     RECT  43.087 21.546 43.115 22.149 ;
     RECT  41.603 23.058 43.115 23.076 ;
     RECT  43.115 22.131 43.187 22.149 ;
     RECT  41.567 24.876 43.187 24.894 ;
    LAYER M3 ;
     RECT  12.168 0.031 12.186 0.043 ;
     RECT  16.668 0.031 16.686 0.043 ;
     RECT  16.668 0.043 16.974 0.067 ;
     RECT  16.524 0.067 16.974 0.091 ;
     RECT  10.008 0.091 10.026 0.235 ;
     RECT  12.168 0.043 12.87 0.283 ;
     RECT  8.28 0.091 8.298 0.317 ;
     RECT  12.168 0.283 13.158 0.427 ;
     RECT  12.168 0.427 13.374 0.52 ;
     RECT  11.952 0.52 13.374 0.557 ;
     RECT  9.288 0.235 10.53 0.571 ;
     RECT  3.816 1.003 3.834 1.195 ;
     RECT  9.216 0.571 10.53 1.247 ;
     RECT  3.168 1.195 3.834 1.291 ;
     RECT  12.456 0.557 13.374 1.387 ;
     RECT  3.168 1.291 3.87 1.483 ;
     RECT  7.308 0.523 7.326 1.723 ;
     RECT  9.216 1.247 10.494 1.723 ;
     RECT  12.456 1.387 13.626 1.723 ;
     RECT  7.308 1.723 8.262 1.771 ;
     RECT  16.02 0.091 16.974 1.921 ;
     RECT  1.728 1.099 1.746 1.963 ;
     RECT  2.556 1.483 3.87 1.963 ;
     RECT  11.34 1.723 14.274 1.993 ;
     RECT  15.768 1.921 16.974 2.011 ;
     RECT  5.94 0.475 5.958 2.029 ;
     RECT  7.272 1.771 8.262 2.029 ;
     RECT  4.716 2.029 4.734 2.059 ;
     RECT  5.94 2.029 6.21 2.059 ;
     RECT  7.164 2.029 8.262 2.059 ;
     RECT  11.34 1.993 14.922 2.059 ;
     RECT  11.304 2.059 14.922 2.065 ;
     RECT  15.768 2.011 17.01 2.065 ;
     RECT  1.728 1.963 3.87 2.101 ;
     RECT  4.716 2.059 5.022 2.101 ;
     RECT  5.94 2.059 8.262 2.101 ;
     RECT  9.072 1.723 10.494 2.101 ;
     RECT  0.18 2.011 0.198 2.155 ;
     RECT  1.728 2.101 5.022 2.191 ;
     RECT  5.94 2.101 10.494 2.191 ;
     RECT  11.304 2.065 17.01 2.191 ;
     RECT  1.728 2.191 5.202 2.371 ;
     RECT  5.94 2.191 17.01 2.371 ;
     RECT  18.615 2.143 18.705 2.413 ;
     RECT  24.015 2.143 24.105 2.413 ;
     RECT  29.415 2.143 29.505 2.413 ;
     RECT  34.815 2.143 34.905 2.413 ;
     RECT  40.215 2.143 40.305 2.413 ;
     RECT  1.728 2.371 17.262 2.525 ;
     RECT  2.268 2.525 17.262 2.633 ;
     RECT  0.18 2.155 0.342 2.861 ;
     RECT  0.216 2.861 0.342 3.053 ;
     RECT  2.268 2.633 17.226 3.209 ;
     RECT  24.015 2.413 24.297 3.307 ;
     RECT  2.304 3.209 17.226 3.389 ;
     RECT  0.216 3.053 0.234 3.739 ;
     RECT  0.18 3.739 0.234 3.787 ;
     RECT  1.152 3.739 1.17 3.869 ;
     RECT  0.18 3.787 0.342 3.917 ;
     RECT  2.304 3.389 17.118 4.225 ;
     RECT  24.015 3.307 24.894 4.351 ;
     RECT  2.304 4.225 17.406 4.459 ;
     RECT  21.276 4.363 21.294 4.891 ;
     RECT  0.54 3.955 0.558 4.973 ;
     RECT  2.268 4.459 17.406 5.071 ;
     RECT  2.268 5.071 17.55 5.161 ;
     RECT  2.268 5.161 17.622 5.341 ;
     RECT  18.615 2.413 18.897 5.431 ;
     RECT  18.615 5.431 19.242 5.461 ;
     RECT  2.268 5.341 17.694 5.539 ;
     RECT  18.432 5.461 19.242 5.539 ;
     RECT  21.276 4.891 21.51 5.611 ;
     RECT  0.144 5.275 0.162 5.645 ;
     RECT  2.268 5.539 19.242 5.765 ;
     RECT  23.4 4.351 24.894 5.773 ;
     RECT  18.615 5.765 19.242 5.873 ;
     RECT  29.415 2.413 29.697 5.881 ;
     RECT  23.364 5.773 24.894 5.971 ;
     RECT  28.584 5.881 29.697 5.971 ;
     RECT  30.996 5.881 31.014 5.971 ;
     RECT  2.268 5.765 17.73 5.999 ;
     RECT  2.268 5.999 17.478 6.035 ;
     RECT  25.92 3.991 25.938 6.043 ;
     RECT  30.78 5.971 31.014 6.079 ;
     RECT  25.92 6.043 26.514 6.115 ;
     RECT  30.42 6.079 31.014 6.115 ;
     RECT  25.92 6.115 26.55 6.151 ;
     RECT  27.324 6.115 27.342 6.151 ;
     RECT  28.512 5.971 29.697 6.151 ;
     RECT  30.42 6.115 31.302 6.151 ;
     RECT  2.268 6.035 17.298 6.269 ;
     RECT  20.772 5.611 21.51 6.269 ;
     RECT  25.92 6.151 29.697 6.269 ;
     RECT  22.608 4.651 22.626 6.277 ;
     RECT  23.364 5.971 25.074 6.277 ;
     RECT  25.92 6.269 27.738 6.277 ;
     RECT  2.268 6.269 17.01 6.305 ;
     RECT  21.096 6.269 21.51 6.385 ;
     RECT  30.42 6.151 31.626 6.385 ;
     RECT  0.18 6.091 0.342 6.413 ;
     RECT  32.616 5.881 32.634 6.421 ;
     RECT  28.512 6.269 29.697 6.511 ;
     RECT  30.42 6.385 31.698 6.511 ;
     RECT  21.096 6.385 21.618 6.583 ;
     RECT  28.512 6.511 31.698 6.583 ;
     RECT  32.616 6.421 32.706 6.583 ;
     RECT  21.096 6.583 21.834 6.619 ;
     RECT  22.608 6.277 27.738 6.619 ;
     RECT  28.512 6.583 32.706 6.691 ;
     RECT  28.512 6.691 32.85 6.817 ;
     RECT  33.624 6.385 33.642 6.817 ;
     RECT  2.304 6.305 17.01 7.051 ;
     RECT  0.144 6.475 0.162 7.133 ;
     RECT  18.615 5.873 19.098 7.195 ;
     RECT  20.088 7.051 20.106 7.231 ;
     RECT  21.096 6.619 27.738 7.231 ;
     RECT  2.268 7.051 17.19 7.259 ;
     RECT  20.088 7.231 27.738 7.385 ;
     RECT  21.276 7.385 27.738 7.465 ;
     RECT  28.512 6.817 33.642 7.465 ;
     RECT  21.276 7.465 33.642 7.483 ;
     RECT  2.268 7.259 17.118 7.529 ;
     RECT  18.54 7.195 19.098 7.723 ;
     RECT  0.324 7.393 0.558 7.853 ;
     RECT  0.324 7.853 0.522 7.897 ;
     RECT  21.276 7.483 33.786 7.933 ;
     RECT  40.215 2.413 40.497 7.933 ;
     RECT  0.216 7.897 0.522 8.299 ;
     RECT  0.144 8.299 0.522 8.429 ;
     RECT  20.088 7.385 20.538 8.509 ;
     RECT  21.276 7.933 34.074 8.509 ;
     RECT  2.304 7.529 17.118 8.537 ;
     RECT  18.144 7.723 19.098 8.539 ;
     RECT  20.088 8.509 34.074 8.539 ;
     RECT  42.228 8.311 42.246 8.671 ;
     RECT  42.192 8.671 42.246 9.013 ;
     RECT  40.032 7.933 41.022 9.085 ;
     RECT  0.144 8.429 0.378 9.101 ;
     RECT  2.34 8.537 17.118 9.121 ;
     RECT  39.708 9.085 41.022 9.355 ;
     RECT  39.636 9.355 41.022 9.391 ;
     RECT  2.34 9.121 17.37 9.451 ;
     RECT  34.815 2.413 35.097 9.517 ;
     RECT  0.144 9.101 0.342 9.661 ;
     RECT  18.144 8.539 34.074 9.661 ;
     RECT  18.108 9.661 34.074 9.823 ;
     RECT  34.815 9.517 35.19 9.823 ;
     RECT  42.12 9.013 42.246 9.823 ;
     RECT  38.268 9.751 38.286 9.931 ;
     RECT  36.072 9.979 36.09 10.049 ;
     RECT  39.564 9.391 41.022 10.061 ;
     RECT  18.108 9.823 35.19 10.129 ;
     RECT  0.108 9.661 0.342 10.157 ;
     RECT  0.144 10.157 0.342 10.165 ;
     RECT  38.268 9.931 38.358 10.201 ;
     RECT  39.564 10.061 40.986 10.201 ;
     RECT  43.092 8.509 43.11 10.201 ;
     RECT  43.056 10.201 43.11 10.253 ;
     RECT  2.304 9.451 17.37 10.291 ;
     RECT  18.108 10.129 35.694 10.291 ;
     RECT  2.304 10.291 35.694 10.319 ;
     RECT  37.008 10.201 37.17 10.471 ;
     RECT  0.144 10.165 0.558 10.541 ;
     RECT  36.468 10.471 37.17 10.741 ;
     RECT  38.268 10.201 40.986 10.741 ;
     RECT  0.144 10.541 0.342 10.829 ;
     RECT  42.084 9.823 42.246 10.925 ;
     RECT  36.468 10.741 40.986 10.939 ;
     RECT  36.252 10.939 40.986 10.975 ;
     RECT  42.084 10.925 42.21 11.021 ;
     RECT  2.304 10.319 35.514 11.101 ;
     RECT  36.252 10.975 41.058 11.101 ;
     RECT  43.092 10.253 43.11 11.117 ;
     RECT  0.216 10.829 0.342 11.213 ;
     RECT  0.216 11.213 0.234 11.309 ;
     RECT  2.304 11.101 41.058 11.851 ;
     RECT  1.296 11.755 1.314 11.947 ;
     RECT  1.188 11.947 1.314 11.981 ;
     RECT  1.188 11.981 1.206 12.047 ;
     RECT  2.268 11.851 41.058 12.235 ;
     RECT  42.156 11.021 42.21 12.235 ;
     RECT  2.268 12.235 42.21 12.461 ;
     RECT  0.324 12.427 0.342 12.571 ;
     RECT  0.216 12.571 0.342 12.619 ;
     RECT  2.268 12.461 40.77 12.829 ;
     RECT  43.056 12.811 43.074 12.859 ;
     RECT  42.948 12.859 43.074 12.929 ;
     RECT  43.02 12.929 43.074 12.941 ;
     RECT  41.58 12.461 42.21 12.991 ;
     RECT  43.056 12.941 43.074 13.063 ;
     RECT  43.056 13.063 43.11 13.172 ;
     RECT  43.092 13.172 43.11 13.229 ;
     RECT  2.232 12.829 40.77 13.405 ;
     RECT  41.58 12.991 42.246 13.405 ;
     RECT  0.144 12.619 0.342 14.215 ;
     RECT  0.144 14.215 0.378 14.539 ;
     RECT  0.144 14.539 0.414 14.669 ;
     RECT  0.144 14.669 0.378 14.719 ;
     RECT  0.108 14.719 0.378 14.765 ;
     RECT  0.144 14.765 0.378 14.819 ;
     RECT  2.232 13.405 42.246 14.909 ;
     RECT  1.152 14.971 1.17 15.019 ;
     RECT  2.304 14.909 42.246 15.251 ;
     RECT  1.152 15.019 1.278 15.293 ;
     RECT  43.092 15.403 43.11 15.421 ;
     RECT  0.144 14.819 0.306 15.763 ;
     RECT  1.152 15.293 1.17 15.763 ;
     RECT  42.192 15.251 42.246 15.791 ;
     RECT  0.144 15.763 1.17 15.863 ;
     RECT  43.02 15.421 43.11 15.917 ;
     RECT  0.144 15.863 0.558 16.013 ;
     RECT  2.304 15.251 40.95 16.375 ;
     RECT  42.084 16.033 42.174 16.375 ;
     RECT  2.304 16.375 42.174 16.529 ;
     RECT  2.304 16.529 40.734 16.565 ;
     RECT  0.144 16.013 0.162 16.807 ;
     RECT  43.02 15.917 43.038 17.131 ;
     RECT  2.304 16.565 40.626 17.221 ;
     RECT  0.108 16.807 0.162 17.227 ;
     RECT  41.616 16.529 42.174 17.275 ;
     RECT  43.02 17.131 43.11 17.275 ;
     RECT  41.58 17.275 42.174 17.323 ;
     RECT  42.948 17.275 43.11 17.323 ;
     RECT  0.108 17.227 0.45 17.405 ;
     RECT  0.108 17.405 0.378 17.453 ;
     RECT  41.58 17.323 43.11 17.483 ;
     RECT  42.084 17.483 43.11 17.519 ;
     RECT  2.268 17.221 40.626 17.609 ;
     RECT  42.12 17.519 43.11 17.609 ;
     RECT  42.192 17.609 43.11 17.645 ;
     RECT  36.144 17.609 40.626 17.707 ;
     RECT  0.108 17.453 0.342 17.933 ;
     RECT  42.984 17.645 43.11 18.149 ;
     RECT  2.268 17.609 35.37 18.427 ;
     RECT  36.144 17.707 41.022 18.427 ;
     RECT  42.192 17.645 42.21 18.499 ;
     RECT  0.144 17.933 0.342 18.509 ;
     RECT  42.192 18.499 42.246 18.599 ;
     RECT  42.228 18.599 42.246 18.605 ;
     RECT  2.268 18.427 41.022 18.725 ;
     RECT  37.044 18.725 41.022 19.031 ;
     RECT  42.984 18.149 43.074 19.051 ;
     RECT  2.268 18.725 36.27 19.195 ;
     RECT  42.948 19.051 43.074 19.345 ;
     RECT  0.324 18.509 0.342 19.373 ;
     RECT  42.948 19.345 43.11 19.499 ;
     RECT  42.984 19.499 43.11 19.535 ;
     RECT  42.156 19.813 42.174 19.885 ;
     RECT  0.144 19.771 0.162 19.949 ;
     RECT  2.232 19.195 36.27 20.011 ;
     RECT  37.044 19.031 40.626 20.011 ;
     RECT  41.616 19.885 42.174 20.203 ;
     RECT  43.02 19.535 43.11 20.309 ;
     RECT  43.092 20.309 43.11 20.333 ;
     RECT  2.232 20.011 40.626 20.417 ;
     RECT  2.268 20.417 40.626 20.461 ;
     RECT  41.58 20.203 42.174 20.461 ;
     RECT  0.324 20.875 0.342 20.965 ;
     RECT  2.268 20.461 42.174 21.191 ;
     RECT  0.324 20.965 0.558 21.403 ;
     RECT  43.02 21.499 43.038 21.541 ;
     RECT  43.02 21.541 43.11 21.569 ;
     RECT  0.144 21.403 0.558 21.581 ;
     RECT  2.268 21.191 42.138 21.767 ;
     RECT  2.304 21.767 42.138 22.009 ;
     RECT  2.304 22.009 42.174 22.061 ;
     RECT  43.092 21.569 43.11 22.126 ;
     RECT  0.54 21.581 0.558 22.603 ;
     RECT  0.144 22.603 0.558 22.733 ;
     RECT  2.304 22.061 41.598 22.775 ;
     RECT  0.144 22.733 0.162 22.781 ;
     RECT  37.836 22.775 41.598 22.792 ;
     RECT  37.872 22.792 41.598 22.795 ;
     RECT  2.304 22.775 37.062 22.919 ;
     RECT  37.872 22.795 42.174 23.009 ;
     RECT  36 22.919 37.062 23.045 ;
     RECT  43.092 22.126 43.182 23.081 ;
     RECT  2.304 22.919 35.262 23.179 ;
     RECT  36 23.045 36.378 23.279 ;
     RECT  2.268 23.179 35.262 23.315 ;
     RECT  36 23.279 36.126 23.549 ;
     RECT  36 23.549 36.018 23.585 ;
     RECT  38.196 23.009 42.174 23.729 ;
     RECT  0.108 23.827 0.126 23.899 ;
     RECT  0.108 23.899 0.558 24.077 ;
     RECT  38.592 23.729 42.174 24.089 ;
     RECT  0.54 24.077 0.558 24.173 ;
     RECT  38.592 24.089 41.562 24.269 ;
     RECT  39.312 24.269 41.562 24.359 ;
     RECT  39.312 24.359 40.77 24.395 ;
     RECT  39.312 24.395 39.33 24.629 ;
     RECT  41.544 24.359 41.562 24.629 ;
     RECT  43.164 23.081 43.182 24.899 ;
     RECT  2.268 23.315 35.097 25.007 ;
     RECT  40.215 24.395 40.77 25.043 ;
     RECT  2.304 25.007 35.097 25.249 ;
     RECT  2.304 25.249 35.118 25.321 ;
     RECT  0.18 25.243 0.198 25.387 ;
     RECT  0.18 25.387 0.342 25.517 ;
     RECT  2.304 25.321 35.154 25.717 ;
     RECT  2.304 25.717 35.19 25.852 ;
     RECT  2.268 25.852 35.19 26.059 ;
     RECT  2.268 26.059 35.262 26.123 ;
     RECT  2.304 26.123 35.262 26.131 ;
     RECT  2.304 26.131 35.37 26.248 ;
     RECT  2.304 26.248 35.442 26.285 ;
     RECT  0.108 26.251 0.126 26.381 ;
     RECT  2.304 26.285 35.262 26.429 ;
     RECT  2.304 26.429 35.226 26.789 ;
     RECT  2.304 26.789 35.097 27.329 ;
     RECT  2.304 27.329 6.786 27.437 ;
     RECT  2.415 27.437 6.786 27.599 ;
     RECT  2.415 27.599 6.282 27.725 ;
     RECT  2.415 27.725 6.21 27.905 ;
     RECT  5.904 27.905 6.21 28.013 ;
     RECT  2.415 27.905 5.13 28.049 ;
     RECT  2.415 28.049 4.05 28.139 ;
     RECT  5.904 28.013 6.138 28.139 ;
     RECT  4.824 28.049 5.13 28.157 ;
     RECT  4.896 28.157 5.13 28.175 ;
     RECT  5.904 28.139 5.958 28.175 ;
     RECT  2.415 28.139 3.834 28.205 ;
     RECT  2.415 28.205 3.438 28.247 ;
     RECT  2.415 28.247 3.402 28.283 ;
     RECT  4.932 28.175 5.13 28.283 ;
     RECT  7.56 27.329 35.097 28.283 ;
     RECT  5.112 28.283 5.13 28.409 ;
     RECT  5.94 28.175 5.958 28.409 ;
     RECT  7.56 28.283 14.238 28.409 ;
     RECT  7.815 28.409 14.238 28.787 ;
     RECT  9.216 28.787 14.238 28.823 ;
     RECT  9.216 28.823 9.954 28.949 ;
     RECT  9.216 28.949 9.414 28.985 ;
     RECT  9.288 28.985 9.414 29.021 ;
     RECT  9.288 29.021 9.306 29.093 ;
     RECT  11.232 28.823 14.238 29.371 ;
     RECT  14.976 28.283 35.097 29.371 ;
     RECT  11.232 29.371 35.097 29.399 ;
     RECT  11.232 29.399 12.006 29.489 ;
     RECT  11.232 29.489 11.502 29.561 ;
     RECT  11.232 29.561 11.43 29.597 ;
     RECT  11.412 29.597 11.43 29.633 ;
     RECT  12.816 29.399 35.097 30.571 ;
     RECT  12.78 30.571 35.097 30.611 ;
     RECT  13.215 30.611 35.097 32.189 ;
     RECT  13.215 32.189 27.63 32.197 ;
     RECT  13.212 32.197 27.63 32.333 ;
     RECT  28.476 32.189 35.097 32.495 ;
     RECT  28.476 32.495 28.674 32.567 ;
     RECT  28.476 32.567 28.566 32.603 ;
     RECT  13.215 32.333 27.63 32.837 ;
     RECT  25.56 32.837 27.63 32.909 ;
     RECT  13.215 32.837 24.462 32.999 ;
     RECT  25.704 32.909 27.63 33.007 ;
     RECT  28.476 32.603 28.494 33.007 ;
     RECT  13.215 32.999 24.297 33.151 ;
     RECT  25.704 33.007 28.494 33.269 ;
     RECT  13.104 33.151 24.297 33.277 ;
     RECT  25.704 33.269 27.918 33.305 ;
     RECT  25.704 33.305 27.486 33.449 ;
     RECT  25.704 33.449 26.91 33.643 ;
     RECT  25.632 33.643 26.91 33.691 ;
     RECT  25.452 33.691 26.91 33.817 ;
     RECT  12.888 33.277 24.297 33.961 ;
     RECT  25.056 33.817 26.91 33.961 ;
     RECT  12.888 33.961 26.91 34.357 ;
     RECT  12.888 34.357 27.198 34.429 ;
     RECT  12.708 34.429 27.198 34.501 ;
     RECT  12.708 34.501 27.342 35.239 ;
     RECT  12.708 35.239 27.954 35.545 ;
     RECT  29.415 32.495 35.097 35.581 ;
     RECT  12.492 35.545 27.954 35.707 ;
     RECT  12.492 35.707 28.674 35.851 ;
     RECT  29.415 35.581 35.19 35.851 ;
     RECT  12.492 35.851 35.19 36.121 ;
     RECT  12.492 36.121 35.226 36.851 ;
     RECT  12.744 36.851 35.226 36.895 ;
     RECT  12.744 36.895 35.262 36.931 ;
     RECT  12.744 36.931 35.658 37.049 ;
     RECT  12.744 37.049 35.298 37.319 ;
     RECT  12.744 37.319 20.142 37.613 ;
     RECT  20.88 37.319 35.298 37.661 ;
     RECT  20.88 37.661 22.194 37.733 ;
     RECT  23.364 37.661 35.298 37.733 ;
     RECT  20.88 37.733 22.014 37.769 ;
     RECT  23.724 37.733 35.298 38.011 ;
     RECT  13.215 37.613 20.142 38.093 ;
     RECT  14.58 38.093 20.142 38.129 ;
     RECT  14.868 38.129 20.142 38.281 ;
     RECT  20.88 37.769 21.834 38.281 ;
     RECT  23.724 38.011 36.018 38.281 ;
     RECT  23.724 38.281 36.126 38.407 ;
     RECT  23.724 38.407 36.306 38.551 ;
     RECT  23.508 38.551 36.306 38.713 ;
     RECT  23.508 38.713 36.414 39.091 ;
     RECT  14.868 38.281 21.834 39.211 ;
     RECT  14.616 39.211 21.834 39.479 ;
     RECT  23.508 39.091 36.81 39.547 ;
     RECT  13.215 38.093 13.497 39.595 ;
     RECT  14.616 39.479 21.726 39.595 ;
     RECT  23.508 39.547 36.846 39.595 ;
     RECT  13.215 39.595 21.726 39.749 ;
     RECT  23.004 39.595 36.846 39.749 ;
     RECT  14.22 39.749 21.258 39.773 ;
     RECT  14.832 39.773 21.258 39.821 ;
     RECT  14.832 39.821 21.222 39.893 ;
     RECT  14.832 39.893 21.15 40.559 ;
     RECT  23.148 39.749 36.846 40.559 ;
     RECT  14.832 40.559 20.682 40.667 ;
     RECT  14.832 40.667 19.854 40.739 ;
     RECT  2.415 28.283 2.697 40.787 ;
     RECT  7.815 28.787 8.097 40.787 ;
     RECT  13.215 39.749 13.497 40.787 ;
     RECT  40.215 25.043 40.497 40.787 ;
     RECT  14.832 40.739 19.062 40.829 ;
     RECT  19.8 40.739 19.854 40.829 ;
     RECT  19.836 40.829 19.854 40.901 ;
     RECT  20.664 40.667 20.682 40.901 ;
     RECT  14.832 40.829 18.99 40.937 ;
     RECT  23.148 40.559 36.774 40.945 ;
     RECT  14.832 40.937 18.705 40.973 ;
     RECT  18.252 40.973 18.705 41.009 ;
     RECT  23.076 40.945 36.774 41.009 ;
     RECT  14.832 40.973 17.082 41.021 ;
     RECT  18.324 41.009 18.705 41.021 ;
     RECT  23.076 41.009 33.894 41.021 ;
     RECT  2.415 40.787 2.505 41.057 ;
     RECT  7.815 40.787 7.905 41.057 ;
     RECT  13.215 40.787 13.305 41.057 ;
     RECT  18.615 41.021 18.705 41.057 ;
     RECT  34.74 41.009 34.905 41.057 ;
     RECT  40.215 40.787 40.305 41.057 ;
     RECT  25.56 41.021 32.922 41.069 ;
     RECT  33.876 41.021 33.894 41.099 ;
     RECT  34.74 41.057 34.758 41.099 ;
     RECT  23.076 41.021 24.75 41.213 ;
     RECT  23.472 41.213 24.75 41.309 ;
     RECT  23.472 41.309 23.49 41.597 ;
     RECT  25.74 41.069 32.922 41.597 ;
     RECT  15.192 41.021 16.074 41.645 ;
     RECT  27 41.597 31.014 42.173 ;
     RECT  15.3 41.645 16.074 42.221 ;
     RECT  25.74 41.597 26.262 42.221 ;
     RECT  27 42.173 27.45 42.221 ;
     RECT  29.124 42.173 29.394 42.221 ;
     RECT  30.204 42.173 31.014 42.221 ;
     RECT  28.332 42.173 28.35 42.269 ;
     RECT  27 42.221 27.414 42.317 ;
     RECT  29.304 42.221 29.394 42.317 ;
     RECT  27.036 42.317 27.414 42.365 ;
     RECT  29.304 42.317 29.322 42.365 ;
     RECT  27.036 42.365 27.342 42.413 ;
     RECT  15.912 42.221 15.93 43.085 ;
     RECT  24.552 41.309 24.75 43.085 ;
     RECT  25.74 42.221 25.758 43.085 ;
     RECT  27.036 42.413 27.054 43.085 ;
     RECT  30.672 42.221 31.014 43.085 ;
     RECT  36 41.009 36.774 43.085 ;
     RECT  33.012 43.003 33.03 43.133 ;
     RECT  36.288 43.085 36.774 43.133 ;
     RECT  36.756 43.133 36.774 43.181 ;
    LAYER M4 ;
     RECT  0.084 1.008 0.097 1.032 ;
     RECT  0.06 1.032 0.097 1.104 ;
     RECT  0.084 1.104 0.097 1.128 ;
     RECT  0.06 1.128 0.097 1.2 ;
     RECT  0.084 1.2 0.097 1.224 ;
     RECT  0.06 1.224 0.097 1.296 ;
     RECT  0.084 1.296 0.097 1.32 ;
     RECT  0.06 1.32 0.097 1.392 ;
     RECT  0.084 1.392 0.097 1.416 ;
     RECT  0.06 1.416 0.097 1.488 ;
     RECT  0.084 1.488 0.097 1.512 ;
     RECT  0.06 1.512 0.097 1.584 ;
     RECT  0.084 1.584 0.097 1.608 ;
     RECT  0.06 1.608 0.097 1.68 ;
     RECT  0.084 1.68 0.097 1.704 ;
     RECT  0.06 1.704 0.097 1.776 ;
     RECT  0.084 1.776 0.097 1.8 ;
     RECT  0.06 1.8 0.097 1.872 ;
     RECT  0.084 1.872 0.097 1.896 ;
     RECT  0.06 1.896 0.097 1.968 ;
     RECT  0.084 1.968 0.097 1.992 ;
     RECT  0.06 1.992 0.097 2.064 ;
     RECT  0.084 2.064 0.097 2.088 ;
     RECT  0.06 2.088 0.097 2.16 ;
     RECT  0.084 2.16 0.097 2.184 ;
     RECT  0.06 2.184 0.097 2.256 ;
     RECT  0.084 2.256 0.097 2.28 ;
     RECT  0.06 2.28 0.097 2.352 ;
     RECT  0.084 2.352 0.097 2.376 ;
     RECT  0.06 2.376 0.097 2.448 ;
     RECT  0.084 2.448 0.097 2.472 ;
     RECT  0.06 2.472 0.097 2.544 ;
     RECT  0.084 2.544 0.097 2.568 ;
     RECT  0.06 2.568 0.097 2.64 ;
     RECT  0.084 2.64 0.097 2.664 ;
     RECT  0.06 2.664 0.097 2.736 ;
     RECT  0.084 2.736 0.097 2.76 ;
     RECT  0.06 2.76 0.097 2.832 ;
     RECT  0.084 2.832 0.097 2.856 ;
     RECT  0.06 2.856 0.097 2.928 ;
     RECT  0.084 2.928 0.097 2.952 ;
     RECT  0.06 2.952 0.097 3.024 ;
     RECT  0.084 3.024 0.097 3.048 ;
     RECT  0.06 3.048 0.097 3.12 ;
     RECT  0.084 3.12 0.097 3.144 ;
     RECT  0.06 3.144 0.097 3.216 ;
     RECT  0.084 3.216 0.097 3.24 ;
     RECT  0.06 3.24 0.097 3.312 ;
     RECT  0.084 3.312 0.097 3.336 ;
     RECT  0.06 3.336 0.097 3.408 ;
     RECT  0.084 3.408 0.097 3.432 ;
     RECT  0.06 3.432 0.097 3.504 ;
     RECT  0.084 3.504 0.097 3.528 ;
     RECT  0.06 3.528 0.097 3.6 ;
     RECT  0.084 3.6 0.097 3.624 ;
     RECT  0.06 3.624 0.097 3.696 ;
     RECT  0.084 3.696 0.097 3.72 ;
     RECT  0.06 3.72 0.097 3.792 ;
     RECT  0.084 3.792 0.097 3.816 ;
     RECT  0.06 3.816 0.097 3.888 ;
     RECT  0.084 3.888 0.097 3.912 ;
     RECT  0.06 3.912 0.097 3.984 ;
     RECT  0.084 3.984 0.097 4.008 ;
     RECT  0.06 4.008 0.097 4.848 ;
     RECT  0.084 4.848 0.097 4.872 ;
     RECT  0.06 4.872 0.097 4.944 ;
     RECT  0.084 4.944 0.097 4.968 ;
     RECT  0.06 4.968 0.097 5.04 ;
     RECT  0.084 5.04 0.097 5.064 ;
     RECT  0.06 5.064 0.097 5.136 ;
     RECT  0.084 5.136 0.097 5.16 ;
     RECT  0.06 5.16 0.097 5.232 ;
     RECT  0.084 5.232 0.097 5.256 ;
     RECT  0.06 5.256 0.097 5.328 ;
     RECT  0.084 5.328 0.097 5.352 ;
     RECT  0.06 5.352 0.097 5.424 ;
     RECT  0.084 5.424 0.097 5.448 ;
     RECT  0.06 5.448 0.097 5.52 ;
     RECT  0.084 5.52 0.097 5.544 ;
     RECT  0.06 5.544 0.097 5.616 ;
     RECT  0.084 5.616 0.097 5.64 ;
     RECT  0.06 5.64 0.097 5.712 ;
     RECT  0.084 5.712 0.097 5.736 ;
     RECT  0.06 5.736 0.097 5.808 ;
     RECT  0.084 5.808 0.097 5.832 ;
     RECT  0.06 5.832 0.097 5.904 ;
     RECT  0.084 5.904 0.097 5.928 ;
     RECT  0.06 5.928 0.097 6 ;
     RECT  0.084 6 0.097 6.024 ;
     RECT  0.06 6.024 0.097 6.096 ;
     RECT  0.084 6.096 0.097 6.12 ;
     RECT  0.06 6.12 0.097 6.192 ;
     RECT  0.084 6.192 0.097 6.216 ;
     RECT  0.06 6.216 0.097 6.288 ;
     RECT  0.084 6.288 0.097 6.312 ;
     RECT  0.06 6.312 0.097 6.384 ;
     RECT  0.084 6.384 0.097 6.408 ;
     RECT  0.06 6.408 0.097 6.48 ;
     RECT  0.084 6.48 0.097 6.504 ;
     RECT  0.06 6.504 0.097 6.576 ;
     RECT  0.084 6.576 0.097 6.6 ;
     RECT  0.06 6.6 0.097 6.672 ;
     RECT  0.084 6.672 0.097 6.696 ;
     RECT  0.06 6.696 0.097 6.768 ;
     RECT  0.084 6.768 0.097 6.792 ;
     RECT  0.06 6.792 0.097 6.864 ;
     RECT  0.084 6.864 0.097 6.888 ;
     RECT  0.06 6.888 0.097 6.96 ;
     RECT  0.084 6.96 0.097 6.984 ;
     RECT  0.06 6.984 0.097 7.056 ;
     RECT  0.084 7.056 0.097 7.08 ;
     RECT  0.06 7.08 0.097 7.152 ;
     RECT  0.084 7.152 0.097 7.176 ;
     RECT  0.06 7.176 0.097 7.248 ;
     RECT  0.084 7.248 0.097 7.272 ;
     RECT  0.06 7.272 0.097 7.344 ;
     RECT  0.084 7.344 0.097 7.368 ;
     RECT  0.06 7.368 0.097 7.44 ;
     RECT  0.084 7.44 0.097 7.464 ;
     RECT  0.06 7.464 0.097 7.536 ;
     RECT  0.084 7.536 0.097 7.56 ;
     RECT  0.06 7.56 0.097 7.632 ;
     RECT  0.084 7.632 0.097 7.656 ;
     RECT  0.06 7.656 0.097 7.728 ;
     RECT  0.084 7.728 0.097 7.752 ;
     RECT  0.06 7.752 0.097 7.824 ;
     RECT  0.084 7.824 0.097 7.848 ;
     RECT  0.06 7.848 0.097 7.92 ;
     RECT  0.084 7.92 0.097 7.944 ;
     RECT  0.06 7.944 0.097 8.016 ;
     RECT  0.084 8.016 0.097 8.04 ;
     RECT  0.06 8.04 0.097 8.112 ;
     RECT  0.084 8.112 0.097 8.136 ;
     RECT  0.06 8.136 0.097 8.208 ;
     RECT  0.084 8.208 0.097 8.232 ;
     RECT  0.06 8.232 0.097 8.304 ;
     RECT  0.084 8.304 0.097 8.328 ;
     RECT  0.06 8.328 0.097 8.4 ;
     RECT  0.084 8.4 0.097 8.424 ;
     RECT  0.06 8.424 0.097 8.496 ;
     RECT  0.084 8.496 0.097 8.52 ;
     RECT  0.06 8.52 0.097 8.592 ;
     RECT  0.084 8.592 0.097 8.616 ;
     RECT  0.06 8.616 0.097 8.688 ;
     RECT  0.084 8.688 0.097 8.712 ;
     RECT  0.06 8.712 0.097 8.784 ;
     RECT  0.084 8.784 0.097 8.808 ;
     RECT  0.06 8.808 0.097 8.88 ;
     RECT  0.084 8.88 0.097 8.904 ;
     RECT  0.06 8.904 0.097 8.976 ;
     RECT  0.084 8.976 0.097 9 ;
     RECT  0.06 9 0.097 9.072 ;
     RECT  0.084 9.072 0.097 9.096 ;
     RECT  0.06 9.096 0.097 9.168 ;
     RECT  0.084 9.168 0.097 9.192 ;
     RECT  0.06 9.192 0.097 9.264 ;
     RECT  0.084 9.264 0.097 9.288 ;
     RECT  0.06 9.288 0.097 9.36 ;
     RECT  0.084 9.36 0.097 9.384 ;
     RECT  0.06 9.384 0.097 9.456 ;
     RECT  0.084 9.456 0.097 9.48 ;
     RECT  0.06 9.48 0.097 9.552 ;
     RECT  0.084 9.552 0.097 9.576 ;
     RECT  0.06 9.576 0.097 9.648 ;
     RECT  0.084 9.648 0.097 9.672 ;
     RECT  0.06 9.672 0.097 9.744 ;
     RECT  0.084 9.744 0.097 9.768 ;
     RECT  0.06 9.768 0.097 9.84 ;
     RECT  0.084 9.84 0.097 9.864 ;
     RECT  0.06 9.864 0.097 9.936 ;
     RECT  0.084 9.936 0.097 9.96 ;
     RECT  0.06 9.96 0.097 10.032 ;
     RECT  0.084 10.032 0.097 10.056 ;
     RECT  0.06 10.056 0.097 10.128 ;
     RECT  0.084 10.128 0.097 10.152 ;
     RECT  0.06 10.152 0.097 10.224 ;
     RECT  0.084 10.224 0.097 10.248 ;
     RECT  0.06 10.248 0.097 10.32 ;
     RECT  0.084 10.32 0.097 10.344 ;
     RECT  0.06 10.344 0.097 10.416 ;
     RECT  0.084 10.416 0.097 10.44 ;
     RECT  0.06 10.44 0.097 10.512 ;
     RECT  0.084 10.512 0.097 10.536 ;
     RECT  0.06 10.536 0.097 10.608 ;
     RECT  0.084 10.608 0.097 10.632 ;
     RECT  0.06 10.632 0.097 10.704 ;
     RECT  0.084 10.704 0.097 10.728 ;
     RECT  0.06 10.728 0.097 10.8 ;
     RECT  0.084 10.8 0.097 10.824 ;
     RECT  0.06 10.824 0.097 10.896 ;
     RECT  0.084 10.896 0.097 10.92 ;
     RECT  0.06 10.92 0.097 10.992 ;
     RECT  0.084 10.992 0.097 11.016 ;
     RECT  0.06 11.016 0.097 11.088 ;
     RECT  0.084 11.088 0.097 11.112 ;
     RECT  0.06 11.112 0.097 11.184 ;
     RECT  0.084 11.184 0.097 11.208 ;
     RECT  0.06 11.208 0.097 11.28 ;
     RECT  0.084 11.28 0.097 11.304 ;
     RECT  0.06 11.304 0.097 11.376 ;
     RECT  0.084 11.376 0.097 11.4 ;
     RECT  0.06 11.4 0.097 11.472 ;
     RECT  0.084 11.472 0.097 11.496 ;
     RECT  0.06 11.496 0.097 11.568 ;
     RECT  0.084 11.568 0.097 11.592 ;
     RECT  0.06 11.592 0.097 11.664 ;
     RECT  0.084 11.664 0.097 11.688 ;
     RECT  0.06 11.688 0.097 11.76 ;
     RECT  0.084 11.76 0.097 11.784 ;
     RECT  0.06 11.784 0.097 11.856 ;
     RECT  0.084 11.856 0.097 11.88 ;
     RECT  0.06 11.88 0.097 11.952 ;
     RECT  0.084 11.952 0.097 11.976 ;
     RECT  0.06 11.976 0.097 12.048 ;
     RECT  0.084 12.048 0.097 12.072 ;
     RECT  0.06 12.072 0.097 12.144 ;
     RECT  0.084 12.144 0.097 12.168 ;
     RECT  0.06 12.168 0.097 12.24 ;
     RECT  0.084 12.24 0.097 12.264 ;
     RECT  0.06 12.264 0.097 12.336 ;
     RECT  0.084 12.336 0.097 12.36 ;
     RECT  0.06 12.36 0.097 12.432 ;
     RECT  0.084 12.432 0.097 12.456 ;
     RECT  0.06 12.456 0.097 12.528 ;
     RECT  0.084 12.528 0.097 12.552 ;
     RECT  0.06 12.552 0.097 12.624 ;
     RECT  0.084 12.624 0.097 12.648 ;
     RECT  0.06 12.648 0.097 12.72 ;
     RECT  0.084 12.72 0.097 12.744 ;
     RECT  0.06 12.744 0.097 12.816 ;
     RECT  0.084 12.816 0.097 12.84 ;
     RECT  0.06 12.84 0.097 12.912 ;
     RECT  0.084 12.912 0.097 12.936 ;
     RECT  0.06 12.936 0.097 13.008 ;
     RECT  0.084 13.008 0.097 13.032 ;
     RECT  0.06 13.032 0.097 13.104 ;
     RECT  0.084 13.104 0.097 13.128 ;
     RECT  0.06 13.128 0.097 13.2 ;
     RECT  0.084 13.2 0.097 13.224 ;
     RECT  0.06 13.224 0.097 13.296 ;
     RECT  0.084 13.296 0.097 13.32 ;
     RECT  0.06 13.32 0.097 13.392 ;
     RECT  0.084 13.392 0.097 13.416 ;
     RECT  0.06 13.416 0.097 13.488 ;
     RECT  0.084 13.488 0.097 13.512 ;
     RECT  0.06 13.512 0.097 13.584 ;
     RECT  0.084 13.584 0.097 13.608 ;
     RECT  0.06 13.608 0.097 13.68 ;
     RECT  0.084 13.68 0.097 13.704 ;
     RECT  0.06 13.704 0.097 13.776 ;
     RECT  0.084 13.776 0.097 13.8 ;
     RECT  0.06 13.8 0.097 13.872 ;
     RECT  0.084 13.872 0.097 13.896 ;
     RECT  0.06 13.896 0.097 13.968 ;
     RECT  0.084 13.968 0.097 13.992 ;
     RECT  0.06 13.992 0.097 14.064 ;
     RECT  0.084 14.064 0.097 14.088 ;
     RECT  0.06 14.088 0.097 14.16 ;
     RECT  0.084 14.16 0.097 14.184 ;
     RECT  0.06 14.184 0.097 14.256 ;
     RECT  0.084 14.256 0.097 14.28 ;
     RECT  0.06 14.28 0.097 14.352 ;
     RECT  0.084 14.352 0.097 14.376 ;
     RECT  0.06 14.376 0.097 14.448 ;
     RECT  0.084 14.448 0.097 14.472 ;
     RECT  0.06 14.472 0.097 14.544 ;
     RECT  0.084 14.544 0.097 14.568 ;
     RECT  0.06 14.568 0.097 14.64 ;
     RECT  0.084 14.64 0.097 14.664 ;
     RECT  0.06 14.664 0.097 14.736 ;
     RECT  0.084 14.736 0.097 14.76 ;
     RECT  0.06 14.76 0.097 14.832 ;
     RECT  0.084 14.832 0.097 14.856 ;
     RECT  0.06 14.856 0.097 14.928 ;
     RECT  0.084 14.928 0.097 14.952 ;
     RECT  0.06 14.952 0.097 15.024 ;
     RECT  0.084 15.024 0.097 15.048 ;
     RECT  0.06 15.048 0.097 15.12 ;
     RECT  0.084 15.12 0.097 15.144 ;
     RECT  0.06 15.144 0.097 15.216 ;
     RECT  0.084 15.216 0.097 15.24 ;
     RECT  0.06 15.24 0.097 15.312 ;
     RECT  0.084 15.312 0.097 15.336 ;
     RECT  0.06 15.336 0.097 15.408 ;
     RECT  0.084 15.408 0.097 15.432 ;
     RECT  0.06 15.432 0.097 15.504 ;
     RECT  0.084 15.504 0.097 15.528 ;
     RECT  0.06 15.528 0.097 15.6 ;
     RECT  0.084 15.6 0.097 15.624 ;
     RECT  0.06 15.624 0.097 15.696 ;
     RECT  0.084 15.696 0.097 15.72 ;
     RECT  0.06 15.72 0.097 15.792 ;
     RECT  0.084 15.792 0.097 15.816 ;
     RECT  0.06 15.816 0.097 15.888 ;
     RECT  0.084 15.888 0.097 15.912 ;
     RECT  0.06 15.912 0.097 15.984 ;
     RECT  0.084 15.984 0.097 16.008 ;
     RECT  0.06 16.008 0.097 16.08 ;
     RECT  0.084 16.08 0.097 16.104 ;
     RECT  0.06 16.104 0.097 16.176 ;
     RECT  0.084 16.176 0.097 16.2 ;
     RECT  0.06 16.2 0.097 16.272 ;
     RECT  0.084 16.272 0.097 16.296 ;
     RECT  0.06 16.296 0.097 16.368 ;
     RECT  0.084 16.368 0.097 16.392 ;
     RECT  0.06 16.392 0.097 16.464 ;
     RECT  0.084 16.464 0.097 16.488 ;
     RECT  0.06 16.488 0.097 16.56 ;
     RECT  0.084 16.56 0.097 16.584 ;
     RECT  0.06 16.584 0.097 16.656 ;
     RECT  0.084 16.656 0.097 16.68 ;
     RECT  0.06 16.68 0.097 16.752 ;
     RECT  0.084 16.752 0.097 16.776 ;
     RECT  0.06 16.776 0.097 16.848 ;
     RECT  0.084 16.848 0.097 16.872 ;
     RECT  0.06 16.872 0.097 16.944 ;
     RECT  0.084 16.944 0.097 16.968 ;
     RECT  0.06 16.968 0.097 17.04 ;
     RECT  0.084 17.04 0.097 17.064 ;
     RECT  0.06 17.064 0.097 17.136 ;
     RECT  0.084 17.136 0.097 17.16 ;
     RECT  0.06 17.16 0.097 17.232 ;
     RECT  0.084 17.232 0.097 17.256 ;
     RECT  0.06 17.256 0.097 17.328 ;
     RECT  0.084 17.328 0.097 17.352 ;
     RECT  0.06 17.352 0.097 17.424 ;
     RECT  0.084 17.424 0.097 17.448 ;
     RECT  0.06 17.448 0.097 17.52 ;
     RECT  0.084 17.52 0.097 17.544 ;
     RECT  0.06 17.544 0.097 17.616 ;
     RECT  0.084 17.616 0.097 17.64 ;
     RECT  0.06 17.64 0.097 17.712 ;
     RECT  0.084 17.712 0.097 17.736 ;
     RECT  0.06 17.736 0.097 17.808 ;
     RECT  0.084 17.808 0.097 17.832 ;
     RECT  0.06 17.832 0.097 17.904 ;
     RECT  0.084 17.904 0.097 17.928 ;
     RECT  0.06 17.928 0.097 18 ;
     RECT  0.084 18 0.097 18.024 ;
     RECT  0.06 18.024 0.097 18.096 ;
     RECT  0.084 18.096 0.097 18.12 ;
     RECT  0.06 18.12 0.097 18.192 ;
     RECT  0.084 18.192 0.097 18.216 ;
     RECT  0.06 18.216 0.097 18.288 ;
     RECT  0.084 18.288 0.097 18.312 ;
     RECT  0.06 18.312 0.097 18.384 ;
     RECT  0.084 18.384 0.097 18.408 ;
     RECT  0.06 18.408 0.097 18.48 ;
     RECT  0.084 18.48 0.097 18.504 ;
     RECT  0.06 18.504 0.097 18.576 ;
     RECT  0.084 18.576 0.097 18.6 ;
     RECT  0.06 18.6 0.097 18.672 ;
     RECT  0.084 18.672 0.097 18.696 ;
     RECT  0.06 18.696 0.097 18.768 ;
     RECT  0.084 18.768 0.097 18.792 ;
     RECT  0.06 18.792 0.097 18.864 ;
     RECT  0.084 18.864 0.097 18.888 ;
     RECT  0.06 18.888 0.097 18.96 ;
     RECT  0.084 18.96 0.097 18.984 ;
     RECT  0.06 18.984 0.097 19.056 ;
     RECT  0.084 19.056 0.097 19.08 ;
     RECT  0.06 19.08 0.097 19.152 ;
     RECT  0.084 19.152 0.097 19.176 ;
     RECT  0.06 19.176 0.097 19.248 ;
     RECT  0.084 19.248 0.097 19.272 ;
     RECT  0.06 19.272 0.097 19.344 ;
     RECT  0.084 19.344 0.097 19.368 ;
     RECT  0.06 19.368 0.097 19.44 ;
     RECT  0.084 19.44 0.097 19.464 ;
     RECT  0.06 19.464 0.097 19.536 ;
     RECT  0.084 19.536 0.097 19.56 ;
     RECT  0.06 19.56 0.097 19.632 ;
     RECT  0.084 19.632 0.097 19.656 ;
     RECT  0.06 19.656 0.097 19.728 ;
     RECT  0.084 19.728 0.097 19.752 ;
     RECT  0.06 19.752 0.097 19.824 ;
     RECT  0.084 19.824 0.097 19.848 ;
     RECT  0.06 19.848 0.097 19.92 ;
     RECT  0.084 19.92 0.097 19.944 ;
     RECT  0.06 19.944 0.097 20.016 ;
     RECT  0.084 20.016 0.097 20.04 ;
     RECT  0.06 20.04 0.097 20.112 ;
     RECT  0.084 20.112 0.097 20.136 ;
     RECT  0.06 20.136 0.097 20.208 ;
     RECT  0.084 20.208 0.097 20.232 ;
     RECT  0.06 20.232 0.097 20.304 ;
     RECT  0.084 20.304 0.097 20.328 ;
     RECT  0.06 20.328 0.097 20.4 ;
     RECT  0.084 20.4 0.097 20.424 ;
     RECT  0.06 20.424 0.097 20.496 ;
     RECT  0.084 20.496 0.097 20.52 ;
     RECT  0.06 20.52 0.097 20.592 ;
     RECT  0.084 20.592 0.097 20.616 ;
     RECT  0.06 20.616 0.097 20.688 ;
     RECT  0.084 20.688 0.097 20.712 ;
     RECT  0.06 20.712 0.097 20.784 ;
     RECT  0.084 20.784 0.097 20.808 ;
     RECT  0.06 20.808 0.097 20.88 ;
     RECT  0.084 20.88 0.097 20.904 ;
     RECT  0.06 20.904 0.097 20.976 ;
     RECT  0.084 20.976 0.097 21 ;
     RECT  0.06 21 0.097 21.072 ;
     RECT  0.084 21.072 0.097 21.096 ;
     RECT  0.06 21.096 0.097 21.168 ;
     RECT  0.084 21.168 0.097 21.192 ;
     RECT  0.06 21.192 0.097 21.264 ;
     RECT  0.084 21.264 0.097 21.288 ;
     RECT  0.06 21.288 0.097 21.36 ;
     RECT  0.084 21.36 0.097 21.384 ;
     RECT  0.06 21.384 0.097 21.456 ;
     RECT  0.084 21.456 0.097 21.48 ;
     RECT  0.06 21.48 0.097 21.552 ;
     RECT  0.084 21.552 0.097 21.576 ;
     RECT  0.06 21.576 0.097 21.648 ;
     RECT  0.084 21.648 0.097 21.672 ;
     RECT  0.06 21.672 0.097 21.744 ;
     RECT  0.084 21.744 0.097 21.768 ;
     RECT  0.06 21.768 0.097 21.84 ;
     RECT  0.084 21.84 0.097 21.864 ;
     RECT  0.06 21.864 0.097 21.936 ;
     RECT  0.084 21.936 0.097 21.96 ;
     RECT  0.06 21.96 0.097 22.032 ;
     RECT  0.084 22.032 0.097 22.056 ;
     RECT  0.06 22.056 0.097 22.128 ;
     RECT  0.084 22.128 0.097 22.152 ;
     RECT  0.06 22.152 0.097 22.224 ;
     RECT  0.084 22.224 0.097 22.248 ;
     RECT  0.06 22.248 0.097 22.32 ;
     RECT  0.084 22.32 0.097 22.344 ;
     RECT  0.06 22.344 0.097 22.416 ;
     RECT  0.084 22.416 0.097 22.44 ;
     RECT  0.06 22.44 0.097 22.512 ;
     RECT  0.084 22.512 0.097 22.536 ;
     RECT  0.06 22.536 0.097 22.608 ;
     RECT  0.084 22.608 0.097 22.632 ;
     RECT  0.06 22.632 0.097 22.704 ;
     RECT  0.084 22.704 0.097 22.728 ;
     RECT  0.06 22.728 0.097 22.8 ;
     RECT  0.084 22.8 0.097 22.824 ;
     RECT  0.06 22.824 0.097 22.896 ;
     RECT  0.084 22.896 0.097 22.92 ;
     RECT  0.06 22.92 0.097 22.992 ;
     RECT  0.084 22.992 0.097 23.016 ;
     RECT  0.06 23.016 0.097 23.088 ;
     RECT  0.084 23.088 0.097 23.112 ;
     RECT  0.06 23.112 0.097 23.184 ;
     RECT  0.084 23.184 0.097 23.208 ;
     RECT  0.06 23.208 0.097 24.048 ;
     RECT  0.084 24.048 0.097 24.072 ;
     RECT  0.06 24.072 0.097 24.144 ;
     RECT  0.084 24.144 0.097 24.168 ;
     RECT  0.06 24.168 0.097 24.24 ;
     RECT  0.084 24.24 0.097 24.264 ;
     RECT  0.06 24.264 0.097 24.336 ;
     RECT  0.084 24.336 0.097 24.36 ;
     RECT  0.06 24.36 0.097 24.432 ;
     RECT  0.084 24.432 0.097 24.456 ;
     RECT  0.06 24.456 0.097 24.528 ;
     RECT  0.084 24.528 0.097 24.552 ;
     RECT  0.06 24.552 0.097 24.624 ;
     RECT  0.084 24.624 0.097 24.648 ;
     RECT  0.06 24.648 0.097 24.72 ;
     RECT  0.084 24.72 0.097 24.744 ;
     RECT  0.06 24.744 0.097 24.816 ;
     RECT  0.084 24.816 0.097 24.84 ;
     RECT  0.06 24.84 0.097 24.912 ;
     RECT  0.084 24.912 0.097 24.936 ;
     RECT  0.06 24.936 0.097 25.008 ;
     RECT  0.084 25.008 0.097 25.032 ;
     RECT  0.06 25.032 0.097 25.104 ;
     RECT  0.084 25.104 0.097 25.128 ;
     RECT  0.06 25.128 0.097 25.2 ;
     RECT  0.084 25.2 0.097 25.224 ;
     RECT  0.06 25.224 0.097 25.296 ;
     RECT  0.084 25.296 0.097 25.32 ;
     RECT  0.06 25.32 0.097 25.392 ;
     RECT  0.084 25.392 0.097 25.416 ;
     RECT  0.06 25.416 0.097 25.488 ;
     RECT  0.084 25.488 0.097 25.512 ;
     RECT  0.06 25.512 0.097 25.584 ;
     RECT  0.084 25.584 0.097 25.608 ;
     RECT  0.06 25.608 0.097 25.68 ;
     RECT  0.084 25.68 0.097 25.704 ;
     RECT  0.06 25.704 0.097 25.776 ;
     RECT  0.084 25.776 0.097 25.8 ;
     RECT  0.06 25.8 0.097 25.872 ;
     RECT  0.084 25.872 0.097 25.896 ;
     RECT  0.06 25.896 0.097 25.968 ;
     RECT  0.084 25.968 0.097 25.992 ;
     RECT  0.06 25.992 0.097 26.064 ;
     RECT  0.084 26.064 0.097 26.088 ;
     RECT  0.06 26.088 0.097 26.16 ;
     RECT  0.084 26.16 0.097 26.184 ;
     RECT  0.06 26.184 0.097 26.256 ;
     RECT  0.084 26.256 0.097 26.28 ;
     RECT  0.097 1.008 0.569 26.376 ;
     RECT  0.569 1.008 2.408 23.208 ;
     RECT  0.569 24.24 2.408 26.376 ;
     RECT  2.408 1.008 2.512 41.052 ;
     RECT  2.512 1.008 2.704 40.782 ;
     RECT  2.704 1.008 3.845 28.2 ;
     RECT  3.845 1.296 3.881 28.2 ;
     RECT  3.881 2.064 4.921 28.2 ;
     RECT  4.921 2.064 5.027 28.248 ;
     RECT  5.027 2.064 5.033 28.2 ;
     RECT  5.033 2.64 6.001 28.2 ;
     RECT  6.001 2.208 6.829 28.2 ;
     RECT  6.829 2.064 7.045 28.2 ;
     RECT  5.929 0.48 7.292 0.504 ;
     RECT  7.292 0.48 7.429 0.552 ;
     RECT  7.429 0.48 7.477 0.6 ;
     RECT  7.045 1.728 7.808 28.2 ;
     RECT  6.517 31.776 7.808 31.8 ;
     RECT  7.808 1.728 7.912 41.052 ;
     RECT  7.477 0.144 7.955 0.6 ;
     RECT  7.912 1.728 8.104 40.782 ;
     RECT  7.955 0.144 8.242 0.408 ;
     RECT  8.242 0.096 8.243 0.408 ;
     RECT  8.243 0.096 8.339 0.312 ;
     RECT  8.339 0.24 9.205 0.312 ;
     RECT  8.104 1.728 9.733 28.2 ;
     RECT  9.733 1.728 9.857 28.44 ;
     RECT  9.205 0.24 9.997 0.6 ;
     RECT  9.997 0.096 10.081 0.6 ;
     RECT  10.081 0.144 10.357 0.6 ;
     RECT  9.857 1.728 10.357 28.2 ;
     RECT  10.357 0.144 10.739 28.2 ;
     RECT  10.739 1.728 11.113 28.2 ;
     RECT  10.739 0.144 11.269 0.36 ;
     RECT  11.113 1.728 11.333 28.44 ;
     RECT  11.333 18.816 11.401 28.44 ;
     RECT  11.333 1.728 11.765 17.64 ;
     RECT  11.269 0.096 11.941 0.36 ;
     RECT  11.941 0.096 12.025 0.552 ;
     RECT  11.401 18.816 12.481 29.304 ;
     RECT  12.481 18.768 12.613 29.304 ;
     RECT  12.613 18.72 12.805 29.304 ;
     RECT  12.764 30.576 12.805 30.6 ;
     RECT  12.025 0.096 12.841 0.312 ;
     RECT  11.765 1.968 12.901 17.64 ;
     RECT  12.877 34.224 12.985 34.248 ;
     RECT  12.985 34.224 13.013 34.776 ;
     RECT  12.853 35.856 13.013 35.88 ;
     RECT  12.841 0.048 13.052 0.312 ;
     RECT  13.052 0.048 13.093 0.552 ;
     RECT  12.901 1.728 13.093 17.64 ;
     RECT  13.013 34.224 13.093 35.88 ;
     RECT  8.104 31.776 13.201 31.8 ;
     RECT  13.093 0.048 13.208 17.688 ;
     RECT  12.805 18.72 13.208 30.6 ;
     RECT  13.201 31.776 13.208 32.328 ;
     RECT  13.093 33.84 13.208 35.88 ;
     RECT  12.733 37.584 13.208 37.608 ;
     RECT  12.277 38.688 13.208 38.712 ;
     RECT  13.208 0.048 13.312 41.052 ;
     RECT  13.312 0.048 13.385 40.782 ;
     RECT  13.385 1.248 13.504 40.782 ;
     RECT  13.504 1.248 13.619 13.32 ;
     RECT  13.504 28.128 13.619 32.328 ;
     RECT  13.619 1.392 13.637 13.32 ;
     RECT  13.385 0.048 13.667 0.216 ;
     RECT  13.504 18.672 13.811 27.096 ;
     RECT  13.504 14.496 13.955 17.64 ;
     RECT  13.955 14.496 14.033 17.016 ;
     RECT  13.504 36.24 14.069 38.712 ;
     RECT  13.619 28.176 14.105 32.328 ;
     RECT  14.033 16.032 14.213 17.016 ;
     RECT  13.637 1.728 14.285 13.08 ;
     RECT  14.033 14.496 14.476 15 ;
     RECT  13.811 18.672 14.501 26.808 ;
     RECT  14.069 38.064 14.605 38.712 ;
     RECT  13.504 39.744 14.605 39.768 ;
     RECT  14.501 23.952 14.675 26.808 ;
     RECT  14.105 31.392 14.677 32.328 ;
     RECT  13.504 33.84 14.677 34.776 ;
     RECT  14.069 36.24 14.785 37.08 ;
     RECT  14.285 1.968 14.819 13.08 ;
     RECT  14.677 31.392 15.005 34.776 ;
     RECT  14.785 36 15.041 37.08 ;
     RECT  14.105 28.176 15.068 30.36 ;
     RECT  15.005 31.392 15.068 32.472 ;
     RECT  14.605 38.064 15.073 39.768 ;
     RECT  14.821 40.992 15.073 41.016 ;
     RECT  14.819 12 15.145 13.08 ;
     RECT  14.476 14.496 15.145 14.808 ;
     RECT  15.068 28.176 15.148 32.472 ;
     RECT  15.148 28.8 15.155 32.472 ;
     RECT  15.005 33.504 15.157 34.776 ;
     RECT  15.073 38.064 15.181 41.016 ;
     RECT  15.181 38.064 15.221 41.64 ;
     RECT  15.157 33.504 15.244 35.016 ;
     RECT  15.221 38.688 15.289 41.64 ;
     RECT  14.213 16.08 15.361 17.016 ;
     RECT  14.675 24 15.397 26.808 ;
     RECT  15.289 38.688 15.437 42.216 ;
     RECT  15.437 40.464 15.443 42.216 ;
     RECT  15.145 12 15.545 14.808 ;
     RECT  15.361 15.936 15.613 17.016 ;
     RECT  14.501 18.672 15.613 22.92 ;
     RECT  15.545 12.864 15.683 14.808 ;
     RECT  15.244 33.504 15.725 34.776 ;
     RECT  15.397 24 15.761 27.192 ;
     RECT  15.443 42.192 15.901 42.216 ;
     RECT  14.819 1.968 15.925 11.016 ;
     RECT  15.725 33.504 16.019 34.344 ;
     RECT  15.901 42.192 16.019 43.08 ;
     RECT  13.667 0.048 16.049 0.12 ;
     RECT  15.613 15.936 16.057 22.92 ;
     RECT  16.019 42.192 16.115 42.216 ;
     RECT  16.057 16.128 16.124 22.92 ;
     RECT  15.437 38.688 16.225 39.24 ;
     RECT  16.225 38.4 16.333 39.24 ;
     RECT  16.124 16.128 16.499 23.4 ;
     RECT  16.333 38.16 16.517 39.24 ;
     RECT  15.683 13.056 16.661 14.808 ;
     RECT  16.499 16.368 16.765 23.4 ;
     RECT  15.925 1.968 16.769 11.544 ;
     RECT  15.761 24.72 16.883 27.192 ;
     RECT  15.155 29.76 16.909 32.472 ;
     RECT  16.019 33.504 16.909 33.864 ;
     RECT  15.443 40.464 16.933 41.016 ;
     RECT  16.883 26.208 16.945 27.192 ;
     RECT  16.883 24.72 16.949 25.128 ;
     RECT  16.049 0.048 16.985 0.072 ;
     RECT  16.769 2.016 17.021 2.04 ;
     RECT  16.933 39.888 17.021 41.016 ;
     RECT  16.909 29.568 17.057 33.864 ;
     RECT  16.765 16.368 17.093 23.64 ;
     RECT  16.769 3.312 17.129 11.544 ;
     RECT  16.661 13.056 17.129 14.136 ;
     RECT  17.129 3.312 17.237 3.384 ;
     RECT  17.129 4.368 17.449 11.544 ;
     RECT  17.129 13.056 17.449 13.176 ;
     RECT  16.945 26.208 17.845 27.96 ;
     RECT  17.093 16.848 17.881 23.64 ;
     RECT  16.949 24.72 17.881 25.032 ;
     RECT  17.852 34.656 17.941 34.68 ;
     RECT  17.845 26.064 17.948 27.96 ;
     RECT  15.041 36 18.025 37.032 ;
     RECT  17.948 26.064 18.061 28.296 ;
     RECT  17.057 29.568 18.061 33.624 ;
     RECT  17.021 40.848 18.061 41.016 ;
     RECT  18.025 36 18.197 37.08 ;
     RECT  17.941 34.656 18.229 34.824 ;
     RECT  18.197 36 18.335 37.176 ;
     RECT  17.881 16.848 18.373 25.032 ;
     RECT  18.229 34.656 18.373 34.92 ;
     RECT  18.335 35.952 18.373 37.176 ;
     RECT  18.373 16.848 18.428 25.08 ;
     RECT  18.061 26.064 18.428 33.624 ;
     RECT  18.428 16.848 18.469 33.624 ;
     RECT  18.373 34.656 18.469 37.176 ;
     RECT  18.469 16.848 18.493 37.176 ;
     RECT  18.493 16.8 18.601 37.176 ;
     RECT  17.237 3.312 18.608 3.336 ;
     RECT  17.449 4.368 18.608 13.176 ;
     RECT  18.601 16.656 18.608 37.176 ;
     RECT  16.517 38.16 18.608 38.712 ;
     RECT  18.061 39.888 18.608 41.016 ;
     RECT  18.608 2.148 18.712 41.052 ;
     RECT  18.712 2.418 18.904 40.92 ;
     RECT  18.904 38.4 19.001 40.92 ;
     RECT  18.904 4.368 19.043 14.04 ;
     RECT  19.043 4.368 19.109 13.08 ;
     RECT  18.904 15.456 19.109 33.048 ;
     RECT  19.109 16.368 19.145 33.048 ;
     RECT  19.145 29.52 19.217 33.048 ;
     RECT  19.001 38.4 19.577 40.488 ;
     RECT  19.109 6.624 19.667 13.08 ;
     RECT  18.904 34.128 19.897 36.792 ;
     RECT  19.577 38.592 19.973 40.488 ;
     RECT  19.667 7.056 20.051 13.08 ;
     RECT  19.145 16.368 20.221 27.672 ;
     RECT  19.217 29.52 20.221 32.856 ;
     RECT  20.221 16.368 20.291 32.856 ;
     RECT  20.051 11.088 20.293 13.08 ;
     RECT  20.293 11.088 20.329 13.704 ;
     RECT  19.973 38.592 20.441 39.768 ;
     RECT  19.897 34.128 20.521 37.272 ;
     RECT  20.521 34.128 20.545 34.152 ;
     RECT  20.521 35.136 20.585 37.272 ;
     RECT  20.441 39.744 20.621 39.768 ;
     RECT  20.291 16.368 20.915 32.616 ;
     RECT  20.441 38.592 20.977 38.76 ;
     RECT  20.545 33.648 21.161 34.152 ;
     RECT  20.977 38.352 21.161 38.76 ;
     RECT  19.109 4.368 21.305 5.592 ;
     RECT  20.051 7.056 21.349 10.056 ;
     RECT  20.329 11.088 21.349 13.848 ;
     RECT  21.305 4.656 21.395 5.592 ;
     RECT  21.161 38.352 21.485 38.616 ;
     RECT  21.395 4.656 21.521 4.92 ;
     RECT  21.349 7.056 21.589 13.848 ;
     RECT  20.915 16.368 21.593 22.2 ;
     RECT  20.585 35.136 21.665 37.128 ;
     RECT  21.485 38.592 21.701 38.616 ;
     RECT  21.589 7.056 22.165 14.088 ;
     RECT  21.161 33.936 22.261 34.152 ;
     RECT  21.665 35.136 22.261 37.032 ;
     RECT  22.165 6.816 22.273 14.088 ;
     RECT  22.201 15.264 22.273 15.288 ;
     RECT  22.273 6.816 22.277 15.288 ;
     RECT  21.593 18.24 22.412 22.2 ;
     RECT  20.915 23.184 22.412 32.616 ;
     RECT  22.277 14.832 22.421 15.288 ;
     RECT  22.421 15.168 22.489 15.288 ;
     RECT  21.593 16.368 22.489 17.16 ;
     RECT  21.521 4.656 22.637 4.68 ;
     RECT  22.261 33.936 22.741 37.032 ;
     RECT  22.741 33.792 22.781 37.032 ;
     RECT  22.412 18.24 22.957 32.616 ;
     RECT  22.781 33.792 22.957 36.6 ;
     RECT  22.957 18.24 22.961 36.6 ;
     RECT  22.489 15.168 22.993 17.16 ;
     RECT  22.961 18.24 22.993 20.328 ;
     RECT  22.277 6.816 23.353 13.704 ;
     RECT  23.353 6.288 23.425 13.704 ;
     RECT  22.993 15.168 23.425 20.328 ;
     RECT  23.065 41.184 23.461 41.208 ;
     RECT  23.461 41.184 23.749 41.592 ;
     RECT  18.904 3.312 24.008 3.336 ;
     RECT  23.425 6.288 24.008 20.328 ;
     RECT  22.961 21.696 24.008 36.6 ;
     RECT  24.001 37.584 24.008 37.608 ;
     RECT  23.893 39.744 24.008 39.768 ;
     RECT  23.749 41.136 24.008 41.592 ;
     RECT  24.008 2.148 24.083 41.592 ;
     RECT  24.083 2.148 24.112 41.304 ;
     RECT  24.112 2.418 24.304 41.304 ;
     RECT  24.304 34.128 24.445 41.304 ;
     RECT  24.445 40.896 24.467 41.304 ;
     RECT  24.304 15.552 24.653 17.976 ;
     RECT  24.304 14.4 24.725 14.424 ;
     RECT  24.653 15.552 24.725 17.928 ;
     RECT  24.304 12.528 24.892 13.272 ;
     RECT  24.304 3.312 24.905 3.336 ;
     RECT  24.725 16.272 24.905 17.928 ;
     RECT  24.304 19.008 24.905 32.76 ;
     RECT  24.445 34.128 24.977 39.768 ;
     RECT  24.905 19.008 24.988 22.488 ;
     RECT  24.905 16.272 25.085 17.832 ;
     RECT  24.988 19.008 25.121 21.096 ;
     RECT  24.304 6.288 25.139 11.448 ;
     RECT  25.139 6.288 25.337 11.016 ;
     RECT  24.977 34.128 25.436 38.76 ;
     RECT  24.467 40.896 25.522 41.016 ;
     RECT  25.121 19.008 25.549 20.568 ;
     RECT  24.905 23.568 25.621 32.76 ;
     RECT  25.436 33.936 25.621 38.76 ;
     RECT  25.621 23.568 25.705 38.76 ;
     RECT  25.705 23.568 25.733 33.048 ;
     RECT  25.705 34.224 25.769 38.76 ;
     RECT  25.573 39.888 25.801 39.912 ;
     RECT  25.522 40.896 25.801 41.064 ;
     RECT  25.801 39.888 25.805 41.064 ;
     RECT  24.988 22.08 25.909 22.488 ;
     RECT  25.733 23.568 25.909 32.616 ;
     RECT  25.769 34.896 25.949 38.76 ;
     RECT  25.909 22.08 26.017 32.616 ;
     RECT  25.085 16.272 26.053 17.784 ;
     RECT  24.892 12.528 26.089 12.6 ;
     RECT  25.549 18.96 26.089 20.568 ;
     RECT  26.017 21.552 26.089 32.616 ;
     RECT  26.053 16.272 26.125 17.88 ;
     RECT  25.337 6.624 26.149 11.016 ;
     RECT  26.089 12.24 26.149 12.6 ;
     RECT  26.149 6.624 26.195 12.6 ;
     RECT  25.805 40.464 26.225 41.064 ;
     RECT  26.225 40.464 26.233 41.592 ;
     RECT  24.497 43.056 26.233 43.08 ;
     RECT  26.089 18.96 26.243 32.616 ;
     RECT  26.195 10.176 26.269 12.6 ;
     RECT  26.269 10.176 26.273 13.368 ;
     RECT  26.233 40.464 26.309 43.08 ;
     RECT  26.125 16.224 26.377 17.88 ;
     RECT  25.949 35.328 26.381 38.76 ;
     RECT  26.195 6.624 26.453 8.808 ;
     RECT  26.273 11.808 26.525 13.368 ;
     RECT  26.525 13.344 26.561 13.368 ;
     RECT  26.377 16.224 26.629 17.976 ;
     RECT  26.243 18.96 26.629 20.568 ;
     RECT  26.381 35.424 26.705 38.76 ;
     RECT  26.243 21.552 26.725 32.616 ;
     RECT  26.453 6.864 26.741 8.808 ;
     RECT  26.233 14.88 26.765 14.904 ;
     RECT  26.705 35.424 26.771 38.328 ;
     RECT  26.765 14.208 26.773 14.904 ;
     RECT  26.629 16.224 26.773 20.568 ;
     RECT  26.771 35.712 26.777 38.328 ;
     RECT  26.725 21.552 26.813 33.24 ;
     RECT  26.773 14.208 26.819 20.568 ;
     RECT  26.819 14.208 26.849 14.232 ;
     RECT  26.819 15.744 26.849 20.568 ;
     RECT  26.813 31.68 26.86 33.24 ;
     RECT  26.813 21.552 26.885 30.696 ;
     RECT  26.309 42.192 27.065 43.08 ;
     RECT  26.273 10.176 27.101 10.824 ;
     RECT  26.309 40.464 27.101 41.016 ;
     RECT  26.809 39.312 27.155 39.336 ;
     RECT  26.741 7.104 27.241 8.808 ;
     RECT  27.101 10.176 27.241 10.2 ;
     RECT  26.86 32.016 27.347 33.24 ;
     RECT  26.849 18.96 27.349 20.568 ;
     RECT  26.885 21.552 27.349 30.312 ;
     RECT  27.241 7.104 27.569 10.2 ;
     RECT  27.569 7.104 27.677 8.808 ;
     RECT  27.101 40.464 27.731 40.728 ;
     RECT  27.677 7.488 27.827 8.808 ;
     RECT  27.065 42.192 27.923 42.408 ;
     RECT  26.525 11.808 27.929 11.976 ;
     RECT  27.923 42.192 27.973 42.264 ;
     RECT  27.929 11.808 27.997 11.88 ;
     RECT  27.827 8.784 28.001 8.808 ;
     RECT  27.349 18.96 28.041 30.312 ;
     RECT  27.347 32.016 28.041 32.568 ;
     RECT  27.973 42.144 28.165 42.264 ;
     RECT  26.777 35.712 28.249 38.184 ;
     RECT  28.105 39.36 28.249 39.384 ;
     RECT  27.997 11.712 28.289 11.88 ;
     RECT  27.925 13.44 28.357 13.464 ;
     RECT  26.849 15.744 28.357 17.976 ;
     RECT  28.069 40.944 28.357 41.016 ;
     RECT  28.165 42.096 28.357 42.264 ;
     RECT  28.357 13.44 28.508 13.512 ;
     RECT  28.508 13.104 28.537 13.512 ;
     RECT  27.961 6.24 28.861 6.264 ;
     RECT  27.827 7.488 28.861 7.8 ;
     RECT  28.249 35.712 28.861 39.384 ;
     RECT  28.861 6.24 28.981 7.8 ;
     RECT  28.357 40.944 28.981 42.264 ;
     RECT  28.357 15.552 29.005 17.976 ;
     RECT  28.289 11.712 29.041 11.784 ;
     RECT  28.537 13.104 29.077 13.704 ;
     RECT  29.005 15.504 29.077 17.976 ;
     RECT  27.569 9.792 29.113 10.2 ;
     RECT  28.981 40.896 29.173 42.264 ;
     RECT  29.077 13.056 29.185 13.704 ;
     RECT  29.077 15.456 29.185 17.976 ;
     RECT  29.185 13.056 29.257 17.976 ;
     RECT  28.981 6.096 29.365 7.8 ;
     RECT  29.113 8.976 29.365 10.2 ;
     RECT  29.257 12.864 29.365 17.976 ;
     RECT  29.365 6.096 29.408 10.2 ;
     RECT  29.041 11.424 29.408 11.784 ;
     RECT  29.365 12.816 29.408 17.976 ;
     RECT  28.041 18.96 29.408 32.568 ;
     RECT  28.861 35.712 29.408 39.528 ;
     RECT  29.173 40.896 29.408 42.984 ;
     RECT  29.408 2.148 29.512 42.984 ;
     RECT  29.512 2.418 29.704 42.984 ;
     RECT  29.704 18.24 29.765 22.104 ;
     RECT  29.704 35.76 29.843 42.984 ;
     RECT  29.704 11.28 29.873 16.296 ;
     RECT  29.704 23.568 29.891 31.944 ;
     RECT  29.891 31.68 29.917 31.944 ;
     RECT  29.704 6.096 30.017 10.2 ;
     RECT  29.891 23.568 30.017 30.6 ;
     RECT  29.917 31.68 30.017 31.704 ;
     RECT  29.843 35.76 30.083 41.016 ;
     RECT  29.873 11.28 30.124 14.376 ;
     RECT  30.017 10.032 30.233 10.2 ;
     RECT  30.083 40.416 30.241 41.016 ;
     RECT  30.017 6.096 30.269 9 ;
     RECT  29.843 42.144 30.373 42.984 ;
     RECT  30.017 23.568 30.449 30.552 ;
     RECT  30.449 23.568 30.467 29.352 ;
     RECT  29.765 19.488 30.629 22.104 ;
     RECT  30.373 42.144 30.629 43.08 ;
     RECT  30.467 23.568 30.769 28.968 ;
     RECT  30.269 6.096 30.803 7.512 ;
     RECT  30.124 11.28 30.851 13.704 ;
     RECT  29.873 15.408 30.877 16.296 ;
     RECT  30.629 42.864 30.899 43.08 ;
     RECT  30.899 42.96 30.995 43.08 ;
     RECT  30.083 35.76 31.025 38.76 ;
     RECT  30.995 43.056 31.025 43.08 ;
     RECT  30.449 30.528 31.043 30.552 ;
     RECT  30.851 11.28 31.061 13.32 ;
     RECT  30.877 15.36 31.093 16.296 ;
     RECT  29.765 18.24 31.097 18.264 ;
     RECT  30.269 8.544 31.129 9 ;
     RECT  30.629 19.536 31.129 22.104 ;
     RECT  31.129 19.536 31.165 22.152 ;
     RECT  31.025 35.856 31.169 38.76 ;
     RECT  31.129 8.544 31.241 9.144 ;
     RECT  31.093 15.312 31.273 16.296 ;
     RECT  31.061 11.52 31.277 13.32 ;
     RECT  30.241 40.896 31.333 41.016 ;
     RECT  31.333 40.464 31.42 41.016 ;
     RECT  31.273 14.976 31.489 16.296 ;
     RECT  31.42 40.896 31.525 41.016 ;
     RECT  30.769 23.328 31.745 28.968 ;
     RECT  31.745 28.704 31.817 28.968 ;
     RECT  30.803 6.816 31.909 7.512 ;
     RECT  31.241 8.544 31.909 8.952 ;
     RECT  30.233 10.128 31.909 10.2 ;
     RECT  31.489 14.304 31.921 16.296 ;
     RECT  31.165 19.536 31.921 22.344 ;
     RECT  31.745 23.328 31.921 27.384 ;
     RECT  31.921 19.536 31.925 27.384 ;
     RECT  31.909 6.816 31.955 8.952 ;
     RECT  31.925 19.536 31.997 27.336 ;
     RECT  31.955 6.816 32.033 8.568 ;
     RECT  31.997 24.144 32.033 27.336 ;
     RECT  31.921 14.304 32.209 17.064 ;
     RECT  31.997 19.536 32.209 22.824 ;
     RECT  31.169 35.856 32.213 38.712 ;
     RECT  32.033 6.816 32.249 7.992 ;
     RECT  31.909 10.128 32.249 10.344 ;
     RECT  32.245 39.888 32.329 39.912 ;
     RECT  31.277 11.52 32.389 12.936 ;
     RECT  32.209 14.304 32.389 17.256 ;
     RECT  32.213 37.008 32.389 38.712 ;
     RECT  31.525 40.896 32.389 41.592 ;
     RECT  32.213 35.856 32.393 36.024 ;
     RECT  32.389 37.008 32.461 38.76 ;
     RECT  32.033 24.528 32.465 27.336 ;
     RECT  32.461 37.008 32.497 38.808 ;
     RECT  32.389 40.464 32.501 41.592 ;
     RECT  32.497 37.008 32.569 38.904 ;
     RECT  31.817 28.944 32.573 28.968 ;
     RECT  32.389 11.52 32.641 17.832 ;
     RECT  32.209 19.344 32.645 22.824 ;
     RECT  32.641 29.088 32.677 29.112 ;
     RECT  32.293 43.008 32.773 43.032 ;
     RECT  32.645 22.128 32.789 22.824 ;
     RECT  32.641 11.376 32.857 17.832 ;
     RECT  32.501 40.656 32.933 41.592 ;
     RECT  32.677 29.088 32.965 29.208 ;
     RECT  32.773 43.008 33.001 43.08 ;
     RECT  32.857 11.328 33.037 17.832 ;
     RECT  32.965 29.088 33.113 29.352 ;
     RECT  33.037 11.328 33.149 18.216 ;
     RECT  33.113 29.328 33.149 29.352 ;
     RECT  32.461 30.624 33.221 30.648 ;
     RECT  32.249 10.224 33.253 10.344 ;
     RECT  33.149 11.328 33.253 13.176 ;
     RECT  33.001 43.008 33.253 43.128 ;
     RECT  33.149 14.256 33.289 18.216 ;
     RECT  32.645 19.344 33.289 21.144 ;
     RECT  33.253 43.008 33.299 43.176 ;
     RECT  32.393 36 33.301 36.024 ;
     RECT  32.569 37.008 33.301 39 ;
     RECT  32.465 25.248 33.347 27.336 ;
     RECT  33.289 14.256 33.401 21.144 ;
     RECT  33.301 36 33.437 39.528 ;
     RECT  33.401 16.272 33.581 21.144 ;
     RECT  33.437 36 33.581 36.024 ;
     RECT  32.933 40.656 33.617 41.016 ;
     RECT  32.249 6.816 33.797 7.512 ;
     RECT  33.253 9.936 33.833 13.176 ;
     RECT  33.833 10.896 34.117 13.176 ;
     RECT  33.401 14.256 34.117 15 ;
     RECT  33.437 37.056 34.117 39.528 ;
     RECT  33.617 40.656 34.117 40.968 ;
     RECT  34.117 10.896 34.513 15 ;
     RECT  33.581 16.272 34.513 21.048 ;
     RECT  34.513 10.896 34.621 21.048 ;
     RECT  32.789 22.224 34.621 22.824 ;
     RECT  33.797 6.816 34.808 6.84 ;
     RECT  34.621 10.896 34.808 22.824 ;
     RECT  33.397 23.904 34.808 23.928 ;
     RECT  33.347 25.248 34.808 26.904 ;
     RECT  33.865 27.936 34.808 27.96 ;
     RECT  34.765 30.336 34.808 30.36 ;
     RECT  33.829 34.8 34.808 34.824 ;
     RECT  34.117 37.056 34.808 40.968 ;
     RECT  34.808 2.148 34.912 41.052 ;
     RECT  34.912 2.418 35.104 40.968 ;
     RECT  35.104 9.984 35.165 19.368 ;
     RECT  35.104 30.336 35.219 30.36 ;
     RECT  35.165 14.112 35.237 19.368 ;
     RECT  35.104 37.968 35.273 40.968 ;
     RECT  35.104 26.256 35.453 26.28 ;
     RECT  35.237 14.112 35.489 17.112 ;
     RECT  35.489 14.4 35.525 17.112 ;
     RECT  35.525 14.4 35.596 16.872 ;
     RECT  35.104 20.4 35.597 22.776 ;
     RECT  35.597 20.4 35.777 21 ;
     RECT  35.273 38.208 35.777 40.968 ;
     RECT  35.777 39.024 35.921 40.68 ;
     RECT  35.597 22.176 35.957 22.776 ;
     RECT  33.299 43.056 36.029 43.176 ;
     RECT  35.921 39.264 36.101 40.68 ;
     RECT  35.104 6.816 36.131 6.84 ;
     RECT  35.165 9.984 36.131 13.128 ;
     RECT  36.101 39.552 36.173 40.68 ;
     RECT  36.029 43.104 36.317 43.176 ;
     RECT  36.173 40.656 36.425 40.68 ;
     RECT  35.596 15.984 36.673 16.872 ;
     RECT  35.957 22.176 36.713 22.2 ;
     RECT  36.173 39.552 36.713 39.672 ;
     RECT  36.317 43.152 36.785 43.176 ;
     RECT  36.713 39.552 36.857 39.576 ;
     RECT  35.777 20.64 37.033 21 ;
     RECT  35.596 14.4 37.249 14.952 ;
     RECT  36.673 15.984 37.249 17.016 ;
     RECT  35.237 18.144 37.249 19.368 ;
     RECT  37.033 20.592 37.249 21 ;
     RECT  36.131 10.896 37.429 13.128 ;
     RECT  37.249 14.4 37.429 17.016 ;
     RECT  37.249 18.144 37.685 21 ;
     RECT  37.685 18.144 37.721 20.712 ;
     RECT  37.429 10.896 37.897 17.016 ;
     RECT  37.721 18.144 37.897 19.8 ;
     RECT  37.897 10.896 38.225 19.8 ;
     RECT  38.653 21.504 38.765 22.056 ;
     RECT  38.765 21.504 39.589 21.912 ;
     RECT  38.225 10.896 39.625 19.368 ;
     RECT  39.625 10.896 39.913 19.56 ;
     RECT  39.913 10.368 40.208 19.56 ;
     RECT  39.589 20.88 40.208 21.912 ;
     RECT  38.545 23.136 40.208 23.16 ;
     RECT  40.208 2.148 40.312 41.052 ;
     RECT  40.312 2.418 40.504 40.782 ;
     RECT  40.504 20.784 41.533 22.728 ;
     RECT  41.533 20.688 41.569 22.92 ;
     RECT  40.504 10.032 41.605 18.984 ;
     RECT  41.569 20.208 41.605 22.92 ;
     RECT  41.605 10.032 42.181 22.92 ;
     RECT  42.181 9.936 43.116 9.96 ;
     RECT  42.181 9.96 43.164 10.032 ;
     RECT  42.181 10.032 43.116 10.056 ;
     RECT  42.181 10.056 43.164 10.128 ;
     RECT  42.181 10.128 43.116 10.152 ;
     RECT  42.181 10.152 43.164 10.224 ;
     RECT  42.181 10.224 43.116 10.248 ;
     RECT  42.181 10.248 43.164 10.32 ;
     RECT  42.181 10.32 43.116 10.344 ;
     RECT  42.181 10.344 43.164 10.416 ;
     RECT  42.181 10.416 43.116 10.44 ;
     RECT  42.181 10.44 43.164 10.512 ;
     RECT  42.181 10.512 43.116 10.536 ;
     RECT  42.181 10.536 43.164 10.608 ;
     RECT  42.181 10.608 43.116 10.632 ;
     RECT  42.181 10.632 43.164 10.704 ;
     RECT  42.181 10.704 43.116 10.728 ;
     RECT  42.181 10.728 43.164 10.8 ;
     RECT  42.181 10.8 43.116 10.824 ;
     RECT  42.181 10.824 43.164 10.896 ;
     RECT  42.181 10.896 43.116 10.92 ;
     RECT  42.181 10.92 43.164 10.992 ;
     RECT  42.181 10.992 43.116 11.016 ;
     RECT  42.181 11.016 43.164 11.088 ;
     RECT  42.181 11.088 43.116 11.112 ;
     RECT  42.181 11.112 43.164 11.184 ;
     RECT  42.181 11.184 43.116 11.208 ;
     RECT  42.181 11.208 43.164 11.28 ;
     RECT  42.181 11.28 43.116 11.304 ;
     RECT  42.181 11.304 43.164 11.376 ;
     RECT  42.181 11.376 43.116 11.4 ;
     RECT  42.181 11.4 43.164 11.472 ;
     RECT  42.181 11.472 43.116 11.496 ;
     RECT  42.181 11.496 43.164 11.568 ;
     RECT  42.181 11.568 43.116 11.592 ;
     RECT  42.181 11.592 43.164 11.664 ;
     RECT  42.181 11.664 43.116 11.688 ;
     RECT  42.181 11.688 43.164 11.76 ;
     RECT  42.181 11.76 43.116 11.784 ;
     RECT  42.181 11.784 43.164 11.856 ;
     RECT  42.181 11.856 43.116 11.88 ;
     RECT  42.181 11.88 43.164 11.952 ;
     RECT  42.181 11.952 43.116 11.976 ;
     RECT  42.181 11.976 43.164 12.048 ;
     RECT  42.181 12.048 43.116 12.072 ;
     RECT  42.181 12.072 43.164 12.144 ;
     RECT  42.181 12.144 43.116 12.168 ;
     RECT  42.181 12.168 43.164 12.24 ;
     RECT  42.181 12.24 43.116 12.264 ;
     RECT  42.181 12.264 43.164 12.336 ;
     RECT  42.181 12.336 43.116 12.36 ;
     RECT  42.181 12.36 43.164 12.432 ;
     RECT  42.181 12.432 43.116 12.456 ;
     RECT  42.181 12.456 43.164 12.528 ;
     RECT  42.181 12.528 43.116 12.552 ;
     RECT  42.181 12.552 43.164 12.624 ;
     RECT  42.181 12.624 43.116 12.648 ;
     RECT  42.181 12.648 43.164 12.72 ;
     RECT  42.181 12.72 43.116 12.744 ;
     RECT  42.181 12.744 43.164 12.816 ;
     RECT  42.181 12.816 43.116 12.84 ;
     RECT  42.181 12.84 43.164 12.912 ;
     RECT  42.181 12.912 43.116 12.936 ;
     RECT  42.181 12.936 43.164 13.008 ;
     RECT  42.181 13.008 43.116 13.032 ;
     RECT  42.181 13.032 43.164 13.104 ;
     RECT  42.181 13.104 43.116 13.128 ;
     RECT  42.181 13.128 43.164 13.2 ;
     RECT  42.181 13.2 43.116 13.224 ;
     RECT  42.181 13.224 43.164 13.296 ;
     RECT  42.181 13.296 43.116 13.32 ;
     RECT  42.181 13.32 43.164 13.392 ;
     RECT  42.181 13.392 43.116 13.416 ;
     RECT  42.181 13.416 43.164 13.488 ;
     RECT  42.181 13.488 43.116 13.512 ;
     RECT  42.181 13.512 43.164 13.584 ;
     RECT  42.181 13.584 43.116 13.608 ;
     RECT  42.181 13.608 43.164 13.68 ;
     RECT  42.181 13.68 43.116 13.704 ;
     RECT  42.181 13.704 43.164 13.776 ;
     RECT  42.181 13.776 43.116 13.8 ;
     RECT  42.181 13.8 43.164 13.872 ;
     RECT  42.181 13.872 43.116 13.896 ;
     RECT  42.181 13.896 43.164 13.968 ;
     RECT  42.181 13.968 43.116 13.992 ;
     RECT  42.181 13.992 43.164 14.064 ;
     RECT  42.181 14.064 43.116 14.088 ;
     RECT  42.181 14.088 43.164 14.16 ;
     RECT  42.181 14.16 43.116 14.184 ;
     RECT  42.181 14.184 43.164 14.256 ;
     RECT  42.181 14.256 43.116 14.28 ;
     RECT  42.181 14.28 43.164 14.352 ;
     RECT  42.181 14.352 43.116 14.376 ;
     RECT  42.181 14.376 43.164 14.448 ;
     RECT  42.181 14.448 43.116 14.472 ;
     RECT  42.181 14.472 43.164 14.544 ;
     RECT  42.181 14.544 43.116 14.568 ;
     RECT  42.181 14.568 43.164 14.64 ;
     RECT  42.181 14.64 43.116 14.664 ;
     RECT  42.181 14.664 43.164 14.736 ;
     RECT  42.181 14.736 43.116 14.76 ;
     RECT  42.181 14.76 43.164 14.832 ;
     RECT  42.181 14.832 43.116 14.856 ;
     RECT  42.181 14.856 43.164 14.928 ;
     RECT  42.181 14.928 43.116 14.952 ;
     RECT  42.181 14.952 43.164 15.024 ;
     RECT  42.181 15.024 43.116 15.048 ;
     RECT  42.181 15.048 43.164 15.12 ;
     RECT  42.181 15.12 43.116 15.144 ;
     RECT  42.181 15.144 43.164 15.216 ;
     RECT  42.181 15.216 43.116 15.24 ;
     RECT  42.181 15.24 43.164 15.312 ;
     RECT  42.181 15.312 43.116 15.336 ;
     RECT  42.181 15.336 43.164 15.408 ;
     RECT  42.181 15.408 43.116 15.432 ;
     RECT  42.181 15.432 43.164 15.504 ;
     RECT  42.181 15.504 43.116 15.528 ;
     RECT  42.181 15.528 43.164 15.6 ;
     RECT  42.181 15.6 43.116 15.624 ;
     RECT  42.181 15.624 43.164 15.696 ;
     RECT  42.181 15.696 43.116 15.72 ;
     RECT  42.181 15.72 43.164 15.792 ;
     RECT  42.181 15.792 43.116 15.816 ;
     RECT  42.181 15.816 43.164 15.888 ;
     RECT  42.181 15.888 43.116 15.912 ;
     RECT  42.181 15.912 43.164 15.984 ;
     RECT  42.181 15.984 43.116 16.008 ;
     RECT  42.181 16.008 43.164 16.08 ;
     RECT  42.181 16.08 43.116 16.104 ;
     RECT  42.181 16.104 43.164 16.176 ;
     RECT  42.181 16.176 43.116 16.2 ;
     RECT  42.181 16.2 43.164 16.272 ;
     RECT  42.181 16.272 43.116 16.296 ;
     RECT  42.181 16.296 43.164 16.368 ;
     RECT  42.181 16.368 43.116 16.392 ;
     RECT  42.181 16.392 43.164 16.464 ;
     RECT  42.181 16.464 43.116 16.488 ;
     RECT  42.181 16.488 43.164 16.56 ;
     RECT  42.181 16.56 43.116 16.584 ;
     RECT  42.181 16.584 43.164 16.656 ;
     RECT  42.181 16.656 43.116 16.68 ;
     RECT  42.181 16.68 43.164 16.752 ;
     RECT  42.181 16.752 43.116 16.776 ;
     RECT  42.181 16.776 43.164 16.848 ;
     RECT  42.181 16.848 43.116 16.872 ;
     RECT  42.181 16.872 43.164 16.944 ;
     RECT  42.181 16.944 43.116 16.968 ;
     RECT  42.181 16.968 43.164 17.04 ;
     RECT  42.181 17.04 43.116 17.064 ;
     RECT  42.181 17.064 43.164 17.136 ;
     RECT  42.181 17.136 43.116 17.16 ;
     RECT  42.181 17.16 43.164 17.232 ;
     RECT  42.181 17.232 43.116 17.256 ;
     RECT  42.181 17.256 43.164 17.328 ;
     RECT  42.181 17.328 43.116 17.352 ;
     RECT  42.181 17.352 43.164 17.424 ;
     RECT  42.181 17.424 43.116 17.448 ;
     RECT  42.181 17.448 43.164 17.52 ;
     RECT  42.181 17.52 43.116 17.544 ;
     RECT  42.181 17.544 43.164 17.616 ;
     RECT  42.181 17.616 43.116 17.64 ;
     RECT  42.181 17.64 43.164 17.712 ;
     RECT  42.181 17.712 43.116 17.736 ;
     RECT  42.181 17.736 43.164 17.808 ;
     RECT  42.181 17.808 43.116 17.832 ;
     RECT  42.181 17.832 43.164 17.904 ;
     RECT  42.181 17.904 43.116 17.928 ;
     RECT  42.181 17.928 43.164 18 ;
     RECT  42.181 18 43.116 18.024 ;
     RECT  42.181 18.024 43.164 18.096 ;
     RECT  42.181 18.096 43.116 18.12 ;
     RECT  42.181 18.12 43.164 18.192 ;
     RECT  42.181 18.192 43.116 18.216 ;
     RECT  42.181 18.216 43.164 18.288 ;
     RECT  42.181 18.288 43.116 18.312 ;
     RECT  42.181 18.312 43.164 18.384 ;
     RECT  42.181 18.384 43.116 18.408 ;
     RECT  42.181 18.408 43.164 18.48 ;
     RECT  42.181 18.48 43.116 18.504 ;
     RECT  42.181 18.504 43.164 18.576 ;
     RECT  42.181 18.576 43.116 18.6 ;
     RECT  42.181 18.6 43.164 18.672 ;
     RECT  42.181 18.672 43.116 18.696 ;
     RECT  42.181 18.696 43.164 18.768 ;
     RECT  42.181 18.768 43.116 18.792 ;
     RECT  42.181 18.792 43.164 18.864 ;
     RECT  42.181 18.864 43.116 18.888 ;
     RECT  42.181 18.888 43.164 18.96 ;
     RECT  42.181 18.96 43.116 18.984 ;
     RECT  42.181 18.984 43.164 19.056 ;
     RECT  42.181 19.056 43.116 19.08 ;
     RECT  42.181 19.08 43.164 19.92 ;
     RECT  42.181 19.92 43.116 19.944 ;
     RECT  42.181 19.944 43.164 20.016 ;
     RECT  42.181 20.016 43.116 20.04 ;
     RECT  42.181 20.04 43.164 20.112 ;
     RECT  42.181 20.112 43.116 20.136 ;
     RECT  42.181 20.136 43.164 20.208 ;
     RECT  42.181 20.208 43.116 20.232 ;
     RECT  42.181 20.232 43.164 20.304 ;
     RECT  42.181 20.304 43.116 20.328 ;
     RECT  42.181 20.328 43.164 20.4 ;
     RECT  42.181 20.4 43.116 20.424 ;
     RECT  42.181 20.424 43.164 20.496 ;
     RECT  42.181 20.496 43.116 20.52 ;
     RECT  42.181 20.52 43.164 20.592 ;
     RECT  42.181 20.592 43.116 20.616 ;
     RECT  42.181 20.616 43.164 20.688 ;
     RECT  42.181 20.688 43.116 20.712 ;
     RECT  42.181 20.712 43.164 20.784 ;
     RECT  42.181 20.784 43.116 20.808 ;
     RECT  42.181 20.808 43.164 20.88 ;
     RECT  42.181 20.88 43.116 20.904 ;
     RECT  42.181 20.904 43.164 20.976 ;
     RECT  42.181 20.976 43.116 21 ;
     RECT  42.181 21 43.164 21.072 ;
     RECT  42.181 21.072 43.116 21.096 ;
     RECT  42.181 21.096 43.164 21.168 ;
     RECT  42.181 21.168 43.116 21.192 ;
     RECT  42.181 21.192 43.164 21.264 ;
     RECT  42.181 21.264 43.116 21.288 ;
     RECT  42.181 21.288 43.164 21.36 ;
     RECT  42.181 21.36 43.116 21.384 ;
     RECT  42.181 21.384 43.164 21.456 ;
     RECT  42.181 21.456 43.116 21.48 ;
     RECT  42.181 21.48 43.164 21.552 ;
     RECT  42.181 21.552 43.116 21.576 ;
     RECT  42.181 21.576 43.164 21.648 ;
     RECT  42.181 21.648 43.116 21.672 ;
     RECT  42.181 21.672 43.164 21.744 ;
     RECT  42.181 21.744 43.116 21.768 ;
     RECT  42.181 21.768 43.164 21.84 ;
     RECT  42.181 21.84 43.116 21.864 ;
     RECT  42.181 21.864 43.164 21.936 ;
     RECT  42.181 21.936 43.116 21.96 ;
     RECT  42.181 21.96 43.164 22.032 ;
     RECT  42.181 22.032 43.116 22.056 ;
     RECT  42.181 22.056 43.164 22.128 ;
     RECT  42.181 22.128 43.116 22.152 ;
     RECT  42.181 22.152 43.164 22.224 ;
     RECT  42.181 22.224 43.116 22.248 ;
     RECT  42.181 22.248 43.164 22.32 ;
     RECT  42.181 22.32 43.116 22.344 ;
     RECT  42.181 22.344 43.164 22.416 ;
     RECT  42.181 22.416 43.116 22.44 ;
     RECT  42.181 22.44 43.164 22.512 ;
     RECT  42.181 22.512 43.116 22.536 ;
     RECT  42.181 22.536 43.164 22.608 ;
     RECT  42.181 22.608 43.116 22.632 ;
     RECT  42.181 22.632 43.164 22.704 ;
     RECT  42.181 22.704 43.116 22.728 ;
     RECT  42.181 22.728 43.164 22.8 ;
     RECT  42.181 22.8 43.116 22.824 ;
     RECT  42.181 22.824 43.164 22.896 ;
     RECT  42.181 22.896 43.116 22.92 ;
    LAYER M5 ;
     RECT  6.888 0.016 6.96 0.084 ;
     RECT  6.984 0.016 7.056 0.084 ;
     RECT  7.08 0.016 7.152 0.084 ;
     RECT  7.176 0.016 7.248 0.084 ;
     RECT  7.272 0.016 7.344 0.084 ;
     RECT  7.368 0.016 7.44 0.084 ;
     RECT  7.464 0.016 7.536 0.084 ;
     RECT  7.56 0.016 7.632 0.084 ;
     RECT  7.656 0.016 7.728 0.084 ;
     RECT  7.752 0.016 7.824 0.084 ;
     RECT  7.848 0.016 7.92 0.084 ;
     RECT  7.944 0.016 8.016 0.084 ;
     RECT  8.04 0.016 8.112 0.084 ;
     RECT  8.136 0.016 8.208 0.084 ;
     RECT  8.232 0.016 8.304 0.084 ;
     RECT  8.328 0.016 8.4 0.084 ;
     RECT  8.424 0.016 8.496 0.084 ;
     RECT  8.52 0.016 8.592 0.084 ;
     RECT  8.616 0.016 8.688 0.084 ;
     RECT  8.712 0.016 8.784 0.084 ;
     RECT  8.808 0.016 8.88 0.084 ;
     RECT  8.904 0.016 8.976 0.084 ;
     RECT  9 0.016 9.072 0.084 ;
     RECT  9.096 0.016 9.168 0.084 ;
     RECT  9.192 0.016 9.264 0.084 ;
     RECT  9.288 0.016 9.36 0.084 ;
     RECT  9.384 0.016 9.456 0.084 ;
     RECT  9.48 0.016 9.552 0.084 ;
     RECT  9.576 0.016 9.648 0.084 ;
     RECT  9.672 0.016 9.744 0.084 ;
     RECT  9.768 0.016 9.84 0.084 ;
     RECT  9.864 0.016 9.936 0.084 ;
     RECT  9.96 0.016 10.032 0.084 ;
     RECT  10.056 0.016 10.128 0.084 ;
     RECT  10.152 0.016 10.224 0.084 ;
     RECT  10.248 0.016 10.32 0.084 ;
     RECT  10.344 0.016 10.416 0.084 ;
     RECT  10.44 0.016 10.512 0.084 ;
     RECT  10.536 0.016 10.608 0.084 ;
     RECT  10.632 0.016 10.704 0.084 ;
     RECT  10.728 0.016 10.8 0.084 ;
     RECT  10.824 0.016 10.896 0.084 ;
     RECT  10.92 0.016 10.992 0.084 ;
     RECT  11.016 0.016 11.088 0.084 ;
     RECT  11.112 0.016 11.184 0.084 ;
     RECT  11.208 0.016 11.28 0.084 ;
     RECT  11.304 0.016 11.376 0.084 ;
     RECT  11.4 0.016 11.472 0.084 ;
     RECT  11.496 0.016 11.568 0.084 ;
     RECT  11.592 0.016 11.664 0.084 ;
     RECT  11.688 0.016 11.76 0.084 ;
     RECT  11.784 0.016 11.856 0.084 ;
     RECT  11.88 0.016 11.952 0.084 ;
     RECT  11.976 0.016 12.048 0.084 ;
     RECT  12.072 0.016 12.144 0.084 ;
     RECT  12.168 0.016 12.24 0.084 ;
     RECT  12.264 0.016 12.336 0.084 ;
     RECT  12.36 0.016 12.432 0.084 ;
     RECT  12.456 0.016 12.528 0.084 ;
     RECT  12.552 0.016 12.624 0.084 ;
     RECT  12.648 0.016 12.72 0.084 ;
     RECT  12.744 0.016 12.816 0.084 ;
     RECT  12.84 0.016 12.912 0.084 ;
     RECT  12.936 0.016 13.008 0.084 ;
     RECT  13.032 0.016 13.104 0.084 ;
     RECT  13.128 0.016 13.2 0.084 ;
     RECT  13.224 0.016 13.296 0.084 ;
     RECT  6.864 0.084 13.32 0.181 ;
     RECT  2.4 2.137 2.52 2.151 ;
     RECT  18.6 2.137 18.72 2.151 ;
     RECT  24 2.137 24.12 2.151 ;
     RECT  29.4 2.137 29.52 2.151 ;
     RECT  34.8 2.137 34.92 2.151 ;
     RECT  40.2 2.137 40.32 2.151 ;
     RECT  6.864 0.181 13.656 2.245 ;
     RECT  5.136 2.629 5.16 2.725 ;
     RECT  2.4 2.151 2.712 2.773 ;
     RECT  6.864 2.245 13.848 2.821 ;
     RECT  0.144 1.381 0.168 2.869 ;
     RECT  4.224 2.725 5.16 3.157 ;
     RECT  6.576 2.821 13.848 3.157 ;
     RECT  0.144 2.869 0.312 3.203 ;
     RECT  2.4 2.773 3.24 3.397 ;
     RECT  4.224 3.157 13.848 3.397 ;
     RECT  15.456 3.205 15.48 3.877 ;
     RECT  0.288 3.203 0.312 3.973 ;
     RECT  15.456 3.877 15.576 4.165 ;
     RECT  15.408 4.165 15.576 5.125 ;
     RECT  2.4 3.397 13.848 5.173 ;
     RECT  2.4 5.173 14.28 5.461 ;
     RECT  20.4 5.461 20.424 5.557 ;
     RECT  0.288 3.973 0.408 5.701 ;
     RECT  2.4 5.461 14.424 5.893 ;
     RECT  15.408 5.125 16.536 5.893 ;
     RECT  0.24 5.701 0.408 5.941 ;
     RECT  29.4 2.151 29.712 6.085 ;
     RECT  0.192 5.941 0.456 6.323 ;
     RECT  2.4 5.893 16.536 6.323 ;
     RECT  24 2.151 24.312 6.373 ;
     RECT  18.6 2.151 18.912 6.613 ;
     RECT  20.4 5.557 21.384 6.613 ;
     RECT  24 6.373 24.936 6.805 ;
     RECT  30.768 6.085 30.792 6.851 ;
     RECT  28.992 6.085 29.712 7.043 ;
     RECT  0.192 6.323 0.408 7.237 ;
     RECT  24 6.805 25.656 7.333 ;
     RECT  0.144 7.237 0.408 7.523 ;
     RECT  23.328 7.333 25.656 7.859 ;
     RECT  0.144 7.523 0.312 8.147 ;
     RECT  18.6 6.613 21.384 8.197 ;
     RECT  23.328 7.859 24.936 8.197 ;
     RECT  18.6 8.197 24.936 8.435 ;
     RECT  0.144 8.147 0.168 8.579 ;
     RECT  16.512 6.323 16.536 8.579 ;
     RECT  18.6 8.435 22.44 8.771 ;
     RECT  21.36 8.771 22.44 9.347 ;
     RECT  24 8.435 24.936 9.541 ;
     RECT  2.4 6.323 15.528 9.827 ;
     RECT  3.84 9.827 15.528 9.875 ;
     RECT  24 9.541 25.128 9.877 ;
     RECT  27.792 7.861 27.816 10.211 ;
     RECT  31.92 7.957 31.944 10.355 ;
     RECT  17.04 9.637 17.064 10.405 ;
     RECT  26.16 9.301 26.184 10.645 ;
     RECT  21.36 9.347 21.768 10.691 ;
     RECT  16.848 10.405 17.064 10.693 ;
     RECT  21.744 10.691 21.768 10.837 ;
     RECT  14.784 9.875 15.528 10.885 ;
     RECT  36.096 6.805 36.12 10.979 ;
     RECT  23.376 9.877 25.128 11.027 ;
     RECT  18.6 8.771 20.376 11.123 ;
     RECT  0.144 9.925 0.168 11.219 ;
     RECT  2.4 9.827 2.712 11.365 ;
     RECT  3.84 9.875 13.512 11.365 ;
     RECT  18.6 11.123 19.944 11.459 ;
     RECT  21.744 10.837 22.344 11.459 ;
     RECT  23.424 11.027 25.128 11.459 ;
     RECT  26.16 10.645 26.232 11.459 ;
     RECT  14.784 10.885 15.672 11.507 ;
     RECT  16.848 10.693 17.304 11.507 ;
     RECT  15.312 11.507 15.672 11.509 ;
     RECT  16.848 11.507 16.872 11.509 ;
     RECT  22.32 11.459 22.344 11.699 ;
     RECT  19.92 11.459 19.944 11.795 ;
     RECT  23.424 11.459 24.312 11.795 ;
     RECT  15.312 11.509 16.872 12.179 ;
     RECT  26.16 11.459 26.184 12.275 ;
     RECT  23.712 11.795 24.312 12.517 ;
     RECT  29.4 7.043 29.712 13.093 ;
     RECT  15.648 12.179 16.872 13.187 ;
     RECT  23.712 12.517 24.84 13.283 ;
     RECT  0.144 12.517 0.168 13.331 ;
     RECT  28.56 13.093 29.712 13.573 ;
     RECT  30.816 13.045 30.84 13.573 ;
     RECT  15.648 13.187 15.96 13.619 ;
     RECT  28.56 13.573 30.84 13.715 ;
     RECT  18.6 11.459 18.912 14.005 ;
     RECT  40.2 2.151 40.512 14.053 ;
     RECT  40.08 14.053 40.512 14.195 ;
     RECT  29.4 13.715 30.072 14.387 ;
     RECT  15.888 13.619 15.96 14.435 ;
     RECT  0.144 14.485 0.168 14.675 ;
     RECT  2.4 11.365 13.512 14.821 ;
     RECT  2.4 14.821 13.8 14.965 ;
     RECT  15.072 14.773 15.096 14.965 ;
     RECT  34.8 2.151 35.112 15.589 ;
     RECT  29.4 14.387 29.832 15.827 ;
     RECT  2.4 14.965 15.096 15.925 ;
     RECT  31.104 15.301 31.128 16.019 ;
     RECT  2.4 15.925 16.008 16.117 ;
     RECT  0.144 15.685 0.168 16.165 ;
     RECT  26.784 14.197 26.808 16.213 ;
     RECT  26.256 16.213 26.808 16.259 ;
     RECT  43.008 16.021 43.032 16.307 ;
     RECT  34.8 15.589 35.544 16.547 ;
     RECT  0.144 16.165 0.408 16.643 ;
     RECT  2.4 16.117 16.488 16.837 ;
     RECT  33.552 10.213 33.576 17.123 ;
     RECT  26.256 16.259 26.28 17.219 ;
     RECT  18.6 14.005 19.032 17.557 ;
     RECT  32.496 16.789 32.52 17.843 ;
     RECT  0.24 16.643 0.408 17.939 ;
     RECT  0.24 17.939 0.312 17.987 ;
     RECT  20.304 13.045 20.328 18.565 ;
     RECT  18.288 17.557 19.032 18.613 ;
     RECT  23.712 13.283 24.312 18.613 ;
     RECT  23.136 18.613 24.312 18.709 ;
     RECT  23.088 18.709 24.312 18.757 ;
     RECT  2.4 16.837 17.016 18.851 ;
     RECT  29.4 15.827 29.712 18.949 ;
     RECT  29.088 18.949 29.712 19.333 ;
     RECT  0.144 17.989 0.216 19.379 ;
     RECT  22.512 18.757 24.312 19.525 ;
     RECT  28.176 19.333 29.712 19.571 ;
     RECT  22.416 19.525 24.312 19.573 ;
     RECT  2.4 18.851 2.856 19.619 ;
     RECT  0.192 19.379 0.216 19.763 ;
     RECT  18.096 18.613 19.032 19.861 ;
     RECT  3.84 18.851 17.016 19.909 ;
     RECT  18.096 19.861 19.272 19.909 ;
     RECT  32.064 19.717 32.088 20.099 ;
     RECT  26.784 19.957 26.808 20.147 ;
     RECT  20.304 18.565 21.192 20.245 ;
     RECT  22.32 19.573 24.312 20.245 ;
     RECT  3.84 19.909 19.272 20.437 ;
     RECT  20.304 20.245 24.312 20.437 ;
     RECT  28.176 19.571 28.2 20.437 ;
     RECT  29.28 19.571 29.712 20.725 ;
     RECT  29.28 20.725 29.832 20.915 ;
     RECT  3.84 20.437 24.312 20.917 ;
     RECT  3.792 20.917 24.312 21.107 ;
     RECT  27.36 20.437 28.2 21.155 ;
     RECT  30.96 21.157 30.984 21.347 ;
     RECT  22.32 21.107 24.312 21.637 ;
     RECT  3.792 21.107 21.192 22.165 ;
     RECT  22.32 21.637 24.936 22.165 ;
     RECT  34.8 16.547 35.112 22.165 ;
     RECT  28.176 21.155 28.2 22.741 ;
     RECT  29.28 20.915 29.712 22.741 ;
     RECT  34.8 22.165 35.352 22.787 ;
     RECT  26.208 20.725 26.232 22.789 ;
     RECT  3.792 22.165 24.936 22.835 ;
     RECT  2.4 19.619 2.712 22.837 ;
     RECT  26.208 22.789 26.808 23.029 ;
     RECT  26.208 23.029 26.904 23.315 ;
     RECT  2.4 22.837 2.808 23.317 ;
     RECT  3.792 22.835 17.016 23.317 ;
     RECT  18.096 22.835 24.936 23.651 ;
     RECT  28.176 22.741 29.712 23.701 ;
     RECT  18.096 23.651 24.696 24.131 ;
     RECT  18.096 24.131 22.44 24.563 ;
     RECT  23.424 24.131 24.696 24.563 ;
     RECT  32.256 22.741 32.28 24.563 ;
     RECT  26.64 23.315 26.904 24.613 ;
     RECT  0.144 20.629 0.168 24.707 ;
     RECT  2.4 23.317 17.016 24.755 ;
     RECT  16.992 24.755 17.016 24.853 ;
     RECT  18.096 24.563 21.768 24.853 ;
     RECT  16.992 24.853 21.768 24.995 ;
     RECT  31.152 23.893 31.176 25.045 ;
     RECT  25.776 24.613 26.904 25.093 ;
     RECT  27.888 23.701 29.712 25.093 ;
     RECT  23.424 24.563 24.408 25.621 ;
     RECT  2.4 24.755 15.96 25.813 ;
     RECT  16.992 24.995 17.016 25.813 ;
     RECT  23.328 25.621 24.408 25.861 ;
     RECT  25.776 25.093 29.712 25.861 ;
     RECT  33.648 23.893 33.672 25.955 ;
     RECT  23.328 25.861 29.712 26.101 ;
     RECT  31.152 25.045 31.704 26.101 ;
     RECT  34.8 22.787 35.112 26.197 ;
     RECT  0.288 25.189 0.312 26.291 ;
     RECT  23.328 26.101 31.896 26.291 ;
     RECT  2.4 25.813 17.016 26.483 ;
     RECT  23.328 26.291 26.808 26.579 ;
     RECT  18.096 24.995 21.768 26.629 ;
     RECT  23.328 26.579 26.664 26.629 ;
     RECT  7.68 26.483 17.016 26.819 ;
     RECT  16.848 26.819 17.016 26.867 ;
     RECT  33.888 26.197 35.112 27.301 ;
     RECT  7.68 26.819 15.096 27.395 ;
     RECT  18.096 26.629 26.664 27.395 ;
     RECT  27.984 26.291 31.896 27.395 ;
     RECT  18.096 27.395 19.224 27.443 ;
     RECT  7.68 27.395 9.768 27.491 ;
     RECT  18.096 27.443 19.08 27.637 ;
     RECT  10.944 27.395 15.096 27.683 ;
     RECT  27.984 27.395 31.56 27.683 ;
     RECT  28.176 27.683 31.56 27.923 ;
     RECT  2.4 26.483 6.552 27.971 ;
     RECT  7.68 27.491 8.112 27.971 ;
     RECT  16.992 26.867 17.016 27.971 ;
     RECT  33.312 27.301 35.112 27.971 ;
     RECT  2.4 27.971 5.016 28.067 ;
     RECT  11.424 27.683 15.096 28.115 ;
     RECT  2.4 28.067 3.48 28.211 ;
     RECT  11.808 28.115 15.096 28.211 ;
     RECT  4.992 28.067 5.016 28.259 ;
     RECT  20.304 27.395 26.664 28.261 ;
     RECT  9.744 27.491 9.768 28.451 ;
     RECT  11.808 28.211 13.8 28.499 ;
     RECT  28.176 27.923 31.032 28.645 ;
     RECT  11.856 28.499 13.8 29.315 ;
     RECT  20.304 28.261 26.808 29.317 ;
     RECT  28.08 28.645 31.032 29.317 ;
     RECT  18 27.637 19.08 29.749 ;
     RECT  20.304 29.317 31.032 29.749 ;
     RECT  17.952 29.749 31.032 29.795 ;
     RECT  15.12 28.789 15.144 29.845 ;
     RECT  21.072 29.795 31.032 29.891 ;
     RECT  23.52 29.891 25.656 30.035 ;
     RECT  12.288 29.315 13.8 30.181 ;
     RECT  15.12 29.845 15.288 30.181 ;
     RECT  26.784 29.891 31.032 30.275 ;
     RECT  26.784 30.275 29.88 30.323 ;
     RECT  34.8 27.971 35.112 30.325 ;
     RECT  19.968 29.795 20.088 30.371 ;
     RECT  21.072 29.891 22.344 30.371 ;
     RECT  23.52 30.035 24.888 30.467 ;
     RECT  31.008 30.275 31.032 30.563 ;
     RECT  21.072 30.371 22.248 31.091 ;
     RECT  28.08 30.323 29.88 31.139 ;
     RECT  21.648 31.091 21.72 31.187 ;
     RECT  17.952 29.795 18.912 31.429 ;
     RECT  23.568 30.467 24.888 31.429 ;
     RECT  21.696 31.187 21.72 31.523 ;
     RECT  23.376 31.429 24.888 31.525 ;
     RECT  6.528 27.971 6.552 31.811 ;
     RECT  28.176 31.139 29.88 31.955 ;
     RECT  16.56 31.333 16.584 31.957 ;
     RECT  22.896 31.525 24.888 32.149 ;
     RECT  12.288 30.181 15.288 32.195 ;
     RECT  16.56 31.957 16.968 32.197 ;
     RECT  17.952 31.429 19.08 32.197 ;
     RECT  26.784 30.323 26.808 32.197 ;
     RECT  28.176 31.955 29.832 32.197 ;
     RECT  22.464 32.149 24.888 32.291 ;
     RECT  12.288 32.195 15.144 32.339 ;
     RECT  20.064 30.371 20.088 32.437 ;
     RECT  16.56 32.197 19.08 32.531 ;
     RECT  26.784 32.197 29.832 32.579 ;
     RECT  20.064 32.437 20.28 32.723 ;
     RECT  16.56 32.531 18.912 32.867 ;
     RECT  20.16 32.723 20.28 32.867 ;
     RECT  26.784 32.579 28.2 33.205 ;
     RECT  26.736 33.205 28.2 33.251 ;
     RECT  16.56 32.867 16.584 33.541 ;
     RECT  12.288 32.339 14.856 33.589 ;
     RECT  15.984 33.541 16.584 33.589 ;
     RECT  25.632 33.013 25.656 33.683 ;
     RECT  20.16 32.867 20.184 34.163 ;
     RECT  17.904 32.867 18.912 34.691 ;
     RECT  22.896 32.291 24.312 34.787 ;
     RECT  17.952 34.691 18.912 34.835 ;
     RECT  25.488 33.925 25.512 34.931 ;
     RECT  18.24 34.835 18.912 35.749 ;
     RECT  20.448 34.165 20.472 35.795 ;
     RECT  24 34.787 24.312 36.277 ;
     RECT  25.68 36.181 25.704 36.277 ;
     RECT  29.4 32.579 29.832 36.277 ;
     RECT  20.4 35.941 20.424 36.323 ;
     RECT  22.272 34.933 22.824 36.323 ;
     RECT  12.288 33.589 16.584 36.515 ;
     RECT  22.8 36.323 22.824 36.515 ;
     RECT  26.736 33.251 26.76 36.515 ;
     RECT  29.232 36.277 29.832 36.517 ;
     RECT  30.864 35.845 30.888 36.517 ;
     RECT  28.176 33.251 28.2 36.563 ;
     RECT  29.232 36.517 30.888 36.661 ;
     RECT  18.24 35.749 19.032 36.803 ;
     RECT  29.232 36.661 31.752 36.997 ;
     RECT  33.312 27.971 33.336 36.997 ;
     RECT  16.56 36.515 16.584 37.043 ;
     RECT  24 36.277 25.704 37.043 ;
     RECT  29.232 36.997 33.336 37.141 ;
     RECT  18.24 36.803 18.912 37.187 ;
     RECT  29.136 37.141 33.336 37.573 ;
     RECT  28.992 37.573 33.336 37.957 ;
     RECT  28.704 37.957 33.336 38.053 ;
     RECT  34.8 30.325 35.208 38.053 ;
     RECT  24 37.043 24.504 38.195 ;
     RECT  28.704 38.053 35.208 38.291 ;
     RECT  28.704 38.291 33.336 38.435 ;
     RECT  12.288 36.515 13.512 38.723 ;
     RECT  28.992 38.435 33.336 39.539 ;
     RECT  24 38.195 24.456 39.683 ;
     RECT  34.8 38.291 35.208 39.827 ;
     RECT  18.6 37.187 18.912 39.829 ;
     RECT  25.68 37.043 25.704 39.877 ;
     RECT  16.944 39.877 16.968 40.453 ;
     RECT  25.584 39.877 25.704 40.453 ;
     RECT  27.12 39.301 27.144 40.453 ;
     RECT  18.6 39.829 19.656 40.499 ;
     RECT  25.584 40.453 25.992 40.501 ;
     RECT  27.12 40.453 27.72 40.501 ;
     RECT  28.992 39.539 32.904 40.645 ;
     RECT  15.696 40.453 16.968 40.693 ;
     RECT  15.312 40.693 16.968 40.837 ;
     RECT  18.6 40.499 18.912 40.837 ;
     RECT  24 39.683 24.408 40.885 ;
     RECT  25.584 40.501 27.72 40.885 ;
     RECT  24 40.885 27.72 40.933 ;
     RECT  28.992 40.645 33.096 40.933 ;
     RECT  15.312 40.837 18.912 40.981 ;
     RECT  2.4 28.211 2.712 41.049 ;
     RECT  7.8 27.971 8.112 41.049 ;
     RECT  13.2 38.723 13.512 41.049 ;
     RECT  15.216 40.981 18.912 41.049 ;
     RECT  34.8 39.827 35.112 41.049 ;
     RECT  40.2 14.195 40.512 41.049 ;
     RECT  2.4 41.049 2.52 41.063 ;
     RECT  7.8 41.049 7.92 41.063 ;
     RECT  13.2 41.049 13.32 41.063 ;
     RECT  15.216 41.049 18.72 41.063 ;
     RECT  24 40.933 33.096 41.063 ;
     RECT  34.8 41.049 34.92 41.063 ;
     RECT  40.2 41.049 40.32 41.063 ;
     RECT  24.048 41.063 33.096 42.997 ;
     RECT  15.216 41.063 17.832 43.116 ;
     RECT  15.24 43.116 15.312 43.152 ;
     RECT  15.336 43.116 15.408 43.152 ;
     RECT  15.432 43.116 15.504 43.152 ;
     RECT  15.528 43.116 15.6 43.152 ;
     RECT  15.624 43.116 15.696 43.152 ;
     RECT  15.72 43.116 15.792 43.152 ;
     RECT  15.816 43.116 15.888 43.152 ;
     RECT  15.912 43.116 15.984 43.152 ;
     RECT  16.008 43.116 16.08 43.152 ;
     RECT  16.104 43.116 16.176 43.152 ;
     RECT  16.2 43.116 16.272 43.152 ;
     RECT  16.296 43.116 16.368 43.152 ;
     RECT  16.392 43.116 16.464 43.152 ;
     RECT  16.488 43.116 16.56 43.152 ;
     RECT  16.584 43.116 16.656 43.152 ;
     RECT  16.68 43.116 16.752 43.152 ;
     RECT  16.776 43.116 16.848 43.152 ;
     RECT  16.872 43.116 16.944 43.152 ;
     RECT  16.968 43.116 17.04 43.152 ;
     RECT  17.064 43.116 17.136 43.152 ;
     RECT  17.16 43.116 17.232 43.152 ;
     RECT  17.256 43.116 17.328 43.152 ;
     RECT  17.352 43.116 17.424 43.152 ;
     RECT  17.448 43.116 17.52 43.152 ;
     RECT  17.544 43.116 17.616 43.152 ;
     RECT  17.64 43.116 17.712 43.152 ;
     RECT  17.736 43.116 17.808 43.152 ;
     RECT  24.048 42.997 33.288 43.116 ;
     RECT  24.072 43.116 24.144 43.152 ;
     RECT  24.168 43.116 24.24 43.152 ;
     RECT  24.264 43.116 24.336 43.152 ;
     RECT  24.36 43.116 24.432 43.152 ;
     RECT  24.456 43.116 24.528 43.152 ;
     RECT  24.552 43.116 24.624 43.152 ;
     RECT  24.648 43.116 24.72 43.152 ;
     RECT  24.744 43.116 24.816 43.152 ;
     RECT  24.84 43.116 24.912 43.152 ;
     RECT  24.936 43.116 25.008 43.152 ;
     RECT  25.032 43.116 25.104 43.152 ;
     RECT  25.128 43.116 25.2 43.152 ;
     RECT  25.224 43.116 25.296 43.152 ;
     RECT  25.32 43.116 25.392 43.152 ;
     RECT  25.416 43.116 25.488 43.152 ;
     RECT  25.512 43.116 25.584 43.152 ;
     RECT  25.608 43.116 25.68 43.152 ;
     RECT  25.704 43.116 25.776 43.152 ;
     RECT  25.8 43.116 25.872 43.152 ;
     RECT  25.896 43.116 25.968 43.152 ;
     RECT  25.992 43.116 26.064 43.152 ;
     RECT  26.088 43.116 26.16 43.152 ;
     RECT  26.184 43.116 26.256 43.152 ;
     RECT  26.28 43.116 26.352 43.152 ;
     RECT  26.376 43.116 26.448 43.152 ;
     RECT  26.472 43.116 26.544 43.152 ;
     RECT  26.568 43.116 26.64 43.152 ;
     RECT  26.664 43.116 26.736 43.152 ;
     RECT  26.76 43.116 26.832 43.152 ;
     RECT  26.856 43.116 26.928 43.152 ;
     RECT  26.952 43.116 27.024 43.152 ;
     RECT  27.048 43.116 27.12 43.152 ;
     RECT  27.144 43.116 27.216 43.152 ;
     RECT  27.24 43.116 27.312 43.152 ;
     RECT  27.336 43.116 27.408 43.152 ;
     RECT  27.432 43.116 27.504 43.152 ;
     RECT  27.528 43.116 27.6 43.152 ;
     RECT  27.624 43.116 27.696 43.152 ;
     RECT  27.72 43.116 27.792 43.152 ;
     RECT  27.816 43.116 27.888 43.152 ;
     RECT  27.912 43.116 27.984 43.152 ;
     RECT  28.008 43.116 28.08 43.152 ;
     RECT  28.104 43.116 28.176 43.152 ;
     RECT  28.2 43.116 28.272 43.152 ;
     RECT  28.296 43.116 28.368 43.152 ;
     RECT  28.392 43.116 28.464 43.152 ;
     RECT  28.488 43.116 28.56 43.152 ;
     RECT  28.584 43.116 28.656 43.152 ;
     RECT  28.68 43.116 28.752 43.152 ;
     RECT  28.776 43.116 28.848 43.152 ;
     RECT  28.872 43.116 28.944 43.152 ;
     RECT  28.968 43.116 29.04 43.152 ;
     RECT  29.064 43.116 29.136 43.152 ;
     RECT  29.16 43.116 29.232 43.152 ;
     RECT  29.256 43.116 29.328 43.152 ;
     RECT  29.352 43.116 29.424 43.152 ;
     RECT  29.448 43.116 29.52 43.152 ;
     RECT  29.544 43.116 29.616 43.152 ;
     RECT  29.64 43.116 29.712 43.152 ;
     RECT  29.736 43.116 29.808 43.152 ;
     RECT  29.832 43.116 29.904 43.152 ;
     RECT  29.928 43.116 30 43.152 ;
     RECT  30.024 43.116 30.096 43.152 ;
     RECT  30.12 43.116 30.192 43.152 ;
     RECT  30.216 43.116 30.288 43.152 ;
     RECT  30.312 43.116 30.384 43.152 ;
     RECT  30.408 43.116 30.48 43.152 ;
     RECT  30.504 43.116 30.576 43.152 ;
     RECT  30.6 43.116 30.672 43.152 ;
     RECT  30.696 43.116 30.768 43.152 ;
     RECT  30.792 43.116 30.864 43.152 ;
     RECT  30.888 43.116 30.96 43.152 ;
     RECT  30.984 43.116 31.056 43.152 ;
     RECT  31.08 43.116 31.152 43.152 ;
     RECT  31.176 43.116 31.248 43.152 ;
     RECT  31.272 43.116 31.344 43.152 ;
     RECT  31.368 43.116 31.44 43.152 ;
     RECT  31.464 43.116 31.536 43.152 ;
     RECT  31.56 43.116 31.632 43.152 ;
     RECT  31.656 43.116 31.728 43.152 ;
     RECT  31.752 43.116 31.824 43.152 ;
     RECT  31.848 43.116 31.92 43.152 ;
     RECT  31.944 43.116 32.016 43.152 ;
     RECT  32.04 43.116 32.112 43.152 ;
     RECT  32.136 43.116 32.208 43.152 ;
     RECT  32.232 43.116 32.304 43.152 ;
     RECT  32.328 43.116 32.4 43.152 ;
     RECT  32.424 43.116 32.496 43.152 ;
     RECT  32.52 43.116 32.592 43.152 ;
     RECT  32.616 43.116 32.688 43.152 ;
     RECT  32.712 43.116 32.784 43.152 ;
     RECT  32.808 43.116 32.88 43.152 ;
     RECT  32.904 43.116 32.976 43.152 ;
     RECT  33 43.116 33.072 43.152 ;
     RECT  33.096 43.116 33.168 43.152 ;
     RECT  33.192 43.116 33.288 43.152 ;
     RECT  33.264 43.152 33.288 43.187 ;
     RECT  2.712 2.725 4.224 2.773 ;
     RECT  3.24 2.773 4.224 3.397 ;
     RECT  5.16 2.821 6.576 3.157 ;
     RECT  14.28 5.173 15.408 5.461 ;
     RECT  14.424 5.461 15.408 5.893 ;
     RECT  18.912 5.461 20.4 6.613 ;
     RECT  29.712 6.085 30.768 6.851 ;
     RECT  15.528 6.323 16.512 8.579 ;
     RECT  35.112 6.805 36.096 10.979 ;
     RECT  24.936 7.859 25.656 9.301 ;
     RECT  22.44 8.435 24 9.347 ;
     RECT  15.528 8.579 16.536 9.637 ;
     RECT  20.376 8.771 21.36 10.691 ;
     RECT  24.936 9.301 26.16 9.541 ;
     RECT  21.768 9.347 24 9.877 ;
     RECT  25.128 9.541 26.16 11.459 ;
     RECT  15.528 9.637 17.04 10.405 ;
     RECT  2.712 9.827 3.84 11.365 ;
     RECT  13.512 9.875 14.784 11.507 ;
     RECT  21.768 9.877 23.376 10.837 ;
     RECT  33.576 10.213 34.8 17.123 ;
     RECT  15.528 10.405 16.848 10.885 ;
     RECT  20.376 10.691 21.744 11.123 ;
     RECT  17.304 10.693 18.6 11.507 ;
     RECT  22.344 10.837 23.376 11.027 ;
     RECT  15.672 10.885 16.848 11.509 ;
     RECT  22.344 11.027 23.424 11.699 ;
     RECT  18.912 11.459 19.92 11.795 ;
     RECT  24.312 11.459 26.16 12.275 ;
     RECT  18.912 11.795 19.944 13.045 ;
     RECT  24.312 12.275 24.84 12.517 ;
     RECT  18.912 13.045 20.304 14.005 ;
     RECT  29.712 13.045 30.816 13.573 ;
     RECT  15.648 13.619 15.888 14.435 ;
     RECT  19.032 14.005 20.304 19.861 ;
     RECT  29.832 14.387 30.072 15.301 ;
     RECT  15.648 14.435 15.96 14.773 ;
     RECT  15.096 14.773 15.96 15.925 ;
     RECT  13.8 14.821 15.072 14.965 ;
     RECT  29.832 15.301 31.104 15.827 ;
     RECT  29.712 15.827 31.104 16.019 ;
     RECT  0.18 16.643 0.24 17.987 ;
     RECT  32.52 16.789 33.552 17.123 ;
     RECT  17.016 17.557 18.288 18.613 ;
     RECT  0.18 17.987 0.216 17.989 ;
     RECT  17.016 18.613 18.096 19.909 ;
     RECT  21.192 18.757 22.512 19.525 ;
     RECT  2.856 18.851 3.84 19.619 ;
     RECT  21.192 19.525 22.416 19.573 ;
     RECT  28.2 19.571 29.28 22.741 ;
     RECT  21.192 19.573 22.32 20.245 ;
     RECT  2.712 19.619 3.84 20.917 ;
     RECT  19.272 19.861 20.304 20.437 ;
     RECT  26.808 19.957 28.176 20.147 ;
     RECT  26.784 20.147 28.176 20.437 ;
     RECT  26.784 20.437 27.36 20.725 ;
     RECT  26.232 20.725 27.36 21.155 ;
     RECT  29.712 20.915 29.832 21.157 ;
     RECT  2.712 20.917 3.792 22.837 ;
     RECT  21.192 21.107 22.32 22.165 ;
     RECT  29.712 21.157 30.96 21.347 ;
     RECT  24.936 21.637 26.208 23.315 ;
     RECT  26.808 22.789 28.176 23.029 ;
     RECT  17.016 22.835 18.096 24.853 ;
     RECT  2.808 22.837 3.792 23.317 ;
     RECT  26.904 23.029 28.176 23.701 ;
     RECT  24.936 23.315 26.64 23.651 ;
     RECT  24.696 23.651 26.64 24.563 ;
     RECT  26.904 23.701 27.888 25.093 ;
     RECT  29.712 23.893 31.152 26.101 ;
     RECT  31.176 23.893 32.256 24.563 ;
     RECT  32.28 23.893 33.648 24.563 ;
     RECT  33.672 23.893 34.8 25.955 ;
     RECT  22.44 24.131 23.424 24.563 ;
     RECT  23.328 24.563 23.424 25.621 ;
     RECT  24.408 24.563 26.64 24.613 ;
     RECT  31.176 24.563 31.704 25.045 ;
     RECT  24.408 24.613 25.776 25.861 ;
     RECT  15.96 24.755 16.992 25.813 ;
     RECT  17.016 24.995 18.096 27.637 ;
     RECT  33.648 25.955 34.8 26.197 ;
     RECT  33.648 26.197 33.888 27.301 ;
     RECT  26.808 26.291 27.984 26.579 ;
     RECT  6.552 26.483 7.68 27.971 ;
     RECT  26.664 26.579 27.984 27.683 ;
     RECT  31.896 27.301 33.312 27.395 ;
     RECT  9.768 27.395 10.944 27.683 ;
     RECT  19.224 27.395 20.304 27.443 ;
     RECT  19.08 27.443 20.304 29.749 ;
     RECT  17.016 27.637 18 27.971 ;
     RECT  26.664 27.683 28.176 28.261 ;
     RECT  5.016 27.971 6.528 28.259 ;
     RECT  6.552 27.971 7.8 31.811 ;
     RECT  33.336 27.971 34.8 38.053 ;
     RECT  3.48 28.067 4.992 28.211 ;
     RECT  13.8 28.211 15.096 28.789 ;
     RECT  26.808 28.261 28.176 28.645 ;
     RECT  26.808 28.645 28.08 29.317 ;
     RECT  13.8 28.789 15.12 30.181 ;
     RECT  18.912 29.795 19.968 30.371 ;
     RECT  20.088 29.795 21.072 31.091 ;
     RECT  22.344 29.891 23.52 30.371 ;
     RECT  25.656 29.891 26.784 30.035 ;
     RECT  29.88 30.275 31.008 30.563 ;
     RECT  26.808 30.323 28.08 31.139 ;
     RECT  18.912 30.371 20.064 31.429 ;
     RECT  22.248 30.371 23.52 30.467 ;
     RECT  22.248 30.467 23.568 31.091 ;
     RECT  20.088 31.091 21.648 31.187 ;
     RECT  21.72 31.091 23.568 31.429 ;
     RECT  26.808 31.139 28.176 32.197 ;
     RECT  20.088 31.187 21.696 31.523 ;
     RECT  15.288 31.333 16.56 32.195 ;
     RECT  16.584 31.333 17.952 31.957 ;
     RECT  19.08 31.429 20.064 32.531 ;
     RECT  21.72 31.429 23.376 31.523 ;
     RECT  20.088 31.523 20.28 32.437 ;
     RECT  22.464 31.523 23.376 31.525 ;
     RECT  22.464 31.525 22.896 32.149 ;
     RECT  16.968 31.957 17.952 32.197 ;
     RECT  15.144 32.195 16.56 32.339 ;
     RECT  24.312 32.291 24.888 33.013 ;
     RECT  14.856 32.339 16.56 33.541 ;
     RECT  18.912 32.531 20.064 32.723 ;
     RECT  28.2 32.579 29.4 36.277 ;
     RECT  18.912 32.723 20.16 34.163 ;
     RECT  16.584 32.867 17.904 34.691 ;
     RECT  24.312 33.013 25.632 33.683 ;
     RECT  25.656 33.013 26.784 33.205 ;
     RECT  25.656 33.205 26.736 33.683 ;
     RECT  26.76 33.251 28.176 36.515 ;
     RECT  14.856 33.541 15.984 33.589 ;
     RECT  24.312 33.683 26.736 33.925 ;
     RECT  24.312 33.925 25.488 34.931 ;
     RECT  25.512 33.925 26.736 34.931 ;
     RECT  16.584 34.691 17.952 34.835 ;
     RECT  22.896 34.787 24 34.933 ;
     RECT  24.312 34.931 26.736 36.181 ;
     RECT  22.824 34.933 24 36.515 ;
     RECT  19.032 35.749 20.448 35.795 ;
     RECT  19.032 35.795 20.424 35.941 ;
     RECT  29.832 35.845 30.864 36.517 ;
     RECT  19.032 35.941 20.4 36.323 ;
     RECT  24.312 36.181 25.68 36.277 ;
     RECT  25.704 36.181 26.736 36.515 ;
     RECT  28.2 36.277 29.232 36.563 ;
     RECT  28.704 36.563 29.232 37.141 ;
     RECT  24.504 37.043 25.68 38.195 ;
     RECT  28.704 37.141 29.136 37.573 ;
     RECT  28.704 37.573 28.992 37.957 ;
     RECT  24.456 38.195 25.68 39.683 ;
     RECT  33.336 38.291 34.8 39.539 ;
     RECT  25.704 39.301 27.12 40.453 ;
     RECT  32.904 39.539 33.096 40.645 ;
     RECT  24.408 39.683 25.68 39.877 ;
     RECT  24.408 39.877 25.584 40.885 ;
     RECT  25.992 40.453 27.12 40.501 ;
     RECT  27.72 40.453 28.992 40.933 ;
  END
END ot_qwen_tp8_pv_wide_ctl_tb
END LIBRARY
